VERSION 5.8 ;
BUSBITCHARS "[]" ;
DIVIDERCHAR "/" ;
UNITS
    DATABASE MICRONS 1000 ;
END UNITS

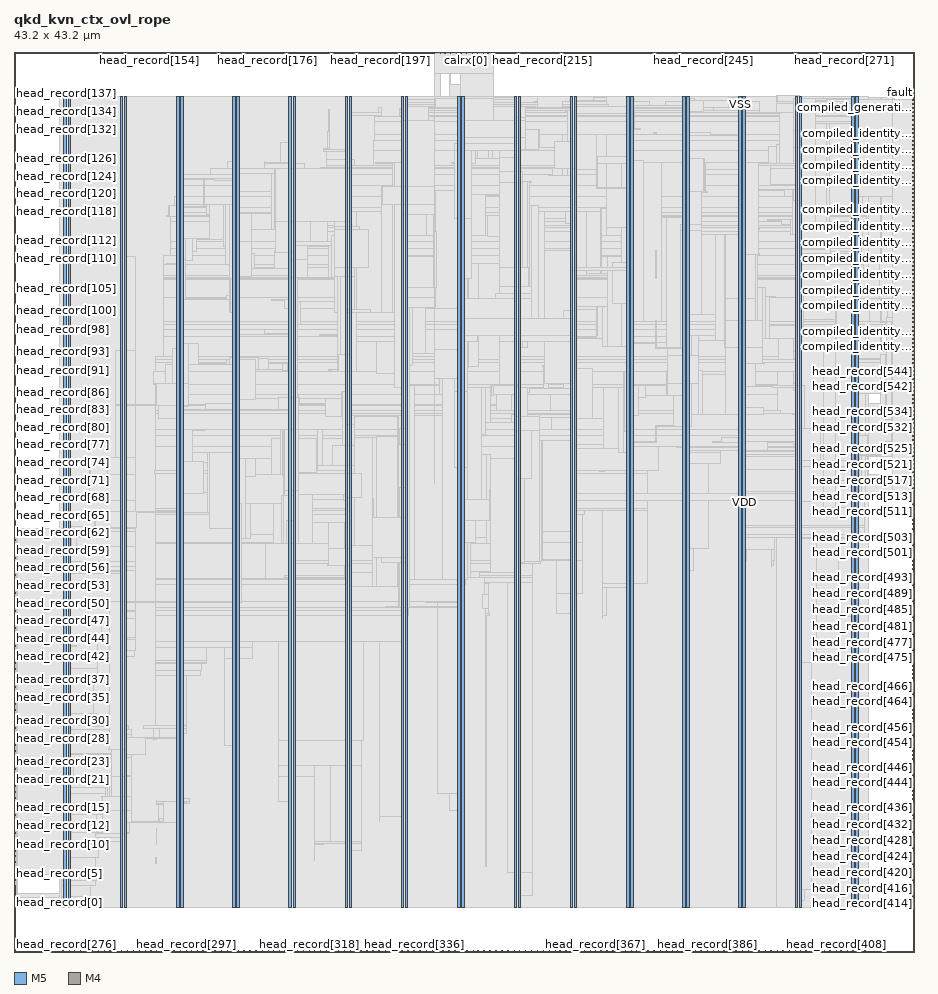
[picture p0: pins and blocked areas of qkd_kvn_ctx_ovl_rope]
MACRO qkd_kvn_ctx_ovl_rope
  FOREIGN qkd_kvn_ctx_ovl_rope 0 0 ;
  CLASS BLOCK ;
  SIZE 43.2 BY 43.2 ;
  PIN adm_done
    DIRECTION INPUT ;
    USE SIGNAL ;
    PORT
      LAYER M5 ;
        RECT  22.752 43.116 22.776 43.2 ;
    END
  END adm_done
  PIN calrx[0]
    DIRECTION INPUT ;
    USE SIGNAL ;
    PORT
      LAYER M5 ;
        RECT  21.696 43.116 21.72 43.2 ;
    END
  END calrx[0]
  PIN calrx[1]
    DIRECTION INPUT ;
    USE SIGNAL ;
    PORT
      LAYER M5 ;
        RECT  21.984 43.116 22.008 43.2 ;
    END
  END calrx[1]
  PIN calrx[2]
    DIRECTION INPUT ;
    USE SIGNAL ;
    PORT
      LAYER M5 ;
        RECT  22.224 43.116 22.248 43.2 ;
    END
  END calrx[2]
  PIN calrx[3]
    DIRECTION INPUT ;
    USE SIGNAL ;
    PORT
      LAYER M5 ;
        RECT  22.512 43.116 22.536 43.2 ;
    END
  END calrx[3]
  PIN ck
    DIRECTION INPUT ;
    USE SIGNAL ;
    PORT
      LAYER M5 ;
        RECT  20.16 43.116 20.184 43.2 ;
    END
  END ck
  PIN compiled_generation[0]
    DIRECTION OUTPUT ;
    USE SIGNAL ;
    PORT
      LAYER M4 ;
        RECT  43.116 40.512 43.2 40.536 ;
    END
  END compiled_generation[0]
  PIN compiled_generation[1]
    DIRECTION OUTPUT ;
    USE SIGNAL ;
    PORT
      LAYER M4 ;
        RECT  43.116 40.704 43.2 40.728 ;
    END
  END compiled_generation[1]
  PIN compiled_identity[0]
    DIRECTION OUTPUT ;
    USE SIGNAL ;
    PORT
      LAYER M4 ;
        RECT  43.116 29.04 43.2 29.064 ;
    END
  END compiled_identity[0]
  PIN compiled_identity[10]
    DIRECTION OUTPUT ;
    USE SIGNAL ;
    PORT
      LAYER M4 ;
        RECT  43.116 31.008 43.2 31.032 ;
    END
  END compiled_identity[10]
  PIN compiled_identity[11]
    DIRECTION OUTPUT ;
    USE SIGNAL ;
    PORT
      LAYER M4 ;
        RECT  43.116 31.2 43.2 31.224 ;
    END
  END compiled_identity[11]
  PIN compiled_identity[12]
    DIRECTION OUTPUT ;
    USE SIGNAL ;
    PORT
      LAYER M4 ;
        RECT  43.116 31.392 43.2 31.416 ;
    END
  END compiled_identity[12]
  PIN compiled_identity[13]
    DIRECTION OUTPUT ;
    USE SIGNAL ;
    PORT
      LAYER M4 ;
        RECT  43.116 31.584 43.2 31.608 ;
    END
  END compiled_identity[13]
  PIN compiled_identity[14]
    DIRECTION OUTPUT ;
    USE SIGNAL ;
    PORT
      LAYER M4 ;
        RECT  43.116 31.776 43.2 31.8 ;
    END
  END compiled_identity[14]
  PIN compiled_identity[15]
    DIRECTION OUTPUT ;
    USE SIGNAL ;
    PORT
      LAYER M4 ;
        RECT  43.116 31.968 43.2 31.992 ;
    END
  END compiled_identity[15]
  PIN compiled_identity[16]
    DIRECTION OUTPUT ;
    USE SIGNAL ;
    PORT
      LAYER M4 ;
        RECT  43.116 32.16 43.2 32.184 ;
    END
  END compiled_identity[16]
  PIN compiled_identity[17]
    DIRECTION OUTPUT ;
    USE SIGNAL ;
    PORT
      LAYER M4 ;
        RECT  43.116 32.352 43.2 32.376 ;
    END
  END compiled_identity[17]
  PIN compiled_identity[18]
    DIRECTION OUTPUT ;
    USE SIGNAL ;
    PORT
      LAYER M4 ;
        RECT  43.116 32.544 43.2 32.568 ;
    END
  END compiled_identity[18]
  PIN compiled_identity[19]
    DIRECTION OUTPUT ;
    USE SIGNAL ;
    PORT
      LAYER M4 ;
        RECT  43.116 32.736 43.2 32.76 ;
    END
  END compiled_identity[19]
  PIN compiled_identity[1]
    DIRECTION OUTPUT ;
    USE SIGNAL ;
    PORT
      LAYER M4 ;
        RECT  43.116 29.232 43.2 29.256 ;
    END
  END compiled_identity[1]
  PIN compiled_identity[20]
    DIRECTION OUTPUT ;
    USE SIGNAL ;
    PORT
      LAYER M4 ;
        RECT  43.116 32.928 43.2 32.952 ;
    END
  END compiled_identity[20]
  PIN compiled_identity[21]
    DIRECTION OUTPUT ;
    USE SIGNAL ;
    PORT
      LAYER M4 ;
        RECT  43.116 33.12 43.2 33.144 ;
    END
  END compiled_identity[21]
  PIN compiled_identity[22]
    DIRECTION OUTPUT ;
    USE SIGNAL ;
    PORT
      LAYER M4 ;
        RECT  43.116 33.312 43.2 33.336 ;
    END
  END compiled_identity[22]
  PIN compiled_identity[23]
    DIRECTION OUTPUT ;
    USE SIGNAL ;
    PORT
      LAYER M4 ;
        RECT  43.116 33.504 43.2 33.528 ;
    END
  END compiled_identity[23]
  PIN compiled_identity[24]
    DIRECTION OUTPUT ;
    USE SIGNAL ;
    PORT
      LAYER M4 ;
        RECT  43.116 33.696 43.2 33.72 ;
    END
  END compiled_identity[24]
  PIN compiled_identity[25]
    DIRECTION OUTPUT ;
    USE SIGNAL ;
    PORT
      LAYER M4 ;
        RECT  43.116 33.888 43.2 33.912 ;
    END
  END compiled_identity[25]
  PIN compiled_identity[26]
    DIRECTION OUTPUT ;
    USE SIGNAL ;
    PORT
      LAYER M4 ;
        RECT  43.116 34.08 43.2 34.104 ;
    END
  END compiled_identity[26]
  PIN compiled_identity[27]
    DIRECTION OUTPUT ;
    USE SIGNAL ;
    PORT
      LAYER M4 ;
        RECT  43.116 34.272 43.2 34.296 ;
    END
  END compiled_identity[27]
  PIN compiled_identity[28]
    DIRECTION OUTPUT ;
    USE SIGNAL ;
    PORT
      LAYER M4 ;
        RECT  43.116 34.464 43.2 34.488 ;
    END
  END compiled_identity[28]
  PIN compiled_identity[29]
    DIRECTION OUTPUT ;
    USE SIGNAL ;
    PORT
      LAYER M4 ;
        RECT  43.116 34.656 43.2 34.68 ;
    END
  END compiled_identity[29]
  PIN compiled_identity[2]
    DIRECTION OUTPUT ;
    USE SIGNAL ;
    PORT
      LAYER M4 ;
        RECT  43.116 29.424 43.2 29.448 ;
    END
  END compiled_identity[2]
  PIN compiled_identity[30]
    DIRECTION OUTPUT ;
    USE SIGNAL ;
    PORT
      LAYER M4 ;
        RECT  43.116 34.848 43.2 34.872 ;
    END
  END compiled_identity[30]
  PIN compiled_identity[31]
    DIRECTION OUTPUT ;
    USE SIGNAL ;
    PORT
      LAYER M4 ;
        RECT  43.116 35.088 43.2 35.112 ;
    END
  END compiled_identity[31]
  PIN compiled_identity[32]
    DIRECTION OUTPUT ;
    USE SIGNAL ;
    PORT
      LAYER M4 ;
        RECT  43.116 35.28 43.2 35.304 ;
    END
  END compiled_identity[32]
  PIN compiled_identity[33]
    DIRECTION OUTPUT ;
    USE SIGNAL ;
    PORT
      LAYER M4 ;
        RECT  43.116 35.472 43.2 35.496 ;
    END
  END compiled_identity[33]
  PIN compiled_identity[34]
    DIRECTION OUTPUT ;
    USE SIGNAL ;
    PORT
      LAYER M4 ;
        RECT  43.116 35.664 43.2 35.688 ;
    END
  END compiled_identity[34]
  PIN compiled_identity[35]
    DIRECTION OUTPUT ;
    USE SIGNAL ;
    PORT
      LAYER M4 ;
        RECT  43.116 35.856 43.2 35.88 ;
    END
  END compiled_identity[35]
  PIN compiled_identity[36]
    DIRECTION OUTPUT ;
    USE SIGNAL ;
    PORT
      LAYER M4 ;
        RECT  43.116 36.048 43.2 36.072 ;
    END
  END compiled_identity[36]
  PIN compiled_identity[37]
    DIRECTION OUTPUT ;
    USE SIGNAL ;
    PORT
      LAYER M4 ;
        RECT  43.116 36.24 43.2 36.264 ;
    END
  END compiled_identity[37]
  PIN compiled_identity[38]
    DIRECTION OUTPUT ;
    USE SIGNAL ;
    PORT
      LAYER M4 ;
        RECT  43.116 36.432 43.2 36.456 ;
    END
  END compiled_identity[38]
  PIN compiled_identity[39]
    DIRECTION OUTPUT ;
    USE SIGNAL ;
    PORT
      LAYER M4 ;
        RECT  43.116 36.624 43.2 36.648 ;
    END
  END compiled_identity[39]
  PIN compiled_identity[3]
    DIRECTION OUTPUT ;
    USE SIGNAL ;
    PORT
      LAYER M4 ;
        RECT  43.116 29.616 43.2 29.64 ;
    END
  END compiled_identity[3]
  PIN compiled_identity[40]
    DIRECTION OUTPUT ;
    USE SIGNAL ;
    PORT
      LAYER M4 ;
        RECT  43.116 36.816 43.2 36.84 ;
    END
  END compiled_identity[40]
  PIN compiled_identity[41]
    DIRECTION OUTPUT ;
    USE SIGNAL ;
    PORT
      LAYER M4 ;
        RECT  43.116 37.008 43.2 37.032 ;
    END
  END compiled_identity[41]
  PIN compiled_identity[42]
    DIRECTION OUTPUT ;
    USE SIGNAL ;
    PORT
      LAYER M4 ;
        RECT  43.116 37.2 43.2 37.224 ;
    END
  END compiled_identity[42]
  PIN compiled_identity[43]
    DIRECTION OUTPUT ;
    USE SIGNAL ;
    PORT
      LAYER M4 ;
        RECT  43.116 37.392 43.2 37.416 ;
    END
  END compiled_identity[43]
  PIN compiled_identity[44]
    DIRECTION OUTPUT ;
    USE SIGNAL ;
    PORT
      LAYER M4 ;
        RECT  43.116 37.584 43.2 37.608 ;
    END
  END compiled_identity[44]
  PIN compiled_identity[45]
    DIRECTION OUTPUT ;
    USE SIGNAL ;
    PORT
      LAYER M4 ;
        RECT  43.116 37.776 43.2 37.8 ;
    END
  END compiled_identity[45]
  PIN compiled_identity[46]
    DIRECTION OUTPUT ;
    USE SIGNAL ;
    PORT
      LAYER M4 ;
        RECT  43.116 37.968 43.2 37.992 ;
    END
  END compiled_identity[46]
  PIN compiled_identity[47]
    DIRECTION OUTPUT ;
    USE SIGNAL ;
    PORT
      LAYER M4 ;
        RECT  43.116 38.16 43.2 38.184 ;
    END
  END compiled_identity[47]
  PIN compiled_identity[48]
    DIRECTION OUTPUT ;
    USE SIGNAL ;
    PORT
      LAYER M4 ;
        RECT  43.116 38.352 43.2 38.376 ;
    END
  END compiled_identity[48]
  PIN compiled_identity[49]
    DIRECTION OUTPUT ;
    USE SIGNAL ;
    PORT
      LAYER M4 ;
        RECT  43.116 38.544 43.2 38.568 ;
    END
  END compiled_identity[49]
  PIN compiled_identity[4]
    DIRECTION OUTPUT ;
    USE SIGNAL ;
    PORT
      LAYER M4 ;
        RECT  43.116 29.808 43.2 29.832 ;
    END
  END compiled_identity[4]
  PIN compiled_identity[50]
    DIRECTION OUTPUT ;
    USE SIGNAL ;
    PORT
      LAYER M4 ;
        RECT  43.116 38.736 43.2 38.76 ;
    END
  END compiled_identity[50]
  PIN compiled_identity[51]
    DIRECTION OUTPUT ;
    USE SIGNAL ;
    PORT
      LAYER M4 ;
        RECT  43.116 38.928 43.2 38.952 ;
    END
  END compiled_identity[51]
  PIN compiled_identity[52]
    DIRECTION OUTPUT ;
    USE SIGNAL ;
    PORT
      LAYER M4 ;
        RECT  43.116 39.12 43.2 39.144 ;
    END
  END compiled_identity[52]
  PIN compiled_identity[53]
    DIRECTION OUTPUT ;
    USE SIGNAL ;
    PORT
      LAYER M4 ;
        RECT  43.116 39.312 43.2 39.336 ;
    END
  END compiled_identity[53]
  PIN compiled_identity[54]
    DIRECTION OUTPUT ;
    USE SIGNAL ;
    PORT
      LAYER M4 ;
        RECT  43.116 39.504 43.2 39.528 ;
    END
  END compiled_identity[54]
  PIN compiled_identity[55]
    DIRECTION OUTPUT ;
    USE SIGNAL ;
    PORT
      LAYER M4 ;
        RECT  43.116 39.696 43.2 39.72 ;
    END
  END compiled_identity[55]
  PIN compiled_identity[56]
    DIRECTION OUTPUT ;
    USE SIGNAL ;
    PORT
      LAYER M4 ;
        RECT  43.116 39.936 43.2 39.96 ;
    END
  END compiled_identity[56]
  PIN compiled_identity[57]
    DIRECTION OUTPUT ;
    USE SIGNAL ;
    PORT
      LAYER M4 ;
        RECT  43.116 40.128 43.2 40.152 ;
    END
  END compiled_identity[57]
  PIN compiled_identity[58]
    DIRECTION OUTPUT ;
    USE SIGNAL ;
    PORT
      LAYER M4 ;
        RECT  43.116 40.32 43.2 40.344 ;
    END
  END compiled_identity[58]
  PIN compiled_identity[5]
    DIRECTION OUTPUT ;
    USE SIGNAL ;
    PORT
      LAYER M4 ;
        RECT  43.116 30 43.2 30.024 ;
    END
  END compiled_identity[5]
  PIN compiled_identity[6]
    DIRECTION OUTPUT ;
    USE SIGNAL ;
    PORT
      LAYER M4 ;
        RECT  43.116 30.24 43.2 30.264 ;
    END
  END compiled_identity[6]
  PIN compiled_identity[7]
    DIRECTION OUTPUT ;
    USE SIGNAL ;
    PORT
      LAYER M4 ;
        RECT  43.116 30.432 43.2 30.456 ;
    END
  END compiled_identity[7]
  PIN compiled_identity[8]
    DIRECTION OUTPUT ;
    USE SIGNAL ;
    PORT
      LAYER M4 ;
        RECT  43.116 30.624 43.2 30.648 ;
    END
  END compiled_identity[8]
  PIN compiled_identity[9]
    DIRECTION OUTPUT ;
    USE SIGNAL ;
    PORT
      LAYER M4 ;
        RECT  43.116 30.816 43.2 30.84 ;
    END
  END compiled_identity[9]
  PIN fault
    DIRECTION OUTPUT ;
    USE SIGNAL ;
    PORT
      LAYER M4 ;
        RECT  43.116 40.896 43.2 40.92 ;
    END
  END fault
  PIN head_record[0]
    DIRECTION INPUT ;
    USE SIGNAL ;
    PORT
      LAYER M4 ;
        RECT  0 2.352 0.084 2.376 ;
    END
  END head_record[0]
  PIN head_record[100]
    DIRECTION INPUT ;
    USE SIGNAL ;
    PORT
      LAYER M4 ;
        RECT  0 30.432 0.084 30.456 ;
    END
  END head_record[100]
  PIN head_record[101]
    DIRECTION INPUT ;
    USE SIGNAL ;
    PORT
      LAYER M4 ;
        RECT  0 30.72 0.084 30.744 ;
    END
  END head_record[101]
  PIN head_record[102]
    DIRECTION INPUT ;
    USE SIGNAL ;
    PORT
      LAYER M4 ;
        RECT  0 31.008 0.084 31.032 ;
    END
  END head_record[102]
  PIN head_record[103]
    DIRECTION INPUT ;
    USE SIGNAL ;
    PORT
      LAYER M4 ;
        RECT  0 31.296 0.084 31.32 ;
    END
  END head_record[103]
  PIN head_record[104]
    DIRECTION INPUT ;
    USE SIGNAL ;
    PORT
      LAYER M4 ;
        RECT  0 31.584 0.084 31.608 ;
    END
  END head_record[104]
  PIN head_record[105]
    DIRECTION INPUT ;
    USE SIGNAL ;
    PORT
      LAYER M4 ;
        RECT  0 31.824 0.084 31.848 ;
    END
  END head_record[105]
  PIN head_record[106]
    DIRECTION INPUT ;
    USE SIGNAL ;
    PORT
      LAYER M4 ;
        RECT  0 32.112 0.084 32.136 ;
    END
  END head_record[106]
  PIN head_record[107]
    DIRECTION INPUT ;
    USE SIGNAL ;
    PORT
      LAYER M4 ;
        RECT  0 32.4 0.084 32.424 ;
    END
  END head_record[107]
  PIN head_record[108]
    DIRECTION INPUT ;
    USE SIGNAL ;
    PORT
      LAYER M4 ;
        RECT  0 32.688 0.084 32.712 ;
    END
  END head_record[108]
  PIN head_record[109]
    DIRECTION INPUT ;
    USE SIGNAL ;
    PORT
      LAYER M4 ;
        RECT  0 32.976 0.084 33 ;
    END
  END head_record[109]
  PIN head_record[10]
    DIRECTION INPUT ;
    USE SIGNAL ;
    PORT
      LAYER M4 ;
        RECT  0 5.136 0.084 5.16 ;
    END
  END head_record[10]
  PIN head_record[110]
    DIRECTION INPUT ;
    USE SIGNAL ;
    PORT
      LAYER M4 ;
        RECT  0 33.264 0.084 33.288 ;
    END
  END head_record[110]
  PIN head_record[111]
    DIRECTION INPUT ;
    USE SIGNAL ;
    PORT
      LAYER M4 ;
        RECT  0 33.552 0.084 33.576 ;
    END
  END head_record[111]
  PIN head_record[112]
    DIRECTION INPUT ;
    USE SIGNAL ;
    PORT
      LAYER M4 ;
        RECT  0 33.792 0.084 33.816 ;
    END
  END head_record[112]
  PIN head_record[113]
    DIRECTION INPUT ;
    USE SIGNAL ;
    PORT
      LAYER M4 ;
        RECT  0 34.08 0.084 34.104 ;
    END
  END head_record[113]
  PIN head_record[114]
    DIRECTION INPUT ;
    USE SIGNAL ;
    PORT
      LAYER M4 ;
        RECT  0 34.368 0.084 34.392 ;
    END
  END head_record[114]
  PIN head_record[115]
    DIRECTION INPUT ;
    USE SIGNAL ;
    PORT
      LAYER M4 ;
        RECT  0 34.656 0.084 34.68 ;
    END
  END head_record[115]
  PIN head_record[116]
    DIRECTION INPUT ;
    USE SIGNAL ;
    PORT
      LAYER M4 ;
        RECT  0 34.944 0.084 34.968 ;
    END
  END head_record[116]
  PIN head_record[117]
    DIRECTION INPUT ;
    USE SIGNAL ;
    PORT
      LAYER M4 ;
        RECT  0 35.232 0.084 35.256 ;
    END
  END head_record[117]
  PIN head_record[118]
    DIRECTION INPUT ;
    USE SIGNAL ;
    PORT
      LAYER M4 ;
        RECT  0 35.52 0.084 35.544 ;
    END
  END head_record[118]
  PIN head_record[119]
    DIRECTION INPUT ;
    USE SIGNAL ;
    PORT
      LAYER M4 ;
        RECT  0 35.76 0.084 35.784 ;
    END
  END head_record[119]
  PIN head_record[11]
    DIRECTION INPUT ;
    USE SIGNAL ;
    PORT
      LAYER M4 ;
        RECT  0 5.424 0.084 5.448 ;
    END
  END head_record[11]
  PIN head_record[120]
    DIRECTION INPUT ;
    USE SIGNAL ;
    PORT
      LAYER M4 ;
        RECT  0 36.048 0.084 36.072 ;
    END
  END head_record[120]
  PIN head_record[121]
    DIRECTION INPUT ;
    USE SIGNAL ;
    PORT
      LAYER M4 ;
        RECT  0 36.336 0.084 36.36 ;
    END
  END head_record[121]
  PIN head_record[122]
    DIRECTION INPUT ;
    USE SIGNAL ;
    PORT
      LAYER M4 ;
        RECT  0 36.624 0.084 36.648 ;
    END
  END head_record[122]
  PIN head_record[123]
    DIRECTION INPUT ;
    USE SIGNAL ;
    PORT
      LAYER M4 ;
        RECT  0 36.912 0.084 36.936 ;
    END
  END head_record[123]
  PIN head_record[124]
    DIRECTION INPUT ;
    USE SIGNAL ;
    PORT
      LAYER M4 ;
        RECT  0 37.2 0.084 37.224 ;
    END
  END head_record[124]
  PIN head_record[125]
    DIRECTION INPUT ;
    USE SIGNAL ;
    PORT
      LAYER M4 ;
        RECT  0 37.488 0.084 37.512 ;
    END
  END head_record[125]
  PIN head_record[126]
    DIRECTION INPUT ;
    USE SIGNAL ;
    PORT
      LAYER M4 ;
        RECT  0 37.728 0.084 37.752 ;
    END
  END head_record[126]
  PIN head_record[127]
    DIRECTION INPUT ;
    USE SIGNAL ;
    PORT
      LAYER M4 ;
        RECT  0 38.016 0.084 38.04 ;
    END
  END head_record[127]
  PIN head_record[128]
    DIRECTION INPUT ;
    USE SIGNAL ;
    PORT
      LAYER M4 ;
        RECT  0 38.304 0.084 38.328 ;
    END
  END head_record[128]
  PIN head_record[129]
    DIRECTION INPUT ;
    USE SIGNAL ;
    PORT
      LAYER M4 ;
        RECT  0 38.592 0.084 38.616 ;
    END
  END head_record[129]
  PIN head_record[12]
    DIRECTION INPUT ;
    USE SIGNAL ;
    PORT
      LAYER M4 ;
        RECT  0 5.712 0.084 5.736 ;
    END
  END head_record[12]
  PIN head_record[130]
    DIRECTION INPUT ;
    USE SIGNAL ;
    PORT
      LAYER M4 ;
        RECT  0 38.88 0.084 38.904 ;
    END
  END head_record[130]
  PIN head_record[131]
    DIRECTION INPUT ;
    USE SIGNAL ;
    PORT
      LAYER M4 ;
        RECT  0 39.168 0.084 39.192 ;
    END
  END head_record[131]
  PIN head_record[132]
    DIRECTION INPUT ;
    USE SIGNAL ;
    PORT
      LAYER M4 ;
        RECT  0 39.456 0.084 39.48 ;
    END
  END head_record[132]
  PIN head_record[133]
    DIRECTION INPUT ;
    USE SIGNAL ;
    PORT
      LAYER M4 ;
        RECT  0 39.696 0.084 39.72 ;
    END
  END head_record[133]
  PIN head_record[134]
    DIRECTION INPUT ;
    USE SIGNAL ;
    PORT
      LAYER M4 ;
        RECT  0 39.984 0.084 40.008 ;
    END
  END head_record[134]
  PIN head_record[135]
    DIRECTION INPUT ;
    USE SIGNAL ;
    PORT
      LAYER M4 ;
        RECT  0 40.272 0.084 40.296 ;
    END
  END head_record[135]
  PIN head_record[136]
    DIRECTION INPUT ;
    USE SIGNAL ;
    PORT
      LAYER M4 ;
        RECT  0 40.56 0.084 40.584 ;
    END
  END head_record[136]
  PIN head_record[137]
    DIRECTION INPUT ;
    USE SIGNAL ;
    PORT
      LAYER M4 ;
        RECT  0 40.848 0.084 40.872 ;
    END
  END head_record[137]
  PIN head_record[138]
    DIRECTION INPUT ;
    USE SIGNAL ;
    PORT
      LAYER M5 ;
        RECT  2.304 43.116 2.328 43.2 ;
    END
  END head_record[138]
  PIN head_record[139]
    DIRECTION INPUT ;
    USE SIGNAL ;
    PORT
      LAYER M5 ;
        RECT  2.592 43.116 2.616 43.2 ;
    END
  END head_record[139]
  PIN head_record[13]
    DIRECTION INPUT ;
    USE SIGNAL ;
    PORT
      LAYER M4 ;
        RECT  0 6 0.084 6.024 ;
    END
  END head_record[13]
  PIN head_record[140]
    DIRECTION INPUT ;
    USE SIGNAL ;
    PORT
      LAYER M5 ;
        RECT  2.832 43.116 2.856 43.2 ;
    END
  END head_record[140]
  PIN head_record[141]
    DIRECTION INPUT ;
    USE SIGNAL ;
    PORT
      LAYER M5 ;
        RECT  3.12 43.116 3.144 43.2 ;
    END
  END head_record[141]
  PIN head_record[142]
    DIRECTION INPUT ;
    USE SIGNAL ;
    PORT
      LAYER M5 ;
        RECT  3.36 43.116 3.384 43.2 ;
    END
  END head_record[142]
  PIN head_record[143]
    DIRECTION INPUT ;
    USE SIGNAL ;
    PORT
      LAYER M5 ;
        RECT  3.6 43.116 3.624 43.2 ;
    END
  END head_record[143]
  PIN head_record[144]
    DIRECTION INPUT ;
    USE SIGNAL ;
    PORT
      LAYER M5 ;
        RECT  3.888 43.116 3.912 43.2 ;
    END
  END head_record[144]
  PIN head_record[145]
    DIRECTION INPUT ;
    USE SIGNAL ;
    PORT
      LAYER M5 ;
        RECT  4.128 43.116 4.152 43.2 ;
    END
  END head_record[145]
  PIN head_record[146]
    DIRECTION INPUT ;
    USE SIGNAL ;
    PORT
      LAYER M5 ;
        RECT  4.416 43.116 4.44 43.2 ;
    END
  END head_record[146]
  PIN head_record[147]
    DIRECTION INPUT ;
    USE SIGNAL ;
    PORT
      LAYER M5 ;
        RECT  4.656 43.116 4.68 43.2 ;
    END
  END head_record[147]
  PIN head_record[148]
    DIRECTION INPUT ;
    USE SIGNAL ;
    PORT
      LAYER M5 ;
        RECT  4.896 43.116 4.92 43.2 ;
    END
  END head_record[148]
  PIN head_record[149]
    DIRECTION INPUT ;
    USE SIGNAL ;
    PORT
      LAYER M5 ;
        RECT  5.184 43.116 5.208 43.2 ;
    END
  END head_record[149]
  PIN head_record[14]
    DIRECTION INPUT ;
    USE SIGNAL ;
    PORT
      LAYER M4 ;
        RECT  0 6.288 0.084 6.312 ;
    END
  END head_record[14]
  PIN head_record[150]
    DIRECTION INPUT ;
    USE SIGNAL ;
    PORT
      LAYER M5 ;
        RECT  5.424 43.116 5.448 43.2 ;
    END
  END head_record[150]
  PIN head_record[151]
    DIRECTION INPUT ;
    USE SIGNAL ;
    PORT
      LAYER M5 ;
        RECT  5.664 43.116 5.688 43.2 ;
    END
  END head_record[151]
  PIN head_record[152]
    DIRECTION INPUT ;
    USE SIGNAL ;
    PORT
      LAYER M5 ;
        RECT  5.952 43.116 5.976 43.2 ;
    END
  END head_record[152]
  PIN head_record[153]
    DIRECTION INPUT ;
    USE SIGNAL ;
    PORT
      LAYER M5 ;
        RECT  6.192 43.116 6.216 43.2 ;
    END
  END head_record[153]
  PIN head_record[154]
    DIRECTION INPUT ;
    USE SIGNAL ;
    PORT
      LAYER M5 ;
        RECT  6.48 43.116 6.504 43.2 ;
    END
  END head_record[154]
  PIN head_record[155]
    DIRECTION INPUT ;
    USE SIGNAL ;
    PORT
      LAYER M5 ;
        RECT  6.72 43.116 6.744 43.2 ;
    END
  END head_record[155]
  PIN head_record[156]
    DIRECTION INPUT ;
    USE SIGNAL ;
    PORT
      LAYER M5 ;
        RECT  6.96 43.116 6.984 43.2 ;
    END
  END head_record[156]
  PIN head_record[157]
    DIRECTION INPUT ;
    USE SIGNAL ;
    PORT
      LAYER M5 ;
        RECT  7.248 43.116 7.272 43.2 ;
    END
  END head_record[157]
  PIN head_record[158]
    DIRECTION INPUT ;
    USE SIGNAL ;
    PORT
      LAYER M5 ;
        RECT  7.488 43.116 7.512 43.2 ;
    END
  END head_record[158]
  PIN head_record[159]
    DIRECTION INPUT ;
    USE SIGNAL ;
    PORT
      LAYER M5 ;
        RECT  7.776 43.116 7.8 43.2 ;
    END
  END head_record[159]
  PIN head_record[15]
    DIRECTION INPUT ;
    USE SIGNAL ;
    PORT
      LAYER M4 ;
        RECT  0 6.576 0.084 6.6 ;
    END
  END head_record[15]
  PIN head_record[160]
    DIRECTION INPUT ;
    USE SIGNAL ;
    PORT
      LAYER M5 ;
        RECT  8.016 43.116 8.04 43.2 ;
    END
  END head_record[160]
  PIN head_record[161]
    DIRECTION INPUT ;
    USE SIGNAL ;
    PORT
      LAYER M5 ;
        RECT  8.256 43.116 8.28 43.2 ;
    END
  END head_record[161]
  PIN head_record[162]
    DIRECTION INPUT ;
    USE SIGNAL ;
    PORT
      LAYER M5 ;
        RECT  8.544 43.116 8.568 43.2 ;
    END
  END head_record[162]
  PIN head_record[163]
    DIRECTION INPUT ;
    USE SIGNAL ;
    PORT
      LAYER M5 ;
        RECT  8.784 43.116 8.808 43.2 ;
    END
  END head_record[163]
  PIN head_record[164]
    DIRECTION INPUT ;
    USE SIGNAL ;
    PORT
      LAYER M5 ;
        RECT  9.024 43.116 9.048 43.2 ;
    END
  END head_record[164]
  PIN head_record[165]
    DIRECTION INPUT ;
    USE SIGNAL ;
    PORT
      LAYER M5 ;
        RECT  9.312 43.116 9.336 43.2 ;
    END
  END head_record[165]
  PIN head_record[166]
    DIRECTION INPUT ;
    USE SIGNAL ;
    PORT
      LAYER M5 ;
        RECT  9.552 43.116 9.576 43.2 ;
    END
  END head_record[166]
  PIN head_record[167]
    DIRECTION INPUT ;
    USE SIGNAL ;
    PORT
      LAYER M5 ;
        RECT  9.84 43.116 9.864 43.2 ;
    END
  END head_record[167]
  PIN head_record[168]
    DIRECTION INPUT ;
    USE SIGNAL ;
    PORT
      LAYER M5 ;
        RECT  10.08 43.116 10.104 43.2 ;
    END
  END head_record[168]
  PIN head_record[169]
    DIRECTION INPUT ;
    USE SIGNAL ;
    PORT
      LAYER M5 ;
        RECT  10.32 43.116 10.344 43.2 ;
    END
  END head_record[169]
  PIN head_record[16]
    DIRECTION INPUT ;
    USE SIGNAL ;
    PORT
      LAYER M4 ;
        RECT  0 6.816 0.084 6.84 ;
    END
  END head_record[16]
  PIN head_record[170]
    DIRECTION INPUT ;
    USE SIGNAL ;
    PORT
      LAYER M5 ;
        RECT  10.608 43.116 10.632 43.2 ;
    END
  END head_record[170]
  PIN head_record[171]
    DIRECTION INPUT ;
    USE SIGNAL ;
    PORT
      LAYER M5 ;
        RECT  10.848 43.116 10.872 43.2 ;
    END
  END head_record[171]
  PIN head_record[172]
    DIRECTION INPUT ;
    USE SIGNAL ;
    PORT
      LAYER M5 ;
        RECT  11.136 43.116 11.16 43.2 ;
    END
  END head_record[172]
  PIN head_record[173]
    DIRECTION INPUT ;
    USE SIGNAL ;
    PORT
      LAYER M5 ;
        RECT  11.376 43.116 11.4 43.2 ;
    END
  END head_record[173]
  PIN head_record[174]
    DIRECTION INPUT ;
    USE SIGNAL ;
    PORT
      LAYER M5 ;
        RECT  11.616 43.116 11.64 43.2 ;
    END
  END head_record[174]
  PIN head_record[175]
    DIRECTION INPUT ;
    USE SIGNAL ;
    PORT
      LAYER M5 ;
        RECT  11.904 43.116 11.928 43.2 ;
    END
  END head_record[175]
  PIN head_record[176]
    DIRECTION INPUT ;
    USE SIGNAL ;
    PORT
      LAYER M5 ;
        RECT  12.144 43.116 12.168 43.2 ;
    END
  END head_record[176]
  PIN head_record[177]
    DIRECTION INPUT ;
    USE SIGNAL ;
    PORT
      LAYER M5 ;
        RECT  12.432 43.116 12.456 43.2 ;
    END
  END head_record[177]
  PIN head_record[178]
    DIRECTION INPUT ;
    USE SIGNAL ;
    PORT
      LAYER M5 ;
        RECT  12.672 43.116 12.696 43.2 ;
    END
  END head_record[178]
  PIN head_record[179]
    DIRECTION INPUT ;
    USE SIGNAL ;
    PORT
      LAYER M5 ;
        RECT  12.912 43.116 12.936 43.2 ;
    END
  END head_record[179]
  PIN head_record[17]
    DIRECTION INPUT ;
    USE SIGNAL ;
    PORT
      LAYER M4 ;
        RECT  0 7.104 0.084 7.128 ;
    END
  END head_record[17]
  PIN head_record[180]
    DIRECTION INPUT ;
    USE SIGNAL ;
    PORT
      LAYER M5 ;
        RECT  13.2 43.116 13.224 43.2 ;
    END
  END head_record[180]
  PIN head_record[181]
    DIRECTION INPUT ;
    USE SIGNAL ;
    PORT
      LAYER M5 ;
        RECT  13.44 43.116 13.464 43.2 ;
    END
  END head_record[181]
  PIN head_record[182]
    DIRECTION INPUT ;
    USE SIGNAL ;
    PORT
      LAYER M5 ;
        RECT  13.68 43.116 13.704 43.2 ;
    END
  END head_record[182]
  PIN head_record[183]
    DIRECTION INPUT ;
    USE SIGNAL ;
    PORT
      LAYER M5 ;
        RECT  13.968 43.116 13.992 43.2 ;
    END
  END head_record[183]
  PIN head_record[184]
    DIRECTION INPUT ;
    USE SIGNAL ;
    PORT
      LAYER M5 ;
        RECT  14.208 43.116 14.232 43.2 ;
    END
  END head_record[184]
  PIN head_record[185]
    DIRECTION INPUT ;
    USE SIGNAL ;
    PORT
      LAYER M5 ;
        RECT  14.496 43.116 14.52 43.2 ;
    END
  END head_record[185]
  PIN head_record[186]
    DIRECTION INPUT ;
    USE SIGNAL ;
    PORT
      LAYER M5 ;
        RECT  14.736 43.116 14.76 43.2 ;
    END
  END head_record[186]
  PIN head_record[187]
    DIRECTION INPUT ;
    USE SIGNAL ;
    PORT
      LAYER M5 ;
        RECT  14.976 43.116 15 43.2 ;
    END
  END head_record[187]
  PIN head_record[188]
    DIRECTION INPUT ;
    USE SIGNAL ;
    PORT
      LAYER M5 ;
        RECT  15.264 43.116 15.288 43.2 ;
    END
  END head_record[188]
  PIN head_record[189]
    DIRECTION INPUT ;
    USE SIGNAL ;
    PORT
      LAYER M5 ;
        RECT  15.504 43.116 15.528 43.2 ;
    END
  END head_record[189]
  PIN head_record[18]
    DIRECTION INPUT ;
    USE SIGNAL ;
    PORT
      LAYER M4 ;
        RECT  0 7.392 0.084 7.416 ;
    END
  END head_record[18]
  PIN head_record[190]
    DIRECTION INPUT ;
    USE SIGNAL ;
    PORT
      LAYER M5 ;
        RECT  15.792 43.116 15.816 43.2 ;
    END
  END head_record[190]
  PIN head_record[191]
    DIRECTION INPUT ;
    USE SIGNAL ;
    PORT
      LAYER M5 ;
        RECT  16.032 43.116 16.056 43.2 ;
    END
  END head_record[191]
  PIN head_record[192]
    DIRECTION INPUT ;
    USE SIGNAL ;
    PORT
      LAYER M5 ;
        RECT  16.272 43.116 16.296 43.2 ;
    END
  END head_record[192]
  PIN head_record[193]
    DIRECTION INPUT ;
    USE SIGNAL ;
    PORT
      LAYER M5 ;
        RECT  16.56 43.116 16.584 43.2 ;
    END
  END head_record[193]
  PIN head_record[194]
    DIRECTION INPUT ;
    USE SIGNAL ;
    PORT
      LAYER M5 ;
        RECT  16.8 43.116 16.824 43.2 ;
    END
  END head_record[194]
  PIN head_record[195]
    DIRECTION INPUT ;
    USE SIGNAL ;
    PORT
      LAYER M5 ;
        RECT  17.04 43.116 17.064 43.2 ;
    END
  END head_record[195]
  PIN head_record[196]
    DIRECTION INPUT ;
    USE SIGNAL ;
    PORT
      LAYER M5 ;
        RECT  17.328 43.116 17.352 43.2 ;
    END
  END head_record[196]
  PIN head_record[197]
    DIRECTION INPUT ;
    USE SIGNAL ;
    PORT
      LAYER M5 ;
        RECT  17.568 43.116 17.592 43.2 ;
    END
  END head_record[197]
  PIN head_record[198]
    DIRECTION INPUT ;
    USE SIGNAL ;
    PORT
      LAYER M5 ;
        RECT  17.856 43.116 17.88 43.2 ;
    END
  END head_record[198]
  PIN head_record[199]
    DIRECTION INPUT ;
    USE SIGNAL ;
    PORT
      LAYER M5 ;
        RECT  18.096 43.116 18.12 43.2 ;
    END
  END head_record[199]
  PIN head_record[19]
    DIRECTION INPUT ;
    USE SIGNAL ;
    PORT
      LAYER M4 ;
        RECT  0 7.68 0.084 7.704 ;
    END
  END head_record[19]
  PIN head_record[1]
    DIRECTION INPUT ;
    USE SIGNAL ;
    PORT
      LAYER M4 ;
        RECT  0 2.64 0.084 2.664 ;
    END
  END head_record[1]
  PIN head_record[200]
    DIRECTION INPUT ;
    USE SIGNAL ;
    PORT
      LAYER M5 ;
        RECT  18.336 43.116 18.36 43.2 ;
    END
  END head_record[200]
  PIN head_record[201]
    DIRECTION INPUT ;
    USE SIGNAL ;
    PORT
      LAYER M5 ;
        RECT  18.624 43.116 18.648 43.2 ;
    END
  END head_record[201]
  PIN head_record[202]
    DIRECTION INPUT ;
    USE SIGNAL ;
    PORT
      LAYER M5 ;
        RECT  18.864 43.116 18.888 43.2 ;
    END
  END head_record[202]
  PIN head_record[203]
    DIRECTION INPUT ;
    USE SIGNAL ;
    PORT
      LAYER M5 ;
        RECT  19.152 43.116 19.176 43.2 ;
    END
  END head_record[203]
  PIN head_record[204]
    DIRECTION INPUT ;
    USE SIGNAL ;
    PORT
      LAYER M5 ;
        RECT  19.392 43.116 19.416 43.2 ;
    END
  END head_record[204]
  PIN head_record[205]
    DIRECTION INPUT ;
    USE SIGNAL ;
    PORT
      LAYER M5 ;
        RECT  19.632 43.116 19.656 43.2 ;
    END
  END head_record[205]
  PIN head_record[206]
    DIRECTION INPUT ;
    USE SIGNAL ;
    PORT
      LAYER M5 ;
        RECT  19.92 43.116 19.944 43.2 ;
    END
  END head_record[206]
  PIN head_record[207]
    DIRECTION INPUT ;
    USE SIGNAL ;
    PORT
      LAYER M5 ;
        RECT  23.28 43.116 23.304 43.2 ;
    END
  END head_record[207]
  PIN head_record[208]
    DIRECTION INPUT ;
    USE SIGNAL ;
    PORT
      LAYER M5 ;
        RECT  23.52 43.116 23.544 43.2 ;
    END
  END head_record[208]
  PIN head_record[209]
    DIRECTION INPUT ;
    USE SIGNAL ;
    PORT
      LAYER M5 ;
        RECT  23.808 43.116 23.832 43.2 ;
    END
  END head_record[209]
  PIN head_record[20]
    DIRECTION INPUT ;
    USE SIGNAL ;
    PORT
      LAYER M4 ;
        RECT  0 7.968 0.084 7.992 ;
    END
  END head_record[20]
  PIN head_record[210]
    DIRECTION INPUT ;
    USE SIGNAL ;
    PORT
      LAYER M5 ;
        RECT  24.048 43.116 24.072 43.2 ;
    END
  END head_record[210]
  PIN head_record[211]
    DIRECTION INPUT ;
    USE SIGNAL ;
    PORT
      LAYER M5 ;
        RECT  24.288 43.116 24.312 43.2 ;
    END
  END head_record[211]
  PIN head_record[212]
    DIRECTION INPUT ;
    USE SIGNAL ;
    PORT
      LAYER M5 ;
        RECT  24.576 43.116 24.6 43.2 ;
    END
  END head_record[212]
  PIN head_record[213]
    DIRECTION INPUT ;
    USE SIGNAL ;
    PORT
      LAYER M5 ;
        RECT  24.816 43.116 24.84 43.2 ;
    END
  END head_record[213]
  PIN head_record[214]
    DIRECTION INPUT ;
    USE SIGNAL ;
    PORT
      LAYER M5 ;
        RECT  25.056 43.116 25.08 43.2 ;
    END
  END head_record[214]
  PIN head_record[215]
    DIRECTION INPUT ;
    USE SIGNAL ;
    PORT
      LAYER M5 ;
        RECT  25.344 43.116 25.368 43.2 ;
    END
  END head_record[215]
  PIN head_record[216]
    DIRECTION INPUT ;
    USE SIGNAL ;
    PORT
      LAYER M5 ;
        RECT  25.584 43.116 25.608 43.2 ;
    END
  END head_record[216]
  PIN head_record[217]
    DIRECTION INPUT ;
    USE SIGNAL ;
    PORT
      LAYER M5 ;
        RECT  25.872 43.116 25.896 43.2 ;
    END
  END head_record[217]
  PIN head_record[218]
    DIRECTION INPUT ;
    USE SIGNAL ;
    PORT
      LAYER M5 ;
        RECT  26.112 43.116 26.136 43.2 ;
    END
  END head_record[218]
  PIN head_record[219]
    DIRECTION INPUT ;
    USE SIGNAL ;
    PORT
      LAYER M5 ;
        RECT  26.352 43.116 26.376 43.2 ;
    END
  END head_record[219]
  PIN head_record[21]
    DIRECTION INPUT ;
    USE SIGNAL ;
    PORT
      LAYER M4 ;
        RECT  0 8.256 0.084 8.28 ;
    END
  END head_record[21]
  PIN head_record[220]
    DIRECTION INPUT ;
    USE SIGNAL ;
    PORT
      LAYER M5 ;
        RECT  26.64 43.116 26.664 43.2 ;
    END
  END head_record[220]
  PIN head_record[221]
    DIRECTION INPUT ;
    USE SIGNAL ;
    PORT
      LAYER M5 ;
        RECT  26.88 43.116 26.904 43.2 ;
    END
  END head_record[221]
  PIN head_record[222]
    DIRECTION INPUT ;
    USE SIGNAL ;
    PORT
      LAYER M5 ;
        RECT  27.168 43.116 27.192 43.2 ;
    END
  END head_record[222]
  PIN head_record[223]
    DIRECTION INPUT ;
    USE SIGNAL ;
    PORT
      LAYER M5 ;
        RECT  27.408 43.116 27.432 43.2 ;
    END
  END head_record[223]
  PIN head_record[224]
    DIRECTION INPUT ;
    USE SIGNAL ;
    PORT
      LAYER M5 ;
        RECT  27.648 43.116 27.672 43.2 ;
    END
  END head_record[224]
  PIN head_record[225]
    DIRECTION INPUT ;
    USE SIGNAL ;
    PORT
      LAYER M5 ;
        RECT  27.936 43.116 27.96 43.2 ;
    END
  END head_record[225]
  PIN head_record[226]
    DIRECTION INPUT ;
    USE SIGNAL ;
    PORT
      LAYER M5 ;
        RECT  28.176 43.116 28.2 43.2 ;
    END
  END head_record[226]
  PIN head_record[227]
    DIRECTION INPUT ;
    USE SIGNAL ;
    PORT
      LAYER M5 ;
        RECT  28.416 43.116 28.44 43.2 ;
    END
  END head_record[227]
  PIN head_record[228]
    DIRECTION INPUT ;
    USE SIGNAL ;
    PORT
      LAYER M5 ;
        RECT  28.704 43.116 28.728 43.2 ;
    END
  END head_record[228]
  PIN head_record[229]
    DIRECTION INPUT ;
    USE SIGNAL ;
    PORT
      LAYER M5 ;
        RECT  28.944 43.116 28.968 43.2 ;
    END
  END head_record[229]
  PIN head_record[22]
    DIRECTION INPUT ;
    USE SIGNAL ;
    PORT
      LAYER M4 ;
        RECT  0 8.496 0.084 8.52 ;
    END
  END head_record[22]
  PIN head_record[230]
    DIRECTION INPUT ;
    USE SIGNAL ;
    PORT
      LAYER M5 ;
        RECT  29.232 43.116 29.256 43.2 ;
    END
  END head_record[230]
  PIN head_record[231]
    DIRECTION INPUT ;
    USE SIGNAL ;
    PORT
      LAYER M5 ;
        RECT  29.472 43.116 29.496 43.2 ;
    END
  END head_record[231]
  PIN head_record[232]
    DIRECTION INPUT ;
    USE SIGNAL ;
    PORT
      LAYER M5 ;
        RECT  29.712 43.116 29.736 43.2 ;
    END
  END head_record[232]
  PIN head_record[233]
    DIRECTION INPUT ;
    USE SIGNAL ;
    PORT
      LAYER M5 ;
        RECT  30 43.116 30.024 43.2 ;
    END
  END head_record[233]
  PIN head_record[234]
    DIRECTION INPUT ;
    USE SIGNAL ;
    PORT
      LAYER M5 ;
        RECT  30.24 43.116 30.264 43.2 ;
    END
  END head_record[234]
  PIN head_record[235]
    DIRECTION INPUT ;
    USE SIGNAL ;
    PORT
      LAYER M5 ;
        RECT  30.528 43.116 30.552 43.2 ;
    END
  END head_record[235]
  PIN head_record[236]
    DIRECTION INPUT ;
    USE SIGNAL ;
    PORT
      LAYER M5 ;
        RECT  30.768 43.116 30.792 43.2 ;
    END
  END head_record[236]
  PIN head_record[237]
    DIRECTION INPUT ;
    USE SIGNAL ;
    PORT
      LAYER M5 ;
        RECT  31.008 43.116 31.032 43.2 ;
    END
  END head_record[237]
  PIN head_record[238]
    DIRECTION INPUT ;
    USE SIGNAL ;
    PORT
      LAYER M5 ;
        RECT  31.296 43.116 31.32 43.2 ;
    END
  END head_record[238]
  PIN head_record[239]
    DIRECTION INPUT ;
    USE SIGNAL ;
    PORT
      LAYER M5 ;
        RECT  31.536 43.116 31.56 43.2 ;
    END
  END head_record[239]
  PIN head_record[23]
    DIRECTION INPUT ;
    USE SIGNAL ;
    PORT
      LAYER M4 ;
        RECT  0 8.784 0.084 8.808 ;
    END
  END head_record[23]
  PIN head_record[240]
    DIRECTION INPUT ;
    USE SIGNAL ;
    PORT
      LAYER M5 ;
        RECT  31.824 43.116 31.848 43.2 ;
    END
  END head_record[240]
  PIN head_record[241]
    DIRECTION INPUT ;
    USE SIGNAL ;
    PORT
      LAYER M5 ;
        RECT  32.064 43.116 32.088 43.2 ;
    END
  END head_record[241]
  PIN head_record[242]
    DIRECTION INPUT ;
    USE SIGNAL ;
    PORT
      LAYER M5 ;
        RECT  32.304 43.116 32.328 43.2 ;
    END
  END head_record[242]
  PIN head_record[243]
    DIRECTION INPUT ;
    USE SIGNAL ;
    PORT
      LAYER M5 ;
        RECT  32.592 43.116 32.616 43.2 ;
    END
  END head_record[243]
  PIN head_record[244]
    DIRECTION INPUT ;
    USE SIGNAL ;
    PORT
      LAYER M5 ;
        RECT  32.832 43.116 32.856 43.2 ;
    END
  END head_record[244]
  PIN head_record[245]
    DIRECTION INPUT ;
    USE SIGNAL ;
    PORT
      LAYER M5 ;
        RECT  33.072 43.116 33.096 43.2 ;
    END
  END head_record[245]
  PIN head_record[246]
    DIRECTION INPUT ;
    USE SIGNAL ;
    PORT
      LAYER M5 ;
        RECT  33.36 43.116 33.384 43.2 ;
    END
  END head_record[246]
  PIN head_record[247]
    DIRECTION INPUT ;
    USE SIGNAL ;
    PORT
      LAYER M5 ;
        RECT  33.6 43.116 33.624 43.2 ;
    END
  END head_record[247]
  PIN head_record[248]
    DIRECTION INPUT ;
    USE SIGNAL ;
    PORT
      LAYER M5 ;
        RECT  33.888 43.116 33.912 43.2 ;
    END
  END head_record[248]
  PIN head_record[249]
    DIRECTION INPUT ;
    USE SIGNAL ;
    PORT
      LAYER M5 ;
        RECT  34.128 43.116 34.152 43.2 ;
    END
  END head_record[249]
  PIN head_record[24]
    DIRECTION INPUT ;
    USE SIGNAL ;
    PORT
      LAYER M4 ;
        RECT  0 9.072 0.084 9.096 ;
    END
  END head_record[24]
  PIN head_record[250]
    DIRECTION INPUT ;
    USE SIGNAL ;
    PORT
      LAYER M5 ;
        RECT  34.368 43.116 34.392 43.2 ;
    END
  END head_record[250]
  PIN head_record[251]
    DIRECTION INPUT ;
    USE SIGNAL ;
    PORT
      LAYER M5 ;
        RECT  34.656 43.116 34.68 43.2 ;
    END
  END head_record[251]
  PIN head_record[252]
    DIRECTION INPUT ;
    USE SIGNAL ;
    PORT
      LAYER M5 ;
        RECT  34.896 43.116 34.92 43.2 ;
    END
  END head_record[252]
  PIN head_record[253]
    DIRECTION INPUT ;
    USE SIGNAL ;
    PORT
      LAYER M5 ;
        RECT  35.184 43.116 35.208 43.2 ;
    END
  END head_record[253]
  PIN head_record[254]
    DIRECTION INPUT ;
    USE SIGNAL ;
    PORT
      LAYER M5 ;
        RECT  35.424 43.116 35.448 43.2 ;
    END
  END head_record[254]
  PIN head_record[255]
    DIRECTION INPUT ;
    USE SIGNAL ;
    PORT
      LAYER M5 ;
        RECT  35.664 43.116 35.688 43.2 ;
    END
  END head_record[255]
  PIN head_record[256]
    DIRECTION INPUT ;
    USE SIGNAL ;
    PORT
      LAYER M5 ;
        RECT  35.952 43.116 35.976 43.2 ;
    END
  END head_record[256]
  PIN head_record[257]
    DIRECTION INPUT ;
    USE SIGNAL ;
    PORT
      LAYER M5 ;
        RECT  36.192 43.116 36.216 43.2 ;
    END
  END head_record[257]
  PIN head_record[258]
    DIRECTION INPUT ;
    USE SIGNAL ;
    PORT
      LAYER M5 ;
        RECT  36.432 43.116 36.456 43.2 ;
    END
  END head_record[258]
  PIN head_record[259]
    DIRECTION INPUT ;
    USE SIGNAL ;
    PORT
      LAYER M5 ;
        RECT  36.72 43.116 36.744 43.2 ;
    END
  END head_record[259]
  PIN head_record[25]
    DIRECTION INPUT ;
    USE SIGNAL ;
    PORT
      LAYER M4 ;
        RECT  0 9.36 0.084 9.384 ;
    END
  END head_record[25]
  PIN head_record[260]
    DIRECTION INPUT ;
    USE SIGNAL ;
    PORT
      LAYER M5 ;
        RECT  36.96 43.116 36.984 43.2 ;
    END
  END head_record[260]
  PIN head_record[261]
    DIRECTION INPUT ;
    USE SIGNAL ;
    PORT
      LAYER M5 ;
        RECT  37.248 43.116 37.272 43.2 ;
    END
  END head_record[261]
  PIN head_record[262]
    DIRECTION INPUT ;
    USE SIGNAL ;
    PORT
      LAYER M5 ;
        RECT  37.488 43.116 37.512 43.2 ;
    END
  END head_record[262]
  PIN head_record[263]
    DIRECTION INPUT ;
    USE SIGNAL ;
    PORT
      LAYER M5 ;
        RECT  37.728 43.116 37.752 43.2 ;
    END
  END head_record[263]
  PIN head_record[264]
    DIRECTION INPUT ;
    USE SIGNAL ;
    PORT
      LAYER M5 ;
        RECT  38.016 43.116 38.04 43.2 ;
    END
  END head_record[264]
  PIN head_record[265]
    DIRECTION INPUT ;
    USE SIGNAL ;
    PORT
      LAYER M5 ;
        RECT  38.256 43.116 38.28 43.2 ;
    END
  END head_record[265]
  PIN head_record[266]
    DIRECTION INPUT ;
    USE SIGNAL ;
    PORT
      LAYER M5 ;
        RECT  38.544 43.116 38.568 43.2 ;
    END
  END head_record[266]
  PIN head_record[267]
    DIRECTION INPUT ;
    USE SIGNAL ;
    PORT
      LAYER M5 ;
        RECT  38.784 43.116 38.808 43.2 ;
    END
  END head_record[267]
  PIN head_record[268]
    DIRECTION INPUT ;
    USE SIGNAL ;
    PORT
      LAYER M5 ;
        RECT  39.024 43.116 39.048 43.2 ;
    END
  END head_record[268]
  PIN head_record[269]
    DIRECTION INPUT ;
    USE SIGNAL ;
    PORT
      LAYER M5 ;
        RECT  39.312 43.116 39.336 43.2 ;
    END
  END head_record[269]
  PIN head_record[26]
    DIRECTION INPUT ;
    USE SIGNAL ;
    PORT
      LAYER M4 ;
        RECT  0 9.648 0.084 9.672 ;
    END
  END head_record[26]
  PIN head_record[270]
    DIRECTION INPUT ;
    USE SIGNAL ;
    PORT
      LAYER M5 ;
        RECT  39.552 43.116 39.576 43.2 ;
    END
  END head_record[270]
  PIN head_record[271]
    DIRECTION INPUT ;
    USE SIGNAL ;
    PORT
      LAYER M5 ;
        RECT  39.84 43.116 39.864 43.2 ;
    END
  END head_record[271]
  PIN head_record[272]
    DIRECTION INPUT ;
    USE SIGNAL ;
    PORT
      LAYER M5 ;
        RECT  40.08 43.116 40.104 43.2 ;
    END
  END head_record[272]
  PIN head_record[273]
    DIRECTION INPUT ;
    USE SIGNAL ;
    PORT
      LAYER M5 ;
        RECT  40.32 43.116 40.344 43.2 ;
    END
  END head_record[273]
  PIN head_record[274]
    DIRECTION INPUT ;
    USE SIGNAL ;
    PORT
      LAYER M5 ;
        RECT  40.608 43.116 40.632 43.2 ;
    END
  END head_record[274]
  PIN head_record[275]
    DIRECTION INPUT ;
    USE SIGNAL ;
    PORT
      LAYER M5 ;
        RECT  40.848 43.116 40.872 43.2 ;
    END
  END head_record[275]
  PIN head_record[276]
    DIRECTION INPUT ;
    USE SIGNAL ;
    PORT
      LAYER M5 ;
        RECT  2.352 0 2.376 0.084 ;
    END
  END head_record[276]
  PIN head_record[277]
    DIRECTION INPUT ;
    USE SIGNAL ;
    PORT
      LAYER M5 ;
        RECT  2.64 0 2.664 0.084 ;
    END
  END head_record[277]
  PIN head_record[278]
    DIRECTION INPUT ;
    USE SIGNAL ;
    PORT
      LAYER M5 ;
        RECT  2.88 0 2.904 0.084 ;
    END
  END head_record[278]
  PIN head_record[279]
    DIRECTION INPUT ;
    USE SIGNAL ;
    PORT
      LAYER M5 ;
        RECT  3.168 0 3.192 0.084 ;
    END
  END head_record[279]
  PIN head_record[27]
    DIRECTION INPUT ;
    USE SIGNAL ;
    PORT
      LAYER M4 ;
        RECT  0 9.936 0.084 9.96 ;
    END
  END head_record[27]
  PIN head_record[280]
    DIRECTION INPUT ;
    USE SIGNAL ;
    PORT
      LAYER M5 ;
        RECT  3.456 0 3.48 0.084 ;
    END
  END head_record[280]
  PIN head_record[281]
    DIRECTION INPUT ;
    USE SIGNAL ;
    PORT
      LAYER M5 ;
        RECT  3.744 0 3.768 0.084 ;
    END
  END head_record[281]
  PIN head_record[282]
    DIRECTION INPUT ;
    USE SIGNAL ;
    PORT
      LAYER M5 ;
        RECT  4.032 0 4.056 0.084 ;
    END
  END head_record[282]
  PIN head_record[283]
    DIRECTION INPUT ;
    USE SIGNAL ;
    PORT
      LAYER M5 ;
        RECT  4.32 0 4.344 0.084 ;
    END
  END head_record[283]
  PIN head_record[284]
    DIRECTION INPUT ;
    USE SIGNAL ;
    PORT
      LAYER M5 ;
        RECT  4.608 0 4.632 0.084 ;
    END
  END head_record[284]
  PIN head_record[285]
    DIRECTION INPUT ;
    USE SIGNAL ;
    PORT
      LAYER M5 ;
        RECT  4.848 0 4.872 0.084 ;
    END
  END head_record[285]
  PIN head_record[286]
    DIRECTION INPUT ;
    USE SIGNAL ;
    PORT
      LAYER M5 ;
        RECT  5.136 0 5.16 0.084 ;
    END
  END head_record[286]
  PIN head_record[287]
    DIRECTION INPUT ;
    USE SIGNAL ;
    PORT
      LAYER M5 ;
        RECT  5.424 0 5.448 0.084 ;
    END
  END head_record[287]
  PIN head_record[288]
    DIRECTION INPUT ;
    USE SIGNAL ;
    PORT
      LAYER M5 ;
        RECT  5.712 0 5.736 0.084 ;
    END
  END head_record[288]
  PIN head_record[289]
    DIRECTION INPUT ;
    USE SIGNAL ;
    PORT
      LAYER M5 ;
        RECT  6 0 6.024 0.084 ;
    END
  END head_record[289]
  PIN head_record[28]
    DIRECTION INPUT ;
    USE SIGNAL ;
    PORT
      LAYER M4 ;
        RECT  0 10.224 0.084 10.248 ;
    END
  END head_record[28]
  PIN head_record[290]
    DIRECTION INPUT ;
    USE SIGNAL ;
    PORT
      LAYER M5 ;
        RECT  6.288 0 6.312 0.084 ;
    END
  END head_record[290]
  PIN head_record[291]
    DIRECTION INPUT ;
    USE SIGNAL ;
    PORT
      LAYER M5 ;
        RECT  6.576 0 6.6 0.084 ;
    END
  END head_record[291]
  PIN head_record[292]
    DIRECTION INPUT ;
    USE SIGNAL ;
    PORT
      LAYER M5 ;
        RECT  6.816 0 6.84 0.084 ;
    END
  END head_record[292]
  PIN head_record[293]
    DIRECTION INPUT ;
    USE SIGNAL ;
    PORT
      LAYER M5 ;
        RECT  7.104 0 7.128 0.084 ;
    END
  END head_record[293]
  PIN head_record[294]
    DIRECTION INPUT ;
    USE SIGNAL ;
    PORT
      LAYER M5 ;
        RECT  7.392 0 7.416 0.084 ;
    END
  END head_record[294]
  PIN head_record[295]
    DIRECTION INPUT ;
    USE SIGNAL ;
    PORT
      LAYER M5 ;
        RECT  7.68 0 7.704 0.084 ;
    END
  END head_record[295]
  PIN head_record[296]
    DIRECTION INPUT ;
    USE SIGNAL ;
    PORT
      LAYER M5 ;
        RECT  7.968 0 7.992 0.084 ;
    END
  END head_record[296]
  PIN head_record[297]
    DIRECTION INPUT ;
    USE SIGNAL ;
    PORT
      LAYER M5 ;
        RECT  8.256 0 8.28 0.084 ;
    END
  END head_record[297]
  PIN head_record[298]
    DIRECTION INPUT ;
    USE SIGNAL ;
    PORT
      LAYER M5 ;
        RECT  8.496 0 8.52 0.084 ;
    END
  END head_record[298]
  PIN head_record[299]
    DIRECTION INPUT ;
    USE SIGNAL ;
    PORT
      LAYER M5 ;
        RECT  8.784 0 8.808 0.084 ;
    END
  END head_record[299]
  PIN head_record[29]
    DIRECTION INPUT ;
    USE SIGNAL ;
    PORT
      LAYER M4 ;
        RECT  0 10.464 0.084 10.488 ;
    END
  END head_record[29]
  PIN head_record[2]
    DIRECTION INPUT ;
    USE SIGNAL ;
    PORT
      LAYER M4 ;
        RECT  0 2.88 0.084 2.904 ;
    END
  END head_record[2]
  PIN head_record[300]
    DIRECTION INPUT ;
    USE SIGNAL ;
    PORT
      LAYER M5 ;
        RECT  9.072 0 9.096 0.084 ;
    END
  END head_record[300]
  PIN head_record[301]
    DIRECTION INPUT ;
    USE SIGNAL ;
    PORT
      LAYER M5 ;
        RECT  9.36 0 9.384 0.084 ;
    END
  END head_record[301]
  PIN head_record[302]
    DIRECTION INPUT ;
    USE SIGNAL ;
    PORT
      LAYER M5 ;
        RECT  9.648 0 9.672 0.084 ;
    END
  END head_record[302]
  PIN head_record[303]
    DIRECTION INPUT ;
    USE SIGNAL ;
    PORT
      LAYER M5 ;
        RECT  9.936 0 9.96 0.084 ;
    END
  END head_record[303]
  PIN head_record[304]
    DIRECTION INPUT ;
    USE SIGNAL ;
    PORT
      LAYER M5 ;
        RECT  10.224 0 10.248 0.084 ;
    END
  END head_record[304]
  PIN head_record[305]
    DIRECTION INPUT ;
    USE SIGNAL ;
    PORT
      LAYER M5 ;
        RECT  10.464 0 10.488 0.084 ;
    END
  END head_record[305]
  PIN head_record[306]
    DIRECTION INPUT ;
    USE SIGNAL ;
    PORT
      LAYER M5 ;
        RECT  10.752 0 10.776 0.084 ;
    END
  END head_record[306]
  PIN head_record[307]
    DIRECTION INPUT ;
    USE SIGNAL ;
    PORT
      LAYER M5 ;
        RECT  11.04 0 11.064 0.084 ;
    END
  END head_record[307]
  PIN head_record[308]
    DIRECTION INPUT ;
    USE SIGNAL ;
    PORT
      LAYER M5 ;
        RECT  11.328 0 11.352 0.084 ;
    END
  END head_record[308]
  PIN head_record[309]
    DIRECTION INPUT ;
    USE SIGNAL ;
    PORT
      LAYER M5 ;
        RECT  11.616 0 11.64 0.084 ;
    END
  END head_record[309]
  PIN head_record[30]
    DIRECTION INPUT ;
    USE SIGNAL ;
    PORT
      LAYER M4 ;
        RECT  0 10.752 0.084 10.776 ;
    END
  END head_record[30]
  PIN head_record[310]
    DIRECTION INPUT ;
    USE SIGNAL ;
    PORT
      LAYER M5 ;
        RECT  11.904 0 11.928 0.084 ;
    END
  END head_record[310]
  PIN head_record[311]
    DIRECTION INPUT ;
    USE SIGNAL ;
    PORT
      LAYER M5 ;
        RECT  12.192 0 12.216 0.084 ;
    END
  END head_record[311]
  PIN head_record[312]
    DIRECTION INPUT ;
    USE SIGNAL ;
    PORT
      LAYER M5 ;
        RECT  12.432 0 12.456 0.084 ;
    END
  END head_record[312]
  PIN head_record[313]
    DIRECTION INPUT ;
    USE SIGNAL ;
    PORT
      LAYER M5 ;
        RECT  12.72 0 12.744 0.084 ;
    END
  END head_record[313]
  PIN head_record[314]
    DIRECTION INPUT ;
    USE SIGNAL ;
    PORT
      LAYER M5 ;
        RECT  13.008 0 13.032 0.084 ;
    END
  END head_record[314]
  PIN head_record[315]
    DIRECTION INPUT ;
    USE SIGNAL ;
    PORT
      LAYER M5 ;
        RECT  13.296 0 13.32 0.084 ;
    END
  END head_record[315]
  PIN head_record[316]
    DIRECTION INPUT ;
    USE SIGNAL ;
    PORT
      LAYER M5 ;
        RECT  13.584 0 13.608 0.084 ;
    END
  END head_record[316]
  PIN head_record[317]
    DIRECTION INPUT ;
    USE SIGNAL ;
    PORT
      LAYER M5 ;
        RECT  13.872 0 13.896 0.084 ;
    END
  END head_record[317]
  PIN head_record[318]
    DIRECTION INPUT ;
    USE SIGNAL ;
    PORT
      LAYER M5 ;
        RECT  14.16 0 14.184 0.084 ;
    END
  END head_record[318]
  PIN head_record[319]
    DIRECTION INPUT ;
    USE SIGNAL ;
    PORT
      LAYER M5 ;
        RECT  14.4 0 14.424 0.084 ;
    END
  END head_record[319]
  PIN head_record[31]
    DIRECTION INPUT ;
    USE SIGNAL ;
    PORT
      LAYER M4 ;
        RECT  0 11.04 0.084 11.064 ;
    END
  END head_record[31]
  PIN head_record[320]
    DIRECTION INPUT ;
    USE SIGNAL ;
    PORT
      LAYER M5 ;
        RECT  14.688 0 14.712 0.084 ;
    END
  END head_record[320]
  PIN head_record[321]
    DIRECTION INPUT ;
    USE SIGNAL ;
    PORT
      LAYER M5 ;
        RECT  14.976 0 15 0.084 ;
    END
  END head_record[321]
  PIN head_record[322]
    DIRECTION INPUT ;
    USE SIGNAL ;
    PORT
      LAYER M5 ;
        RECT  15.264 0 15.288 0.084 ;
    END
  END head_record[322]
  PIN head_record[323]
    DIRECTION INPUT ;
    USE SIGNAL ;
    PORT
      LAYER M5 ;
        RECT  15.552 0 15.576 0.084 ;
    END
  END head_record[323]
  PIN head_record[324]
    DIRECTION INPUT ;
    USE SIGNAL ;
    PORT
      LAYER M5 ;
        RECT  15.84 0 15.864 0.084 ;
    END
  END head_record[324]
  PIN head_record[325]
    DIRECTION INPUT ;
    USE SIGNAL ;
    PORT
      LAYER M5 ;
        RECT  16.128 0 16.152 0.084 ;
    END
  END head_record[325]
  PIN head_record[326]
    DIRECTION INPUT ;
    USE SIGNAL ;
    PORT
      LAYER M5 ;
        RECT  16.368 0 16.392 0.084 ;
    END
  END head_record[326]
  PIN head_record[327]
    DIRECTION INPUT ;
    USE SIGNAL ;
    PORT
      LAYER M5 ;
        RECT  16.656 0 16.68 0.084 ;
    END
  END head_record[327]
  PIN head_record[328]
    DIRECTION INPUT ;
    USE SIGNAL ;
    PORT
      LAYER M5 ;
        RECT  16.944 0 16.968 0.084 ;
    END
  END head_record[328]
  PIN head_record[329]
    DIRECTION INPUT ;
    USE SIGNAL ;
    PORT
      LAYER M5 ;
        RECT  17.232 0 17.256 0.084 ;
    END
  END head_record[329]
  PIN head_record[32]
    DIRECTION INPUT ;
    USE SIGNAL ;
    PORT
      LAYER M4 ;
        RECT  0 11.328 0.084 11.352 ;
    END
  END head_record[32]
  PIN head_record[330]
    DIRECTION INPUT ;
    USE SIGNAL ;
    PORT
      LAYER M5 ;
        RECT  17.52 0 17.544 0.084 ;
    END
  END head_record[330]
  PIN head_record[331]
    DIRECTION INPUT ;
    USE SIGNAL ;
    PORT
      LAYER M5 ;
        RECT  17.808 0 17.832 0.084 ;
    END
  END head_record[331]
  PIN head_record[332]
    DIRECTION INPUT ;
    USE SIGNAL ;
    PORT
      LAYER M5 ;
        RECT  18.096 0 18.12 0.084 ;
    END
  END head_record[332]
  PIN head_record[333]
    DIRECTION INPUT ;
    USE SIGNAL ;
    PORT
      LAYER M5 ;
        RECT  18.336 0 18.36 0.084 ;
    END
  END head_record[333]
  PIN head_record[334]
    DIRECTION INPUT ;
    USE SIGNAL ;
    PORT
      LAYER M5 ;
        RECT  18.624 0 18.648 0.084 ;
    END
  END head_record[334]
  PIN head_record[335]
    DIRECTION INPUT ;
    USE SIGNAL ;
    PORT
      LAYER M5 ;
        RECT  18.912 0 18.936 0.084 ;
    END
  END head_record[335]
  PIN head_record[336]
    DIRECTION INPUT ;
    USE SIGNAL ;
    PORT
      LAYER M5 ;
        RECT  19.2 0 19.224 0.084 ;
    END
  END head_record[336]
  PIN head_record[337]
    DIRECTION INPUT ;
    USE SIGNAL ;
    PORT
      LAYER M5 ;
        RECT  19.488 0 19.512 0.084 ;
    END
  END head_record[337]
  PIN head_record[338]
    DIRECTION INPUT ;
    USE SIGNAL ;
    PORT
      LAYER M5 ;
        RECT  19.776 0 19.8 0.084 ;
    END
  END head_record[338]
  PIN head_record[339]
    DIRECTION INPUT ;
    USE SIGNAL ;
    PORT
      LAYER M5 ;
        RECT  20.064 0 20.088 0.084 ;
    END
  END head_record[339]
  PIN head_record[33]
    DIRECTION INPUT ;
    USE SIGNAL ;
    PORT
      LAYER M4 ;
        RECT  0 11.616 0.084 11.64 ;
    END
  END head_record[33]
  PIN head_record[340]
    DIRECTION INPUT ;
    USE SIGNAL ;
    PORT
      LAYER M5 ;
        RECT  20.304 0 20.328 0.084 ;
    END
  END head_record[340]
  PIN head_record[341]
    DIRECTION INPUT ;
    USE SIGNAL ;
    PORT
      LAYER M5 ;
        RECT  20.592 0 20.616 0.084 ;
    END
  END head_record[341]
  PIN head_record[342]
    DIRECTION INPUT ;
    USE SIGNAL ;
    PORT
      LAYER M5 ;
        RECT  20.88 0 20.904 0.084 ;
    END
  END head_record[342]
  PIN head_record[343]
    DIRECTION INPUT ;
    USE SIGNAL ;
    PORT
      LAYER M5 ;
        RECT  21.168 0 21.192 0.084 ;
    END
  END head_record[343]
  PIN head_record[344]
    DIRECTION INPUT ;
    USE SIGNAL ;
    PORT
      LAYER M5 ;
        RECT  21.456 0 21.48 0.084 ;
    END
  END head_record[344]
  PIN head_record[345]
    DIRECTION INPUT ;
    USE SIGNAL ;
    PORT
      LAYER M5 ;
        RECT  21.744 0 21.768 0.084 ;
    END
  END head_record[345]
  PIN head_record[346]
    DIRECTION INPUT ;
    USE SIGNAL ;
    PORT
      LAYER M5 ;
        RECT  22.032 0 22.056 0.084 ;
    END
  END head_record[346]
  PIN head_record[347]
    DIRECTION INPUT ;
    USE SIGNAL ;
    PORT
      LAYER M5 ;
        RECT  22.272 0 22.296 0.084 ;
    END
  END head_record[347]
  PIN head_record[348]
    DIRECTION INPUT ;
    USE SIGNAL ;
    PORT
      LAYER M5 ;
        RECT  22.56 0 22.584 0.084 ;
    END
  END head_record[348]
  PIN head_record[349]
    DIRECTION INPUT ;
    USE SIGNAL ;
    PORT
      LAYER M5 ;
        RECT  22.848 0 22.872 0.084 ;
    END
  END head_record[349]
  PIN head_record[34]
    DIRECTION INPUT ;
    USE SIGNAL ;
    PORT
      LAYER M4 ;
        RECT  0 11.904 0.084 11.928 ;
    END
  END head_record[34]
  PIN head_record[350]
    DIRECTION INPUT ;
    USE SIGNAL ;
    PORT
      LAYER M5 ;
        RECT  23.136 0 23.16 0.084 ;
    END
  END head_record[350]
  PIN head_record[351]
    DIRECTION INPUT ;
    USE SIGNAL ;
    PORT
      LAYER M5 ;
        RECT  23.424 0 23.448 0.084 ;
    END
  END head_record[351]
  PIN head_record[352]
    DIRECTION INPUT ;
    USE SIGNAL ;
    PORT
      LAYER M5 ;
        RECT  23.712 0 23.736 0.084 ;
    END
  END head_record[352]
  PIN head_record[353]
    DIRECTION INPUT ;
    USE SIGNAL ;
    PORT
      LAYER M5 ;
        RECT  24 0 24.024 0.084 ;
    END
  END head_record[353]
  PIN head_record[354]
    DIRECTION INPUT ;
    USE SIGNAL ;
    PORT
      LAYER M5 ;
        RECT  24.24 0 24.264 0.084 ;
    END
  END head_record[354]
  PIN head_record[355]
    DIRECTION INPUT ;
    USE SIGNAL ;
    PORT
      LAYER M5 ;
        RECT  24.528 0 24.552 0.084 ;
    END
  END head_record[355]
  PIN head_record[356]
    DIRECTION INPUT ;
    USE SIGNAL ;
    PORT
      LAYER M5 ;
        RECT  24.816 0 24.84 0.084 ;
    END
  END head_record[356]
  PIN head_record[357]
    DIRECTION INPUT ;
    USE SIGNAL ;
    PORT
      LAYER M5 ;
        RECT  25.104 0 25.128 0.084 ;
    END
  END head_record[357]
  PIN head_record[358]
    DIRECTION INPUT ;
    USE SIGNAL ;
    PORT
      LAYER M5 ;
        RECT  25.392 0 25.416 0.084 ;
    END
  END head_record[358]
  PIN head_record[359]
    DIRECTION INPUT ;
    USE SIGNAL ;
    PORT
      LAYER M5 ;
        RECT  25.68 0 25.704 0.084 ;
    END
  END head_record[359]
  PIN head_record[35]
    DIRECTION INPUT ;
    USE SIGNAL ;
    PORT
      LAYER M4 ;
        RECT  0 12.192 0.084 12.216 ;
    END
  END head_record[35]
  PIN head_record[360]
    DIRECTION INPUT ;
    USE SIGNAL ;
    PORT
      LAYER M5 ;
        RECT  25.968 0 25.992 0.084 ;
    END
  END head_record[360]
  PIN head_record[361]
    DIRECTION INPUT ;
    USE SIGNAL ;
    PORT
      LAYER M5 ;
        RECT  26.208 0 26.232 0.084 ;
    END
  END head_record[361]
  PIN head_record[362]
    DIRECTION INPUT ;
    USE SIGNAL ;
    PORT
      LAYER M5 ;
        RECT  26.496 0 26.52 0.084 ;
    END
  END head_record[362]
  PIN head_record[363]
    DIRECTION INPUT ;
    USE SIGNAL ;
    PORT
      LAYER M5 ;
        RECT  26.784 0 26.808 0.084 ;
    END
  END head_record[363]
  PIN head_record[364]
    DIRECTION INPUT ;
    USE SIGNAL ;
    PORT
      LAYER M5 ;
        RECT  27.072 0 27.096 0.084 ;
    END
  END head_record[364]
  PIN head_record[365]
    DIRECTION INPUT ;
    USE SIGNAL ;
    PORT
      LAYER M5 ;
        RECT  27.36 0 27.384 0.084 ;
    END
  END head_record[365]
  PIN head_record[366]
    DIRECTION INPUT ;
    USE SIGNAL ;
    PORT
      LAYER M5 ;
        RECT  27.648 0 27.672 0.084 ;
    END
  END head_record[366]
  PIN head_record[367]
    DIRECTION INPUT ;
    USE SIGNAL ;
    PORT
      LAYER M5 ;
        RECT  27.888 0 27.912 0.084 ;
    END
  END head_record[367]
  PIN head_record[368]
    DIRECTION INPUT ;
    USE SIGNAL ;
    PORT
      LAYER M5 ;
        RECT  28.176 0 28.2 0.084 ;
    END
  END head_record[368]
  PIN head_record[369]
    DIRECTION INPUT ;
    USE SIGNAL ;
    PORT
      LAYER M5 ;
        RECT  28.464 0 28.488 0.084 ;
    END
  END head_record[369]
  PIN head_record[36]
    DIRECTION INPUT ;
    USE SIGNAL ;
    PORT
      LAYER M4 ;
        RECT  0 12.432 0.084 12.456 ;
    END
  END head_record[36]
  PIN head_record[370]
    DIRECTION INPUT ;
    USE SIGNAL ;
    PORT
      LAYER M5 ;
        RECT  28.752 0 28.776 0.084 ;
    END
  END head_record[370]
  PIN head_record[371]
    DIRECTION INPUT ;
    USE SIGNAL ;
    PORT
      LAYER M5 ;
        RECT  29.04 0 29.064 0.084 ;
    END
  END head_record[371]
  PIN head_record[372]
    DIRECTION INPUT ;
    USE SIGNAL ;
    PORT
      LAYER M5 ;
        RECT  29.328 0 29.352 0.084 ;
    END
  END head_record[372]
  PIN head_record[373]
    DIRECTION INPUT ;
    USE SIGNAL ;
    PORT
      LAYER M5 ;
        RECT  29.616 0 29.64 0.084 ;
    END
  END head_record[373]
  PIN head_record[374]
    DIRECTION INPUT ;
    USE SIGNAL ;
    PORT
      LAYER M5 ;
        RECT  29.856 0 29.88 0.084 ;
    END
  END head_record[374]
  PIN head_record[375]
    DIRECTION INPUT ;
    USE SIGNAL ;
    PORT
      LAYER M5 ;
        RECT  30.144 0 30.168 0.084 ;
    END
  END head_record[375]
  PIN head_record[376]
    DIRECTION INPUT ;
    USE SIGNAL ;
    PORT
      LAYER M5 ;
        RECT  30.432 0 30.456 0.084 ;
    END
  END head_record[376]
  PIN head_record[377]
    DIRECTION INPUT ;
    USE SIGNAL ;
    PORT
      LAYER M5 ;
        RECT  30.72 0 30.744 0.084 ;
    END
  END head_record[377]
  PIN head_record[378]
    DIRECTION INPUT ;
    USE SIGNAL ;
    PORT
      LAYER M5 ;
        RECT  31.008 0 31.032 0.084 ;
    END
  END head_record[378]
  PIN head_record[379]
    DIRECTION INPUT ;
    USE SIGNAL ;
    PORT
      LAYER M5 ;
        RECT  31.296 0 31.32 0.084 ;
    END
  END head_record[379]
  PIN head_record[37]
    DIRECTION INPUT ;
    USE SIGNAL ;
    PORT
      LAYER M4 ;
        RECT  0 12.72 0.084 12.744 ;
    END
  END head_record[37]
  PIN head_record[380]
    DIRECTION INPUT ;
    USE SIGNAL ;
    PORT
      LAYER M5 ;
        RECT  31.584 0 31.608 0.084 ;
    END
  END head_record[380]
  PIN head_record[381]
    DIRECTION INPUT ;
    USE SIGNAL ;
    PORT
      LAYER M5 ;
        RECT  31.824 0 31.848 0.084 ;
    END
  END head_record[381]
  PIN head_record[382]
    DIRECTION INPUT ;
    USE SIGNAL ;
    PORT
      LAYER M5 ;
        RECT  32.112 0 32.136 0.084 ;
    END
  END head_record[382]
  PIN head_record[383]
    DIRECTION INPUT ;
    USE SIGNAL ;
    PORT
      LAYER M5 ;
        RECT  32.4 0 32.424 0.084 ;
    END
  END head_record[383]
  PIN head_record[384]
    DIRECTION INPUT ;
    USE SIGNAL ;
    PORT
      LAYER M5 ;
        RECT  32.688 0 32.712 0.084 ;
    END
  END head_record[384]
  PIN head_record[385]
    DIRECTION INPUT ;
    USE SIGNAL ;
    PORT
      LAYER M5 ;
        RECT  32.976 0 33 0.084 ;
    END
  END head_record[385]
  PIN head_record[386]
    DIRECTION INPUT ;
    USE SIGNAL ;
    PORT
      LAYER M5 ;
        RECT  33.264 0 33.288 0.084 ;
    END
  END head_record[386]
  PIN head_record[387]
    DIRECTION INPUT ;
    USE SIGNAL ;
    PORT
      LAYER M5 ;
        RECT  33.552 0 33.576 0.084 ;
    END
  END head_record[387]
  PIN head_record[388]
    DIRECTION INPUT ;
    USE SIGNAL ;
    PORT
      LAYER M5 ;
        RECT  33.792 0 33.816 0.084 ;
    END
  END head_record[388]
  PIN head_record[389]
    DIRECTION INPUT ;
    USE SIGNAL ;
    PORT
      LAYER M5 ;
        RECT  34.08 0 34.104 0.084 ;
    END
  END head_record[389]
  PIN head_record[38]
    DIRECTION INPUT ;
    USE SIGNAL ;
    PORT
      LAYER M4 ;
        RECT  0 13.008 0.084 13.032 ;
    END
  END head_record[38]
  PIN head_record[390]
    DIRECTION INPUT ;
    USE SIGNAL ;
    PORT
      LAYER M5 ;
        RECT  34.368 0 34.392 0.084 ;
    END
  END head_record[390]
  PIN head_record[391]
    DIRECTION INPUT ;
    USE SIGNAL ;
    PORT
      LAYER M5 ;
        RECT  34.656 0 34.68 0.084 ;
    END
  END head_record[391]
  PIN head_record[392]
    DIRECTION INPUT ;
    USE SIGNAL ;
    PORT
      LAYER M5 ;
        RECT  34.944 0 34.968 0.084 ;
    END
  END head_record[392]
  PIN head_record[393]
    DIRECTION INPUT ;
    USE SIGNAL ;
    PORT
      LAYER M5 ;
        RECT  35.232 0 35.256 0.084 ;
    END
  END head_record[393]
  PIN head_record[394]
    DIRECTION INPUT ;
    USE SIGNAL ;
    PORT
      LAYER M5 ;
        RECT  35.52 0 35.544 0.084 ;
    END
  END head_record[394]
  PIN head_record[395]
    DIRECTION INPUT ;
    USE SIGNAL ;
    PORT
      LAYER M5 ;
        RECT  35.76 0 35.784 0.084 ;
    END
  END head_record[395]
  PIN head_record[396]
    DIRECTION INPUT ;
    USE SIGNAL ;
    PORT
      LAYER M5 ;
        RECT  36.048 0 36.072 0.084 ;
    END
  END head_record[396]
  PIN head_record[397]
    DIRECTION INPUT ;
    USE SIGNAL ;
    PORT
      LAYER M5 ;
        RECT  36.336 0 36.36 0.084 ;
    END
  END head_record[397]
  PIN head_record[398]
    DIRECTION INPUT ;
    USE SIGNAL ;
    PORT
      LAYER M5 ;
        RECT  36.624 0 36.648 0.084 ;
    END
  END head_record[398]
  PIN head_record[399]
    DIRECTION INPUT ;
    USE SIGNAL ;
    PORT
      LAYER M5 ;
        RECT  36.912 0 36.936 0.084 ;
    END
  END head_record[399]
  PIN head_record[39]
    DIRECTION INPUT ;
    USE SIGNAL ;
    PORT
      LAYER M4 ;
        RECT  0 13.296 0.084 13.32 ;
    END
  END head_record[39]
  PIN head_record[3]
    DIRECTION INPUT ;
    USE SIGNAL ;
    PORT
      LAYER M4 ;
        RECT  0 3.168 0.084 3.192 ;
    END
  END head_record[3]
  PIN head_record[400]
    DIRECTION INPUT ;
    USE SIGNAL ;
    PORT
      LAYER M5 ;
        RECT  37.2 0 37.224 0.084 ;
    END
  END head_record[400]
  PIN head_record[401]
    DIRECTION INPUT ;
    USE SIGNAL ;
    PORT
      LAYER M5 ;
        RECT  37.488 0 37.512 0.084 ;
    END
  END head_record[401]
  PIN head_record[402]
    DIRECTION INPUT ;
    USE SIGNAL ;
    PORT
      LAYER M5 ;
        RECT  37.728 0 37.752 0.084 ;
    END
  END head_record[402]
  PIN head_record[403]
    DIRECTION INPUT ;
    USE SIGNAL ;
    PORT
      LAYER M5 ;
        RECT  38.016 0 38.04 0.084 ;
    END
  END head_record[403]
  PIN head_record[404]
    DIRECTION INPUT ;
    USE SIGNAL ;
    PORT
      LAYER M5 ;
        RECT  38.304 0 38.328 0.084 ;
    END
  END head_record[404]
  PIN head_record[405]
    DIRECTION INPUT ;
    USE SIGNAL ;
    PORT
      LAYER M5 ;
        RECT  38.592 0 38.616 0.084 ;
    END
  END head_record[405]
  PIN head_record[406]
    DIRECTION INPUT ;
    USE SIGNAL ;
    PORT
      LAYER M5 ;
        RECT  38.88 0 38.904 0.084 ;
    END
  END head_record[406]
  PIN head_record[407]
    DIRECTION INPUT ;
    USE SIGNAL ;
    PORT
      LAYER M5 ;
        RECT  39.168 0 39.192 0.084 ;
    END
  END head_record[407]
  PIN head_record[408]
    DIRECTION INPUT ;
    USE SIGNAL ;
    PORT
      LAYER M5 ;
        RECT  39.456 0 39.48 0.084 ;
    END
  END head_record[408]
  PIN head_record[409]
    DIRECTION INPUT ;
    USE SIGNAL ;
    PORT
      LAYER M5 ;
        RECT  39.696 0 39.72 0.084 ;
    END
  END head_record[409]
  PIN head_record[40]
    DIRECTION INPUT ;
    USE SIGNAL ;
    PORT
      LAYER M4 ;
        RECT  0 13.584 0.084 13.608 ;
    END
  END head_record[40]
  PIN head_record[410]
    DIRECTION INPUT ;
    USE SIGNAL ;
    PORT
      LAYER M5 ;
        RECT  39.984 0 40.008 0.084 ;
    END
  END head_record[410]
  PIN head_record[411]
    DIRECTION INPUT ;
    USE SIGNAL ;
    PORT
      LAYER M5 ;
        RECT  40.272 0 40.296 0.084 ;
    END
  END head_record[411]
  PIN head_record[412]
    DIRECTION INPUT ;
    USE SIGNAL ;
    PORT
      LAYER M5 ;
        RECT  40.56 0 40.584 0.084 ;
    END
  END head_record[412]
  PIN head_record[413]
    DIRECTION INPUT ;
    USE SIGNAL ;
    PORT
      LAYER M5 ;
        RECT  40.848 0 40.872 0.084 ;
    END
  END head_record[413]
  PIN head_record[414]
    DIRECTION INPUT ;
    USE SIGNAL ;
    PORT
      LAYER M4 ;
        RECT  43.116 2.304 43.2 2.328 ;
    END
  END head_record[414]
  PIN head_record[415]
    DIRECTION INPUT ;
    USE SIGNAL ;
    PORT
      LAYER M4 ;
        RECT  43.116 2.496 43.2 2.52 ;
    END
  END head_record[415]
  PIN head_record[416]
    DIRECTION INPUT ;
    USE SIGNAL ;
    PORT
      LAYER M4 ;
        RECT  43.116 2.688 43.2 2.712 ;
    END
  END head_record[416]
  PIN head_record[417]
    DIRECTION INPUT ;
    USE SIGNAL ;
    PORT
      LAYER M4 ;
        RECT  43.116 2.88 43.2 2.904 ;
    END
  END head_record[417]
  PIN head_record[418]
    DIRECTION INPUT ;
    USE SIGNAL ;
    PORT
      LAYER M4 ;
        RECT  43.116 3.072 43.2 3.096 ;
    END
  END head_record[418]
  PIN head_record[419]
    DIRECTION INPUT ;
    USE SIGNAL ;
    PORT
      LAYER M4 ;
        RECT  43.116 3.264 43.2 3.288 ;
    END
  END head_record[419]
  PIN head_record[41]
    DIRECTION INPUT ;
    USE SIGNAL ;
    PORT
      LAYER M4 ;
        RECT  0 13.872 0.084 13.896 ;
    END
  END head_record[41]
  PIN head_record[420]
    DIRECTION INPUT ;
    USE SIGNAL ;
    PORT
      LAYER M4 ;
        RECT  43.116 3.456 43.2 3.48 ;
    END
  END head_record[420]
  PIN head_record[421]
    DIRECTION INPUT ;
    USE SIGNAL ;
    PORT
      LAYER M4 ;
        RECT  43.116 3.648 43.2 3.672 ;
    END
  END head_record[421]
  PIN head_record[422]
    DIRECTION INPUT ;
    USE SIGNAL ;
    PORT
      LAYER M4 ;
        RECT  43.116 3.84 43.2 3.864 ;
    END
  END head_record[422]
  PIN head_record[423]
    DIRECTION INPUT ;
    USE SIGNAL ;
    PORT
      LAYER M4 ;
        RECT  43.116 4.032 43.2 4.056 ;
    END
  END head_record[423]
  PIN head_record[424]
    DIRECTION INPUT ;
    USE SIGNAL ;
    PORT
      LAYER M4 ;
        RECT  43.116 4.224 43.2 4.248 ;
    END
  END head_record[424]
  PIN head_record[425]
    DIRECTION INPUT ;
    USE SIGNAL ;
    PORT
      LAYER M4 ;
        RECT  43.116 4.416 43.2 4.44 ;
    END
  END head_record[425]
  PIN head_record[426]
    DIRECTION INPUT ;
    USE SIGNAL ;
    PORT
      LAYER M4 ;
        RECT  43.116 4.608 43.2 4.632 ;
    END
  END head_record[426]
  PIN head_record[427]
    DIRECTION INPUT ;
    USE SIGNAL ;
    PORT
      LAYER M4 ;
        RECT  43.116 4.8 43.2 4.824 ;
    END
  END head_record[427]
  PIN head_record[428]
    DIRECTION INPUT ;
    USE SIGNAL ;
    PORT
      LAYER M4 ;
        RECT  43.116 4.992 43.2 5.016 ;
    END
  END head_record[428]
  PIN head_record[429]
    DIRECTION INPUT ;
    USE SIGNAL ;
    PORT
      LAYER M4 ;
        RECT  43.116 5.184 43.2 5.208 ;
    END
  END head_record[429]
  PIN head_record[42]
    DIRECTION INPUT ;
    USE SIGNAL ;
    PORT
      LAYER M4 ;
        RECT  0 14.16 0.084 14.184 ;
    END
  END head_record[42]
  PIN head_record[430]
    DIRECTION INPUT ;
    USE SIGNAL ;
    PORT
      LAYER M4 ;
        RECT  43.116 5.376 43.2 5.4 ;
    END
  END head_record[430]
  PIN head_record[431]
    DIRECTION INPUT ;
    USE SIGNAL ;
    PORT
      LAYER M4 ;
        RECT  43.116 5.568 43.2 5.592 ;
    END
  END head_record[431]
  PIN head_record[432]
    DIRECTION INPUT ;
    USE SIGNAL ;
    PORT
      LAYER M4 ;
        RECT  43.116 5.76 43.2 5.784 ;
    END
  END head_record[432]
  PIN head_record[433]
    DIRECTION INPUT ;
    USE SIGNAL ;
    PORT
      LAYER M4 ;
        RECT  43.116 6 43.2 6.024 ;
    END
  END head_record[433]
  PIN head_record[434]
    DIRECTION INPUT ;
    USE SIGNAL ;
    PORT
      LAYER M4 ;
        RECT  43.116 6.192 43.2 6.216 ;
    END
  END head_record[434]
  PIN head_record[435]
    DIRECTION INPUT ;
    USE SIGNAL ;
    PORT
      LAYER M4 ;
        RECT  43.116 6.384 43.2 6.408 ;
    END
  END head_record[435]
  PIN head_record[436]
    DIRECTION INPUT ;
    USE SIGNAL ;
    PORT
      LAYER M4 ;
        RECT  43.116 6.576 43.2 6.6 ;
    END
  END head_record[436]
  PIN head_record[437]
    DIRECTION INPUT ;
    USE SIGNAL ;
    PORT
      LAYER M4 ;
        RECT  43.116 6.768 43.2 6.792 ;
    END
  END head_record[437]
  PIN head_record[438]
    DIRECTION INPUT ;
    USE SIGNAL ;
    PORT
      LAYER M4 ;
        RECT  43.116 6.96 43.2 6.984 ;
    END
  END head_record[438]
  PIN head_record[439]
    DIRECTION INPUT ;
    USE SIGNAL ;
    PORT
      LAYER M4 ;
        RECT  43.116 7.152 43.2 7.176 ;
    END
  END head_record[439]
  PIN head_record[43]
    DIRECTION INPUT ;
    USE SIGNAL ;
    PORT
      LAYER M4 ;
        RECT  0 14.4 0.084 14.424 ;
    END
  END head_record[43]
  PIN head_record[440]
    DIRECTION INPUT ;
    USE SIGNAL ;
    PORT
      LAYER M4 ;
        RECT  43.116 7.344 43.2 7.368 ;
    END
  END head_record[440]
  PIN head_record[441]
    DIRECTION INPUT ;
    USE SIGNAL ;
    PORT
      LAYER M4 ;
        RECT  43.116 7.536 43.2 7.56 ;
    END
  END head_record[441]
  PIN head_record[442]
    DIRECTION INPUT ;
    USE SIGNAL ;
    PORT
      LAYER M4 ;
        RECT  43.116 7.728 43.2 7.752 ;
    END
  END head_record[442]
  PIN head_record[443]
    DIRECTION INPUT ;
    USE SIGNAL ;
    PORT
      LAYER M4 ;
        RECT  43.116 7.92 43.2 7.944 ;
    END
  END head_record[443]
  PIN head_record[444]
    DIRECTION INPUT ;
    USE SIGNAL ;
    PORT
      LAYER M4 ;
        RECT  43.116 8.112 43.2 8.136 ;
    END
  END head_record[444]
  PIN head_record[445]
    DIRECTION INPUT ;
    USE SIGNAL ;
    PORT
      LAYER M4 ;
        RECT  43.116 8.304 43.2 8.328 ;
    END
  END head_record[445]
  PIN head_record[446]
    DIRECTION INPUT ;
    USE SIGNAL ;
    PORT
      LAYER M4 ;
        RECT  43.116 8.496 43.2 8.52 ;
    END
  END head_record[446]
  PIN head_record[447]
    DIRECTION INPUT ;
    USE SIGNAL ;
    PORT
      LAYER M4 ;
        RECT  43.116 8.688 43.2 8.712 ;
    END
  END head_record[447]
  PIN head_record[448]
    DIRECTION INPUT ;
    USE SIGNAL ;
    PORT
      LAYER M4 ;
        RECT  43.116 8.88 43.2 8.904 ;
    END
  END head_record[448]
  PIN head_record[449]
    DIRECTION INPUT ;
    USE SIGNAL ;
    PORT
      LAYER M4 ;
        RECT  43.116 9.072 43.2 9.096 ;
    END
  END head_record[449]
  PIN head_record[44]
    DIRECTION INPUT ;
    USE SIGNAL ;
    PORT
      LAYER M4 ;
        RECT  0 14.688 0.084 14.712 ;
    END
  END head_record[44]
  PIN head_record[450]
    DIRECTION INPUT ;
    USE SIGNAL ;
    PORT
      LAYER M4 ;
        RECT  43.116 9.264 43.2 9.288 ;
    END
  END head_record[450]
  PIN head_record[451]
    DIRECTION INPUT ;
    USE SIGNAL ;
    PORT
      LAYER M4 ;
        RECT  43.116 9.456 43.2 9.48 ;
    END
  END head_record[451]
  PIN head_record[452]
    DIRECTION INPUT ;
    USE SIGNAL ;
    PORT
      LAYER M4 ;
        RECT  43.116 9.648 43.2 9.672 ;
    END
  END head_record[452]
  PIN head_record[453]
    DIRECTION INPUT ;
    USE SIGNAL ;
    PORT
      LAYER M4 ;
        RECT  43.116 9.84 43.2 9.864 ;
    END
  END head_record[453]
  PIN head_record[454]
    DIRECTION INPUT ;
    USE SIGNAL ;
    PORT
      LAYER M4 ;
        RECT  43.116 10.032 43.2 10.056 ;
    END
  END head_record[454]
  PIN head_record[455]
    DIRECTION INPUT ;
    USE SIGNAL ;
    PORT
      LAYER M4 ;
        RECT  43.116 10.224 43.2 10.248 ;
    END
  END head_record[455]
  PIN head_record[456]
    DIRECTION INPUT ;
    USE SIGNAL ;
    PORT
      LAYER M4 ;
        RECT  43.116 10.416 43.2 10.44 ;
    END
  END head_record[456]
  PIN head_record[457]
    DIRECTION INPUT ;
    USE SIGNAL ;
    PORT
      LAYER M4 ;
        RECT  43.116 10.608 43.2 10.632 ;
    END
  END head_record[457]
  PIN head_record[458]
    DIRECTION INPUT ;
    USE SIGNAL ;
    PORT
      LAYER M4 ;
        RECT  43.116 10.848 43.2 10.872 ;
    END
  END head_record[458]
  PIN head_record[459]
    DIRECTION INPUT ;
    USE SIGNAL ;
    PORT
      LAYER M4 ;
        RECT  43.116 11.04 43.2 11.064 ;
    END
  END head_record[459]
  PIN head_record[45]
    DIRECTION INPUT ;
    USE SIGNAL ;
    PORT
      LAYER M4 ;
        RECT  0 14.976 0.084 15 ;
    END
  END head_record[45]
  PIN head_record[460]
    DIRECTION INPUT ;
    USE SIGNAL ;
    PORT
      LAYER M4 ;
        RECT  43.116 11.232 43.2 11.256 ;
    END
  END head_record[460]
  PIN head_record[461]
    DIRECTION INPUT ;
    USE SIGNAL ;
    PORT
      LAYER M4 ;
        RECT  43.116 11.424 43.2 11.448 ;
    END
  END head_record[461]
  PIN head_record[462]
    DIRECTION INPUT ;
    USE SIGNAL ;
    PORT
      LAYER M4 ;
        RECT  43.116 11.616 43.2 11.64 ;
    END
  END head_record[462]
  PIN head_record[463]
    DIRECTION INPUT ;
    USE SIGNAL ;
    PORT
      LAYER M4 ;
        RECT  43.116 11.808 43.2 11.832 ;
    END
  END head_record[463]
  PIN head_record[464]
    DIRECTION INPUT ;
    USE SIGNAL ;
    PORT
      LAYER M4 ;
        RECT  43.116 12 43.2 12.024 ;
    END
  END head_record[464]
  PIN head_record[465]
    DIRECTION INPUT ;
    USE SIGNAL ;
    PORT
      LAYER M4 ;
        RECT  43.116 12.192 43.2 12.216 ;
    END
  END head_record[465]
  PIN head_record[466]
    DIRECTION INPUT ;
    USE SIGNAL ;
    PORT
      LAYER M4 ;
        RECT  43.116 12.384 43.2 12.408 ;
    END
  END head_record[466]
  PIN head_record[467]
    DIRECTION INPUT ;
    USE SIGNAL ;
    PORT
      LAYER M4 ;
        RECT  43.116 12.576 43.2 12.6 ;
    END
  END head_record[467]
  PIN head_record[468]
    DIRECTION INPUT ;
    USE SIGNAL ;
    PORT
      LAYER M4 ;
        RECT  43.116 12.768 43.2 12.792 ;
    END
  END head_record[468]
  PIN head_record[469]
    DIRECTION INPUT ;
    USE SIGNAL ;
    PORT
      LAYER M4 ;
        RECT  43.116 12.96 43.2 12.984 ;
    END
  END head_record[469]
  PIN head_record[46]
    DIRECTION INPUT ;
    USE SIGNAL ;
    PORT
      LAYER M4 ;
        RECT  0 15.264 0.084 15.288 ;
    END
  END head_record[46]
  PIN head_record[470]
    DIRECTION INPUT ;
    USE SIGNAL ;
    PORT
      LAYER M4 ;
        RECT  43.116 13.152 43.2 13.176 ;
    END
  END head_record[470]
  PIN head_record[471]
    DIRECTION INPUT ;
    USE SIGNAL ;
    PORT
      LAYER M4 ;
        RECT  43.116 13.344 43.2 13.368 ;
    END
  END head_record[471]
  PIN head_record[472]
    DIRECTION INPUT ;
    USE SIGNAL ;
    PORT
      LAYER M4 ;
        RECT  43.116 13.536 43.2 13.56 ;
    END
  END head_record[472]
  PIN head_record[473]
    DIRECTION INPUT ;
    USE SIGNAL ;
    PORT
      LAYER M4 ;
        RECT  43.116 13.728 43.2 13.752 ;
    END
  END head_record[473]
  PIN head_record[474]
    DIRECTION INPUT ;
    USE SIGNAL ;
    PORT
      LAYER M4 ;
        RECT  43.116 13.92 43.2 13.944 ;
    END
  END head_record[474]
  PIN head_record[475]
    DIRECTION INPUT ;
    USE SIGNAL ;
    PORT
      LAYER M4 ;
        RECT  43.116 14.112 43.2 14.136 ;
    END
  END head_record[475]
  PIN head_record[476]
    DIRECTION INPUT ;
    USE SIGNAL ;
    PORT
      LAYER M4 ;
        RECT  43.116 14.304 43.2 14.328 ;
    END
  END head_record[476]
  PIN head_record[477]
    DIRECTION INPUT ;
    USE SIGNAL ;
    PORT
      LAYER M4 ;
        RECT  43.116 14.496 43.2 14.52 ;
    END
  END head_record[477]
  PIN head_record[478]
    DIRECTION INPUT ;
    USE SIGNAL ;
    PORT
      LAYER M4 ;
        RECT  43.116 14.688 43.2 14.712 ;
    END
  END head_record[478]
  PIN head_record[479]
    DIRECTION INPUT ;
    USE SIGNAL ;
    PORT
      LAYER M4 ;
        RECT  43.116 14.88 43.2 14.904 ;
    END
  END head_record[479]
  PIN head_record[47]
    DIRECTION INPUT ;
    USE SIGNAL ;
    PORT
      LAYER M4 ;
        RECT  0 15.552 0.084 15.576 ;
    END
  END head_record[47]
  PIN head_record[480]
    DIRECTION INPUT ;
    USE SIGNAL ;
    PORT
      LAYER M4 ;
        RECT  43.116 15.072 43.2 15.096 ;
    END
  END head_record[480]
  PIN head_record[481]
    DIRECTION INPUT ;
    USE SIGNAL ;
    PORT
      LAYER M4 ;
        RECT  43.116 15.264 43.2 15.288 ;
    END
  END head_record[481]
  PIN head_record[482]
    DIRECTION INPUT ;
    USE SIGNAL ;
    PORT
      LAYER M4 ;
        RECT  43.116 15.456 43.2 15.48 ;
    END
  END head_record[482]
  PIN head_record[483]
    DIRECTION INPUT ;
    USE SIGNAL ;
    PORT
      LAYER M4 ;
        RECT  43.116 15.696 43.2 15.72 ;
    END
  END head_record[483]
  PIN head_record[484]
    DIRECTION INPUT ;
    USE SIGNAL ;
    PORT
      LAYER M4 ;
        RECT  43.116 15.888 43.2 15.912 ;
    END
  END head_record[484]
  PIN head_record[485]
    DIRECTION INPUT ;
    USE SIGNAL ;
    PORT
      LAYER M4 ;
        RECT  43.116 16.08 43.2 16.104 ;
    END
  END head_record[485]
  PIN head_record[486]
    DIRECTION INPUT ;
    USE SIGNAL ;
    PORT
      LAYER M4 ;
        RECT  43.116 16.272 43.2 16.296 ;
    END
  END head_record[486]
  PIN head_record[487]
    DIRECTION INPUT ;
    USE SIGNAL ;
    PORT
      LAYER M4 ;
        RECT  43.116 16.464 43.2 16.488 ;
    END
  END head_record[487]
  PIN head_record[488]
    DIRECTION INPUT ;
    USE SIGNAL ;
    PORT
      LAYER M4 ;
        RECT  43.116 16.656 43.2 16.68 ;
    END
  END head_record[488]
  PIN head_record[489]
    DIRECTION INPUT ;
    USE SIGNAL ;
    PORT
      LAYER M4 ;
        RECT  43.116 16.848 43.2 16.872 ;
    END
  END head_record[489]
  PIN head_record[48]
    DIRECTION INPUT ;
    USE SIGNAL ;
    PORT
      LAYER M4 ;
        RECT  0 15.84 0.084 15.864 ;
    END
  END head_record[48]
  PIN head_record[490]
    DIRECTION INPUT ;
    USE SIGNAL ;
    PORT
      LAYER M4 ;
        RECT  43.116 17.04 43.2 17.064 ;
    END
  END head_record[490]
  PIN head_record[491]
    DIRECTION INPUT ;
    USE SIGNAL ;
    PORT
      LAYER M4 ;
        RECT  43.116 17.232 43.2 17.256 ;
    END
  END head_record[491]
  PIN head_record[492]
    DIRECTION INPUT ;
    USE SIGNAL ;
    PORT
      LAYER M4 ;
        RECT  43.116 17.424 43.2 17.448 ;
    END
  END head_record[492]
  PIN head_record[493]
    DIRECTION INPUT ;
    USE SIGNAL ;
    PORT
      LAYER M4 ;
        RECT  43.116 17.616 43.2 17.64 ;
    END
  END head_record[493]
  PIN head_record[494]
    DIRECTION INPUT ;
    USE SIGNAL ;
    PORT
      LAYER M4 ;
        RECT  43.116 17.808 43.2 17.832 ;
    END
  END head_record[494]
  PIN head_record[495]
    DIRECTION INPUT ;
    USE SIGNAL ;
    PORT
      LAYER M4 ;
        RECT  43.116 18 43.2 18.024 ;
    END
  END head_record[495]
  PIN head_record[496]
    DIRECTION INPUT ;
    USE SIGNAL ;
    PORT
      LAYER M4 ;
        RECT  43.116 18.192 43.2 18.216 ;
    END
  END head_record[496]
  PIN head_record[497]
    DIRECTION INPUT ;
    USE SIGNAL ;
    PORT
      LAYER M4 ;
        RECT  43.116 18.384 43.2 18.408 ;
    END
  END head_record[497]
  PIN head_record[498]
    DIRECTION INPUT ;
    USE SIGNAL ;
    PORT
      LAYER M4 ;
        RECT  43.116 18.576 43.2 18.6 ;
    END
  END head_record[498]
  PIN head_record[499]
    DIRECTION INPUT ;
    USE SIGNAL ;
    PORT
      LAYER M4 ;
        RECT  43.116 18.768 43.2 18.792 ;
    END
  END head_record[499]
  PIN head_record[49]
    DIRECTION INPUT ;
    USE SIGNAL ;
    PORT
      LAYER M4 ;
        RECT  0 16.128 0.084 16.152 ;
    END
  END head_record[49]
  PIN head_record[4]
    DIRECTION INPUT ;
    USE SIGNAL ;
    PORT
      LAYER M4 ;
        RECT  0 3.456 0.084 3.48 ;
    END
  END head_record[4]
  PIN head_record[500]
    DIRECTION INPUT ;
    USE SIGNAL ;
    PORT
      LAYER M4 ;
        RECT  43.116 18.96 43.2 18.984 ;
    END
  END head_record[500]
  PIN head_record[501]
    DIRECTION INPUT ;
    USE SIGNAL ;
    PORT
      LAYER M4 ;
        RECT  43.116 19.152 43.2 19.176 ;
    END
  END head_record[501]
  PIN head_record[502]
    DIRECTION INPUT ;
    USE SIGNAL ;
    PORT
      LAYER M4 ;
        RECT  43.116 19.344 43.2 19.368 ;
    END
  END head_record[502]
  PIN head_record[503]
    DIRECTION INPUT ;
    USE SIGNAL ;
    PORT
      LAYER M4 ;
        RECT  43.116 19.536 43.2 19.56 ;
    END
  END head_record[503]
  PIN head_record[504]
    DIRECTION INPUT ;
    USE SIGNAL ;
    PORT
      LAYER M4 ;
        RECT  43.116 19.728 43.2 19.752 ;
    END
  END head_record[504]
  PIN head_record[505]
    DIRECTION INPUT ;
    USE SIGNAL ;
    PORT
      LAYER M4 ;
        RECT  43.116 19.92 43.2 19.944 ;
    END
  END head_record[505]
  PIN head_record[506]
    DIRECTION INPUT ;
    USE SIGNAL ;
    PORT
      LAYER M4 ;
        RECT  43.116 20.112 43.2 20.136 ;
    END
  END head_record[506]
  PIN head_record[507]
    DIRECTION INPUT ;
    USE SIGNAL ;
    PORT
      LAYER M4 ;
        RECT  43.116 20.304 43.2 20.328 ;
    END
  END head_record[507]
  PIN head_record[508]
    DIRECTION INPUT ;
    USE SIGNAL ;
    PORT
      LAYER M4 ;
        RECT  43.116 20.544 43.2 20.568 ;
    END
  END head_record[508]
  PIN head_record[509]
    DIRECTION INPUT ;
    USE SIGNAL ;
    PORT
      LAYER M4 ;
        RECT  43.116 20.736 43.2 20.76 ;
    END
  END head_record[509]
  PIN head_record[50]
    DIRECTION INPUT ;
    USE SIGNAL ;
    PORT
      LAYER M4 ;
        RECT  0 16.368 0.084 16.392 ;
    END
  END head_record[50]
  PIN head_record[510]
    DIRECTION INPUT ;
    USE SIGNAL ;
    PORT
      LAYER M4 ;
        RECT  43.116 20.928 43.2 20.952 ;
    END
  END head_record[510]
  PIN head_record[511]
    DIRECTION INPUT ;
    USE SIGNAL ;
    PORT
      LAYER M4 ;
        RECT  43.116 21.12 43.2 21.144 ;
    END
  END head_record[511]
  PIN head_record[512]
    DIRECTION INPUT ;
    USE SIGNAL ;
    PORT
      LAYER M4 ;
        RECT  43.116 21.312 43.2 21.336 ;
    END
  END head_record[512]
  PIN head_record[513]
    DIRECTION INPUT ;
    USE SIGNAL ;
    PORT
      LAYER M4 ;
        RECT  43.116 21.504 43.2 21.528 ;
    END
  END head_record[513]
  PIN head_record[514]
    DIRECTION INPUT ;
    USE SIGNAL ;
    PORT
      LAYER M4 ;
        RECT  43.116 21.696 43.2 21.72 ;
    END
  END head_record[514]
  PIN head_record[515]
    DIRECTION INPUT ;
    USE SIGNAL ;
    PORT
      LAYER M4 ;
        RECT  43.116 21.888 43.2 21.912 ;
    END
  END head_record[515]
  PIN head_record[516]
    DIRECTION INPUT ;
    USE SIGNAL ;
    PORT
      LAYER M4 ;
        RECT  43.116 22.08 43.2 22.104 ;
    END
  END head_record[516]
  PIN head_record[517]
    DIRECTION INPUT ;
    USE SIGNAL ;
    PORT
      LAYER M4 ;
        RECT  43.116 22.272 43.2 22.296 ;
    END
  END head_record[517]
  PIN head_record[518]
    DIRECTION INPUT ;
    USE SIGNAL ;
    PORT
      LAYER M4 ;
        RECT  43.116 22.464 43.2 22.488 ;
    END
  END head_record[518]
  PIN head_record[519]
    DIRECTION INPUT ;
    USE SIGNAL ;
    PORT
      LAYER M4 ;
        RECT  43.116 22.656 43.2 22.68 ;
    END
  END head_record[519]
  PIN head_record[51]
    DIRECTION INPUT ;
    USE SIGNAL ;
    PORT
      LAYER M4 ;
        RECT  0 16.656 0.084 16.68 ;
    END
  END head_record[51]
  PIN head_record[520]
    DIRECTION INPUT ;
    USE SIGNAL ;
    PORT
      LAYER M4 ;
        RECT  43.116 22.848 43.2 22.872 ;
    END
  END head_record[520]
  PIN head_record[521]
    DIRECTION INPUT ;
    USE SIGNAL ;
    PORT
      LAYER M4 ;
        RECT  43.116 23.04 43.2 23.064 ;
    END
  END head_record[521]
  PIN head_record[522]
    DIRECTION INPUT ;
    USE SIGNAL ;
    PORT
      LAYER M4 ;
        RECT  43.116 23.232 43.2 23.256 ;
    END
  END head_record[522]
  PIN head_record[523]
    DIRECTION INPUT ;
    USE SIGNAL ;
    PORT
      LAYER M4 ;
        RECT  43.116 23.424 43.2 23.448 ;
    END
  END head_record[523]
  PIN head_record[524]
    DIRECTION INPUT ;
    USE SIGNAL ;
    PORT
      LAYER M4 ;
        RECT  43.116 23.616 43.2 23.64 ;
    END
  END head_record[524]
  PIN head_record[525]
    DIRECTION INPUT ;
    USE SIGNAL ;
    PORT
      LAYER M4 ;
        RECT  43.116 23.808 43.2 23.832 ;
    END
  END head_record[525]
  PIN head_record[526]
    DIRECTION INPUT ;
    USE SIGNAL ;
    PORT
      LAYER M4 ;
        RECT  43.116 24 43.2 24.024 ;
    END
  END head_record[526]
  PIN head_record[527]
    DIRECTION INPUT ;
    USE SIGNAL ;
    PORT
      LAYER M4 ;
        RECT  43.116 24.192 43.2 24.216 ;
    END
  END head_record[527]
  PIN head_record[528]
    DIRECTION INPUT ;
    USE SIGNAL ;
    PORT
      LAYER M4 ;
        RECT  43.116 24.384 43.2 24.408 ;
    END
  END head_record[528]
  PIN head_record[529]
    DIRECTION INPUT ;
    USE SIGNAL ;
    PORT
      LAYER M4 ;
        RECT  43.116 24.576 43.2 24.6 ;
    END
  END head_record[529]
  PIN head_record[52]
    DIRECTION INPUT ;
    USE SIGNAL ;
    PORT
      LAYER M4 ;
        RECT  0 16.944 0.084 16.968 ;
    END
  END head_record[52]
  PIN head_record[530]
    DIRECTION INPUT ;
    USE SIGNAL ;
    PORT
      LAYER M4 ;
        RECT  43.116 24.768 43.2 24.792 ;
    END
  END head_record[530]
  PIN head_record[531]
    DIRECTION INPUT ;
    USE SIGNAL ;
    PORT
      LAYER M4 ;
        RECT  43.116 24.96 43.2 24.984 ;
    END
  END head_record[531]
  PIN head_record[532]
    DIRECTION INPUT ;
    USE SIGNAL ;
    PORT
      LAYER M4 ;
        RECT  43.116 25.152 43.2 25.176 ;
    END
  END head_record[532]
  PIN head_record[533]
    DIRECTION INPUT ;
    USE SIGNAL ;
    PORT
      LAYER M4 ;
        RECT  43.116 25.392 43.2 25.416 ;
    END
  END head_record[533]
  PIN head_record[534]
    DIRECTION INPUT ;
    USE SIGNAL ;
    PORT
      LAYER M4 ;
        RECT  43.116 25.584 43.2 25.608 ;
    END
  END head_record[534]
  PIN head_record[535]
    DIRECTION INPUT ;
    USE SIGNAL ;
    PORT
      LAYER M4 ;
        RECT  43.116 25.776 43.2 25.8 ;
    END
  END head_record[535]
  PIN head_record[536]
    DIRECTION INPUT ;
    USE SIGNAL ;
    PORT
      LAYER M4 ;
        RECT  43.116 25.968 43.2 25.992 ;
    END
  END head_record[536]
  PIN head_record[537]
    DIRECTION INPUT ;
    USE SIGNAL ;
    PORT
      LAYER M4 ;
        RECT  43.116 26.16 43.2 26.184 ;
    END
  END head_record[537]
  PIN head_record[538]
    DIRECTION INPUT ;
    USE SIGNAL ;
    PORT
      LAYER M4 ;
        RECT  43.116 26.352 43.2 26.376 ;
    END
  END head_record[538]
  PIN head_record[539]
    DIRECTION INPUT ;
    USE SIGNAL ;
    PORT
      LAYER M4 ;
        RECT  43.116 26.544 43.2 26.568 ;
    END
  END head_record[539]
  PIN head_record[53]
    DIRECTION INPUT ;
    USE SIGNAL ;
    PORT
      LAYER M4 ;
        RECT  0 17.232 0.084 17.256 ;
    END
  END head_record[53]
  PIN head_record[540]
    DIRECTION INPUT ;
    USE SIGNAL ;
    PORT
      LAYER M4 ;
        RECT  43.116 26.736 43.2 26.76 ;
    END
  END head_record[540]
  PIN head_record[541]
    DIRECTION INPUT ;
    USE SIGNAL ;
    PORT
      LAYER M4 ;
        RECT  43.116 26.928 43.2 26.952 ;
    END
  END head_record[541]
  PIN head_record[542]
    DIRECTION INPUT ;
    USE SIGNAL ;
    PORT
      LAYER M4 ;
        RECT  43.116 27.12 43.2 27.144 ;
    END
  END head_record[542]
  PIN head_record[543]
    DIRECTION INPUT ;
    USE SIGNAL ;
    PORT
      LAYER M4 ;
        RECT  43.116 27.312 43.2 27.336 ;
    END
  END head_record[543]
  PIN head_record[544]
    DIRECTION INPUT ;
    USE SIGNAL ;
    PORT
      LAYER M4 ;
        RECT  43.116 27.504 43.2 27.528 ;
    END
  END head_record[544]
  PIN head_record[545]
    DIRECTION INPUT ;
    USE SIGNAL ;
    PORT
      LAYER M4 ;
        RECT  43.116 27.696 43.2 27.72 ;
    END
  END head_record[545]
  PIN head_record[546]
    DIRECTION INPUT ;
    USE SIGNAL ;
    PORT
      LAYER M4 ;
        RECT  43.116 27.888 43.2 27.912 ;
    END
  END head_record[546]
  PIN head_record[547]
    DIRECTION INPUT ;
    USE SIGNAL ;
    PORT
      LAYER M4 ;
        RECT  43.116 28.08 43.2 28.104 ;
    END
  END head_record[547]
  PIN head_record[548]
    DIRECTION INPUT ;
    USE SIGNAL ;
    PORT
      LAYER M4 ;
        RECT  43.116 28.272 43.2 28.296 ;
    END
  END head_record[548]
  PIN head_record[549]
    DIRECTION INPUT ;
    USE SIGNAL ;
    PORT
      LAYER M4 ;
        RECT  43.116 28.464 43.2 28.488 ;
    END
  END head_record[549]
  PIN head_record[54]
    DIRECTION INPUT ;
    USE SIGNAL ;
    PORT
      LAYER M4 ;
        RECT  0 17.52 0.084 17.544 ;
    END
  END head_record[54]
  PIN head_record[550]
    DIRECTION INPUT ;
    USE SIGNAL ;
    PORT
      LAYER M4 ;
        RECT  43.116 28.656 43.2 28.68 ;
    END
  END head_record[550]
  PIN head_record[551]
    DIRECTION INPUT ;
    USE SIGNAL ;
    PORT
      LAYER M4 ;
        RECT  43.116 28.848 43.2 28.872 ;
    END
  END head_record[551]
  PIN head_record[55]
    DIRECTION INPUT ;
    USE SIGNAL ;
    PORT
      LAYER M4 ;
        RECT  0 17.808 0.084 17.832 ;
    END
  END head_record[55]
  PIN head_record[56]
    DIRECTION INPUT ;
    USE SIGNAL ;
    PORT
      LAYER M4 ;
        RECT  0 18.096 0.084 18.12 ;
    END
  END head_record[56]
  PIN head_record[57]
    DIRECTION INPUT ;
    USE SIGNAL ;
    PORT
      LAYER M4 ;
        RECT  0 18.336 0.084 18.36 ;
    END
  END head_record[57]
  PIN head_record[58]
    DIRECTION INPUT ;
    USE SIGNAL ;
    PORT
      LAYER M4 ;
        RECT  0 18.624 0.084 18.648 ;
    END
  END head_record[58]
  PIN head_record[59]
    DIRECTION INPUT ;
    USE SIGNAL ;
    PORT
      LAYER M4 ;
        RECT  0 18.912 0.084 18.936 ;
    END
  END head_record[59]
  PIN head_record[5]
    DIRECTION INPUT ;
    USE SIGNAL ;
    PORT
      LAYER M4 ;
        RECT  0 3.744 0.084 3.768 ;
    END
  END head_record[5]
  PIN head_record[60]
    DIRECTION INPUT ;
    USE SIGNAL ;
    PORT
      LAYER M4 ;
        RECT  0 19.2 0.084 19.224 ;
    END
  END head_record[60]
  PIN head_record[61]
    DIRECTION INPUT ;
    USE SIGNAL ;
    PORT
      LAYER M4 ;
        RECT  0 19.488 0.084 19.512 ;
    END
  END head_record[61]
  PIN head_record[62]
    DIRECTION INPUT ;
    USE SIGNAL ;
    PORT
      LAYER M4 ;
        RECT  0 19.776 0.084 19.8 ;
    END
  END head_record[62]
  PIN head_record[63]
    DIRECTION INPUT ;
    USE SIGNAL ;
    PORT
      LAYER M4 ;
        RECT  0 20.064 0.084 20.088 ;
    END
  END head_record[63]
  PIN head_record[64]
    DIRECTION INPUT ;
    USE SIGNAL ;
    PORT
      LAYER M4 ;
        RECT  0 20.304 0.084 20.328 ;
    END
  END head_record[64]
  PIN head_record[65]
    DIRECTION INPUT ;
    USE SIGNAL ;
    PORT
      LAYER M4 ;
        RECT  0 20.592 0.084 20.616 ;
    END
  END head_record[65]
  PIN head_record[66]
    DIRECTION INPUT ;
    USE SIGNAL ;
    PORT
      LAYER M4 ;
        RECT  0 20.88 0.084 20.904 ;
    END
  END head_record[66]
  PIN head_record[67]
    DIRECTION INPUT ;
    USE SIGNAL ;
    PORT
      LAYER M4 ;
        RECT  0 21.168 0.084 21.192 ;
    END
  END head_record[67]
  PIN head_record[68]
    DIRECTION INPUT ;
    USE SIGNAL ;
    PORT
      LAYER M4 ;
        RECT  0 21.456 0.084 21.48 ;
    END
  END head_record[68]
  PIN head_record[69]
    DIRECTION INPUT ;
    USE SIGNAL ;
    PORT
      LAYER M4 ;
        RECT  0 21.744 0.084 21.768 ;
    END
  END head_record[69]
  PIN head_record[6]
    DIRECTION INPUT ;
    USE SIGNAL ;
    PORT
      LAYER M4 ;
        RECT  0 4.032 0.084 4.056 ;
    END
  END head_record[6]
  PIN head_record[70]
    DIRECTION INPUT ;
    USE SIGNAL ;
    PORT
      LAYER M4 ;
        RECT  0 22.032 0.084 22.056 ;
    END
  END head_record[70]
  PIN head_record[71]
    DIRECTION INPUT ;
    USE SIGNAL ;
    PORT
      LAYER M4 ;
        RECT  0 22.272 0.084 22.296 ;
    END
  END head_record[71]
  PIN head_record[72]
    DIRECTION INPUT ;
    USE SIGNAL ;
    PORT
      LAYER M4 ;
        RECT  0 22.56 0.084 22.584 ;
    END
  END head_record[72]
  PIN head_record[73]
    DIRECTION INPUT ;
    USE SIGNAL ;
    PORT
      LAYER M4 ;
        RECT  0 22.848 0.084 22.872 ;
    END
  END head_record[73]
  PIN head_record[74]
    DIRECTION INPUT ;
    USE SIGNAL ;
    PORT
      LAYER M4 ;
        RECT  0 23.136 0.084 23.16 ;
    END
  END head_record[74]
  PIN head_record[75]
    DIRECTION INPUT ;
    USE SIGNAL ;
    PORT
      LAYER M4 ;
        RECT  0 23.424 0.084 23.448 ;
    END
  END head_record[75]
  PIN head_record[76]
    DIRECTION INPUT ;
    USE SIGNAL ;
    PORT
      LAYER M4 ;
        RECT  0 23.712 0.084 23.736 ;
    END
  END head_record[76]
  PIN head_record[77]
    DIRECTION INPUT ;
    USE SIGNAL ;
    PORT
      LAYER M4 ;
        RECT  0 24 0.084 24.024 ;
    END
  END head_record[77]
  PIN head_record[78]
    DIRECTION INPUT ;
    USE SIGNAL ;
    PORT
      LAYER M4 ;
        RECT  0 24.24 0.084 24.264 ;
    END
  END head_record[78]
  PIN head_record[79]
    DIRECTION INPUT ;
    USE SIGNAL ;
    PORT
      LAYER M4 ;
        RECT  0 24.528 0.084 24.552 ;
    END
  END head_record[79]
  PIN head_record[7]
    DIRECTION INPUT ;
    USE SIGNAL ;
    PORT
      LAYER M4 ;
        RECT  0 4.32 0.084 4.344 ;
    END
  END head_record[7]
  PIN head_record[80]
    DIRECTION INPUT ;
    USE SIGNAL ;
    PORT
      LAYER M4 ;
        RECT  0 24.816 0.084 24.84 ;
    END
  END head_record[80]
  PIN head_record[81]
    DIRECTION INPUT ;
    USE SIGNAL ;
    PORT
      LAYER M4 ;
        RECT  0 25.104 0.084 25.128 ;
    END
  END head_record[81]
  PIN head_record[82]
    DIRECTION INPUT ;
    USE SIGNAL ;
    PORT
      LAYER M4 ;
        RECT  0 25.392 0.084 25.416 ;
    END
  END head_record[82]
  PIN head_record[83]
    DIRECTION INPUT ;
    USE SIGNAL ;
    PORT
      LAYER M4 ;
        RECT  0 25.68 0.084 25.704 ;
    END
  END head_record[83]
  PIN head_record[84]
    DIRECTION INPUT ;
    USE SIGNAL ;
    PORT
      LAYER M4 ;
        RECT  0 25.968 0.084 25.992 ;
    END
  END head_record[84]
  PIN head_record[85]
    DIRECTION INPUT ;
    USE SIGNAL ;
    PORT
      LAYER M4 ;
        RECT  0 26.208 0.084 26.232 ;
    END
  END head_record[85]
  PIN head_record[86]
    DIRECTION INPUT ;
    USE SIGNAL ;
    PORT
      LAYER M4 ;
        RECT  0 26.496 0.084 26.52 ;
    END
  END head_record[86]
  PIN head_record[87]
    DIRECTION INPUT ;
    USE SIGNAL ;
    PORT
      LAYER M4 ;
        RECT  0 26.784 0.084 26.808 ;
    END
  END head_record[87]
  PIN head_record[88]
    DIRECTION INPUT ;
    USE SIGNAL ;
    PORT
      LAYER M4 ;
        RECT  0 27.072 0.084 27.096 ;
    END
  END head_record[88]
  PIN head_record[89]
    DIRECTION INPUT ;
    USE SIGNAL ;
    PORT
      LAYER M4 ;
        RECT  0 27.36 0.084 27.384 ;
    END
  END head_record[89]
  PIN head_record[8]
    DIRECTION INPUT ;
    USE SIGNAL ;
    PORT
      LAYER M4 ;
        RECT  0 4.608 0.084 4.632 ;
    END
  END head_record[8]
  PIN head_record[90]
    DIRECTION INPUT ;
    USE SIGNAL ;
    PORT
      LAYER M4 ;
        RECT  0 27.648 0.084 27.672 ;
    END
  END head_record[90]
  PIN head_record[91]
    DIRECTION INPUT ;
    USE SIGNAL ;
    PORT
      LAYER M4 ;
        RECT  0 27.888 0.084 27.912 ;
    END
  END head_record[91]
  PIN head_record[92]
    DIRECTION INPUT ;
    USE SIGNAL ;
    PORT
      LAYER M4 ;
        RECT  0 28.176 0.084 28.2 ;
    END
  END head_record[92]
  PIN head_record[93]
    DIRECTION INPUT ;
    USE SIGNAL ;
    PORT
      LAYER M4 ;
        RECT  0 28.464 0.084 28.488 ;
    END
  END head_record[93]
  PIN head_record[94]
    DIRECTION INPUT ;
    USE SIGNAL ;
    PORT
      LAYER M4 ;
        RECT  0 28.752 0.084 28.776 ;
    END
  END head_record[94]
  PIN head_record[95]
    DIRECTION INPUT ;
    USE SIGNAL ;
    PORT
      LAYER M4 ;
        RECT  0 29.04 0.084 29.064 ;
    END
  END head_record[95]
  PIN head_record[96]
    DIRECTION INPUT ;
    USE SIGNAL ;
    PORT
      LAYER M4 ;
        RECT  0 29.328 0.084 29.352 ;
    END
  END head_record[96]
  PIN head_record[97]
    DIRECTION INPUT ;
    USE SIGNAL ;
    PORT
      LAYER M4 ;
        RECT  0 29.616 0.084 29.64 ;
    END
  END head_record[97]
  PIN head_record[98]
    DIRECTION INPUT ;
    USE SIGNAL ;
    PORT
      LAYER M4 ;
        RECT  0 29.856 0.084 29.88 ;
    END
  END head_record[98]
  PIN head_record[99]
    DIRECTION INPUT ;
    USE SIGNAL ;
    PORT
      LAYER M4 ;
        RECT  0 30.144 0.084 30.168 ;
    END
  END head_record[99]
  PIN head_record[9]
    DIRECTION INPUT ;
    USE SIGNAL ;
    PORT
      LAYER M4 ;
        RECT  0 4.848 0.084 4.872 ;
    END
  END head_record[9]
  PIN ovl_users[0]
    DIRECTION INPUT ;
    USE SIGNAL ;
    PORT
      LAYER M5 ;
        RECT  20.688 43.116 20.712 43.2 ;
    END
  END ovl_users[0]
  PIN ovl_users[1]
    DIRECTION INPUT ;
    USE SIGNAL ;
    PORT
      LAYER M5 ;
        RECT  20.928 43.116 20.952 43.2 ;
    END
  END ovl_users[1]
  PIN ovl_users[2]
    DIRECTION INPUT ;
    USE SIGNAL ;
    PORT
      LAYER M5 ;
        RECT  21.216 43.116 21.24 43.2 ;
    END
  END ovl_users[2]
  PIN ovl_users[3]
    DIRECTION INPUT ;
    USE SIGNAL ;
    PORT
      LAYER M5 ;
        RECT  21.456 43.116 21.48 43.2 ;
    END
  END ovl_users[3]
  PIN reseed
    DIRECTION INPUT ;
    USE SIGNAL ;
    PORT
      LAYER M5 ;
        RECT  22.992 43.116 23.016 43.2 ;
    END
  END reseed
  PIN rst_n
    DIRECTION INPUT ;
    USE SIGNAL ;
    PORT
      LAYER M5 ;
        RECT  20.448 43.116 20.472 43.2 ;
    END
  END rst_n
  PIN VDD
    DIRECTION INOUT ;
    USE POWER ;
    PORT
      LAYER M5 ;
        RECT  40.392 2.151 40.512 41.049 ;
        RECT  37.692 2.151 37.812 41.049 ;
        RECT  34.992 2.151 35.112 41.049 ;
        RECT  32.292 2.151 32.412 41.049 ;
        RECT  29.592 2.151 29.712 41.049 ;
        RECT  26.892 2.151 27.012 41.049 ;
        RECT  24.192 2.151 24.312 41.049 ;
        RECT  21.492 2.151 21.612 41.049 ;
        RECT  18.792 2.151 18.912 41.049 ;
        RECT  16.092 2.151 16.212 41.049 ;
        RECT  13.392 2.151 13.512 41.049 ;
        RECT  10.692 2.151 10.812 41.049 ;
        RECT  7.992 2.151 8.112 41.049 ;
        RECT  5.292 2.151 5.412 41.049 ;
        RECT  2.592 2.151 2.712 41.049 ;
    END
  END VDD
  PIN VSS
    DIRECTION INOUT ;
    USE GROUND ;
    PORT
      LAYER M5 ;
        RECT  40.2 2.137 40.32 41.063 ;
        RECT  37.5 2.137 37.62 41.063 ;
        RECT  34.8 2.137 34.92 41.063 ;
        RECT  32.1 2.137 32.22 41.063 ;
        RECT  29.4 2.137 29.52 41.063 ;
        RECT  26.7 2.137 26.82 41.063 ;
        RECT  24 2.137 24.12 41.063 ;
        RECT  21.3 2.137 21.42 41.063 ;
        RECT  18.6 2.137 18.72 41.063 ;
        RECT  15.9 2.137 16.02 41.063 ;
        RECT  13.2 2.137 13.32 41.063 ;
        RECT  10.5 2.137 10.62 41.063 ;
        RECT  7.8 2.137 7.92 41.063 ;
        RECT  5.1 2.137 5.22 41.063 ;
        RECT  2.4 2.137 2.52 41.063 ;
    END
  END VSS
  OBS
    LAYER RVTN ;
     RECT  2.16 2.16 41.04 2.295 ;
     RECT  2.16 2.565 41.04 2.835 ;
     RECT  2.16 3.105 41.04 3.375 ;
     RECT  2.16 3.645 41.04 3.915 ;
     RECT  2.16 4.185 41.04 4.455 ;
     RECT  2.16 4.725 41.04 4.995 ;
     RECT  2.16 5.265 41.04 5.535 ;
     RECT  2.16 5.805 41.04 6.075 ;
     RECT  2.16 6.345 41.04 6.615 ;
     RECT  2.16 6.885 41.04 7.155 ;
     RECT  2.16 7.425 41.04 7.695 ;
     RECT  2.16 7.965 41.04 8.235 ;
     RECT  2.16 8.505 41.04 8.775 ;
     RECT  2.16 9.045 41.04 9.315 ;
     RECT  2.16 9.585 41.04 9.855 ;
     RECT  2.16 10.125 41.04 10.395 ;
     RECT  2.16 10.665 41.04 10.935 ;
     RECT  2.16 11.205 41.04 11.475 ;
     RECT  2.16 11.745 41.04 12.015 ;
     RECT  2.16 12.285 41.04 12.555 ;
     RECT  2.16 12.825 41.04 13.095 ;
     RECT  2.16 13.365 41.04 13.635 ;
     RECT  2.16 13.905 41.04 14.175 ;
     RECT  2.16 14.445 41.04 14.715 ;
     RECT  2.16 14.985 41.04 15.255 ;
     RECT  2.16 15.525 41.04 15.795 ;
     RECT  2.16 16.065 41.04 16.335 ;
     RECT  2.16 16.605 41.04 16.875 ;
     RECT  2.16 17.145 41.04 17.415 ;
     RECT  2.16 17.685 41.04 17.955 ;
     RECT  2.16 18.225 41.04 18.495 ;
     RECT  2.16 18.765 41.04 19.035 ;
     RECT  2.16 19.305 41.04 19.575 ;
     RECT  2.16 19.845 41.04 20.115 ;
     RECT  2.16 20.385 41.04 20.655 ;
     RECT  2.16 20.925 41.04 21.195 ;
     RECT  2.16 21.465 41.04 21.735 ;
     RECT  2.16 22.005 41.04 22.275 ;
     RECT  2.16 22.545 41.04 22.815 ;
     RECT  2.16 23.085 41.04 23.355 ;
     RECT  2.16 23.625 41.04 23.895 ;
     RECT  2.16 24.165 41.04 24.435 ;
     RECT  2.16 24.705 41.04 24.975 ;
     RECT  2.16 25.245 41.04 25.515 ;
     RECT  2.16 25.785 41.04 26.055 ;
     RECT  2.16 26.325 41.04 26.595 ;
     RECT  2.16 26.865 41.04 27.135 ;
     RECT  2.16 27.405 41.04 27.675 ;
     RECT  2.16 27.945 41.04 28.215 ;
     RECT  2.16 28.485 41.04 28.755 ;
     RECT  2.16 29.025 41.04 29.295 ;
     RECT  2.16 29.565 41.04 29.835 ;
     RECT  2.16 30.105 41.04 30.375 ;
     RECT  2.16 30.645 41.04 30.915 ;
     RECT  2.16 31.185 41.04 31.455 ;
     RECT  2.16 31.725 41.04 31.995 ;
     RECT  2.16 32.265 41.04 32.535 ;
     RECT  2.16 32.805 41.04 33.075 ;
     RECT  2.16 33.345 41.04 33.615 ;
     RECT  2.16 33.885 41.04 34.155 ;
     RECT  2.16 34.425 41.04 34.695 ;
     RECT  2.16 34.965 41.04 35.235 ;
     RECT  2.16 35.505 41.04 35.775 ;
     RECT  2.16 36.045 41.04 36.315 ;
     RECT  2.16 36.585 41.04 36.855 ;
     RECT  2.16 37.125 41.04 37.395 ;
     RECT  2.16 37.665 41.04 37.935 ;
     RECT  2.16 38.205 41.04 38.475 ;
     RECT  2.16 38.745 41.04 39.015 ;
     RECT  2.16 39.285 41.04 39.555 ;
     RECT  2.16 39.825 41.04 40.095 ;
     RECT  2.16 40.365 41.04 40.635 ;
     RECT  2.16 40.905 41.04 41.04 ;
    LAYER RVTP ;
     RECT  2.16 2.295 41.04 2.565 ;
     RECT  2.16 2.835 41.04 3.105 ;
     RECT  2.16 3.375 41.04 3.645 ;
     RECT  2.16 3.915 41.04 4.185 ;
     RECT  2.16 4.455 41.04 4.725 ;
     RECT  2.16 4.995 41.04 5.265 ;
     RECT  2.16 5.535 41.04 5.805 ;
     RECT  2.16 6.075 41.04 6.345 ;
     RECT  2.16 6.615 41.04 6.885 ;
     RECT  2.16 7.155 41.04 7.425 ;
     RECT  2.16 7.695 41.04 7.965 ;
     RECT  2.16 8.235 41.04 8.505 ;
     RECT  2.16 8.775 41.04 9.045 ;
     RECT  2.16 9.315 41.04 9.585 ;
     RECT  2.16 9.855 41.04 10.125 ;
     RECT  2.16 10.395 41.04 10.665 ;
     RECT  2.16 10.935 41.04 11.205 ;
     RECT  2.16 11.475 41.04 11.745 ;
     RECT  2.16 12.015 41.04 12.285 ;
     RECT  2.16 12.555 41.04 12.825 ;
     RECT  2.16 13.095 41.04 13.365 ;
     RECT  2.16 13.635 41.04 13.905 ;
     RECT  2.16 14.175 41.04 14.445 ;
     RECT  2.16 14.715 41.04 14.985 ;
     RECT  2.16 15.255 41.04 15.525 ;
     RECT  2.16 15.795 41.04 16.065 ;
     RECT  2.16 16.335 41.04 16.605 ;
     RECT  2.16 16.875 41.04 17.145 ;
     RECT  2.16 17.415 41.04 17.685 ;
     RECT  2.16 17.955 41.04 18.225 ;
     RECT  2.16 18.495 41.04 18.765 ;
     RECT  2.16 19.035 41.04 19.305 ;
     RECT  2.16 19.575 41.04 19.845 ;
     RECT  2.16 20.115 41.04 20.385 ;
     RECT  2.16 20.655 41.04 20.925 ;
     RECT  2.16 21.195 41.04 21.465 ;
     RECT  2.16 21.735 41.04 22.005 ;
     RECT  2.16 22.275 41.04 22.545 ;
     RECT  2.16 22.815 41.04 23.085 ;
     RECT  2.16 23.355 41.04 23.625 ;
     RECT  2.16 23.895 41.04 24.165 ;
     RECT  2.16 24.435 41.04 24.705 ;
     RECT  2.16 24.975 41.04 25.245 ;
     RECT  2.16 25.515 41.04 25.785 ;
     RECT  2.16 26.055 41.04 26.325 ;
     RECT  2.16 26.595 41.04 26.865 ;
     RECT  2.16 27.135 41.04 27.405 ;
     RECT  2.16 27.675 41.04 27.945 ;
     RECT  2.16 28.215 41.04 28.485 ;
     RECT  2.16 28.755 41.04 29.025 ;
     RECT  2.16 29.295 41.04 29.565 ;
     RECT  2.16 29.835 41.04 30.105 ;
     RECT  2.16 30.375 41.04 30.645 ;
     RECT  2.16 30.915 41.04 31.185 ;
     RECT  2.16 31.455 41.04 31.725 ;
     RECT  2.16 31.995 41.04 32.265 ;
     RECT  2.16 32.535 41.04 32.805 ;
     RECT  2.16 33.075 41.04 33.345 ;
     RECT  2.16 33.615 41.04 33.885 ;
     RECT  2.16 34.155 41.04 34.425 ;
     RECT  2.16 34.695 41.04 34.965 ;
     RECT  2.16 35.235 41.04 35.505 ;
     RECT  2.16 35.775 41.04 36.045 ;
     RECT  2.16 36.315 41.04 36.585 ;
     RECT  2.16 36.855 41.04 37.125 ;
     RECT  2.16 37.395 41.04 37.665 ;
     RECT  2.16 37.935 41.04 38.205 ;
     RECT  2.16 38.475 41.04 38.745 ;
     RECT  2.16 39.015 41.04 39.285 ;
     RECT  2.16 39.555 41.04 39.825 ;
     RECT  2.16 40.095 41.04 40.365 ;
     RECT  2.16 40.635 41.04 40.905 ;
    LAYER M1 ;
     RECT  2.16 2.151 41.04 41.049 ;
    LAYER M2 ;
     RECT  0.103 2.61 0.139 2.628 ;
     RECT  0.103 10.368 0.139 10.386 ;
     RECT  0.139 2.61 2.16 2.79 ;
     RECT  0.103 4.392 2.16 4.41 ;
     RECT  0.139 10.17 2.16 10.386 ;
     RECT  0.139 11.79 2.16 11.808 ;
     RECT  0.103 14.22 2.16 14.238 ;
     RECT  0.103 18.162 2.16 18.18 ;
     RECT  2.16 2.151 36.607 41.049 ;
     RECT  36.607 2.151 37.715 41.094 ;
     RECT  37.715 2.151 41.04 41.049 ;
     RECT  41.04 27.144 41.603 41.004 ;
     RECT  41.603 27.918 41.639 41.004 ;
     RECT  41.04 23.796 42.179 26.316 ;
     RECT  41.639 27.918 42.179 29.052 ;
     RECT  41.639 29.808 42.179 41.004 ;
     RECT  42.179 23.796 42.215 25.002 ;
     RECT  42.179 28.296 42.215 28.314 ;
     RECT  42.179 29.808 42.215 37.224 ;
     RECT  42.179 38.178 42.215 41.004 ;
     RECT  41.04 21.978 42.251 22.914 ;
     RECT  42.215 38.556 42.251 41.004 ;
     RECT  42.215 32.886 42.287 34.758 ;
     RECT  42.251 40.986 42.287 41.004 ;
     RECT  42.215 23.796 43.043 23.814 ;
     RECT  42.215 29.808 43.043 31.248 ;
     RECT  42.287 32.886 43.043 34.452 ;
     RECT  43.043 30.276 43.079 31.248 ;
     RECT  42.215 35.514 43.079 35.802 ;
     RECT  42.251 21.978 43.115 22.608 ;
     RECT  42.215 24.984 43.115 25.002 ;
     RECT  41.603 27.144 43.115 27.162 ;
     RECT  43.079 30.816 43.115 31.248 ;
     RECT  43.043 32.886 43.115 34.254 ;
     RECT  43.079 35.514 43.115 35.532 ;
     RECT  42.251 38.556 43.115 39.816 ;
    LAYER M3 ;
     RECT  2.415 2.143 2.505 2.263 ;
     RECT  2.304 2.263 2.505 2.413 ;
     RECT  5.115 2.143 5.205 2.413 ;
     RECT  7.815 2.143 7.905 2.413 ;
     RECT  10.515 2.143 10.605 2.413 ;
     RECT  13.215 2.143 13.305 2.413 ;
     RECT  15.915 2.143 16.005 2.413 ;
     RECT  18.615 2.143 18.705 2.413 ;
     RECT  21.315 2.143 21.405 2.413 ;
     RECT  24.015 2.143 24.105 2.413 ;
     RECT  26.715 2.143 26.805 2.413 ;
     RECT  29.415 2.143 29.505 2.413 ;
     RECT  32.115 2.143 32.205 2.413 ;
     RECT  34.815 2.143 34.905 2.413 ;
     RECT  37.515 2.143 37.605 2.413 ;
     RECT  40.215 2.143 40.305 2.413 ;
     RECT  3.456 2.371 3.474 2.461 ;
     RECT  37.515 2.413 37.797 2.461 ;
     RECT  3.456 2.461 3.69 2.605 ;
     RECT  2.304 2.413 2.697 2.641 ;
     RECT  3.42 2.605 3.69 2.641 ;
     RECT  24.015 2.413 24.297 2.731 ;
     RECT  0.108 2.605 0.126 2.767 ;
     RECT  37.515 2.461 37.926 3.001 ;
     RECT  2.304 2.641 3.69 3.181 ;
     RECT  0.108 2.767 0.162 3.197 ;
     RECT  2.304 3.181 3.906 3.415 ;
     RECT  0.144 3.197 0.162 3.485 ;
     RECT  2.304 3.415 3.942 3.569 ;
     RECT  24.015 2.731 24.894 3.811 ;
     RECT  2.304 3.569 3.906 4.531 ;
     RECT  6.804 4.261 6.822 4.559 ;
     RECT  0.108 4.387 0.126 4.637 ;
     RECT  15.915 2.413 16.197 4.891 ;
     RECT  2.304 4.531 4.05 5.161 ;
     RECT  14.4 4.387 14.418 5.161 ;
     RECT  14.4 5.161 14.85 5.197 ;
     RECT  15.915 4.891 16.686 5.197 ;
     RECT  14.4 5.197 16.686 5.297 ;
     RECT  2.304 5.161 4.374 5.305 ;
     RECT  5.115 2.413 5.397 5.305 ;
     RECT  2.304 5.305 5.397 5.495 ;
     RECT  2.415 5.495 5.397 5.701 ;
     RECT  2.415 5.701 5.562 5.741 ;
     RECT  6.84 5.161 6.858 5.909 ;
     RECT  4.68 5.741 5.562 6.269 ;
     RECT  2.415 5.741 3.942 6.277 ;
     RECT  4.68 6.269 5.49 6.305 ;
     RECT  6.948 6.235 6.966 6.385 ;
     RECT  7.815 2.413 8.097 6.385 ;
     RECT  17.532 6.241 17.55 6.511 ;
     RECT  18.615 2.413 18.897 6.511 ;
     RECT  2.34 6.277 3.942 6.583 ;
     RECT  4.68 6.305 5.397 6.583 ;
     RECT  21.315 2.413 21.597 6.781 ;
     RECT  2.34 6.583 5.397 6.808 ;
     RECT  2.304 6.808 5.397 6.845 ;
     RECT  6.948 6.385 8.097 7.087 ;
     RECT  2.415 6.845 5.397 7.115 ;
     RECT  6.84 7.087 8.097 7.123 ;
     RECT  6.84 7.123 8.406 7.229 ;
     RECT  13.215 2.413 13.497 7.231 ;
     RECT  6.84 7.229 6.858 7.259 ;
     RECT  7.815 7.229 8.406 7.349 ;
     RECT  20.916 6.781 21.597 7.591 ;
     RECT  2.415 7.115 4.374 7.627 ;
     RECT  2.304 7.627 4.374 7.897 ;
     RECT  5.115 7.115 5.397 7.897 ;
     RECT  2.304 7.897 5.397 8.395 ;
     RECT  12.708 7.231 13.497 8.401 ;
     RECT  14.4 5.297 14.418 8.401 ;
     RECT  2.304 8.395 5.634 8.465 ;
     RECT  12.708 8.401 14.418 8.941 ;
     RECT  15.192 5.297 16.686 8.941 ;
     RECT  2.34 8.465 5.634 9.355 ;
     RECT  2.304 9.355 5.634 9.499 ;
     RECT  2.304 9.499 6.318 9.545 ;
     RECT  10.515 2.413 10.797 9.931 ;
     RECT  12.708 8.941 16.686 10.129 ;
     RECT  0.108 10.123 0.126 10.165 ;
     RECT  6.696 10.129 6.714 10.201 ;
     RECT  6.696 10.201 6.822 10.267 ;
     RECT  2.304 9.545 5.634 10.435 ;
     RECT  7.815 7.349 8.097 10.471 ;
     RECT  2.268 10.435 5.634 10.697 ;
     RECT  6.696 10.267 7.002 10.741 ;
     RECT  7.815 10.471 8.298 10.741 ;
     RECT  6.228 10.741 8.298 10.859 ;
     RECT  2.268 10.697 5.49 10.877 ;
     RECT  5.115 10.877 5.49 10.895 ;
     RECT  2.268 10.877 3.978 11.435 ;
     RECT  0.108 10.165 0.162 11.645 ;
     RECT  0.144 11.645 0.162 12.427 ;
     RECT  0.108 12.427 0.162 12.557 ;
     RECT  0.144 12.557 0.162 12.749 ;
     RECT  2.304 11.435 3.834 12.991 ;
     RECT  2.304 12.991 4.014 13.003 ;
     RECT  6.804 10.859 8.298 13.261 ;
     RECT  6.804 13.261 8.946 13.531 ;
     RECT  2.268 13.003 4.014 13.595 ;
     RECT  6.804 13.531 9.018 13.837 ;
     RECT  6.804 13.837 9.234 13.909 ;
     RECT  37.515 3.001 38.286 13.909 ;
     RECT  6.768 13.909 9.234 14.009 ;
     RECT  10.08 9.931 10.797 14.071 ;
     RECT  5.115 10.895 5.397 14.179 ;
     RECT  0.108 14.215 0.126 14.429 ;
     RECT  5.115 14.179 5.778 14.485 ;
     RECT  6.804 14.009 9.234 14.611 ;
     RECT  10.08 14.071 11.43 14.611 ;
     RECT  6.804 14.611 11.43 14.881 ;
     RECT  12.708 10.129 16.794 14.881 ;
     RECT  17.532 6.511 18.897 14.881 ;
     RECT  2.304 13.595 4.014 14.989 ;
     RECT  5.115 14.485 5.814 14.989 ;
     RECT  2.304 14.989 5.814 15.089 ;
     RECT  2.304 15.089 4.194 15.997 ;
     RECT  5.115 15.089 5.814 15.997 ;
     RECT  40.215 2.413 40.497 16.105 ;
     RECT  6.804 14.881 18.897 16.141 ;
     RECT  22.644 4.081 22.662 16.141 ;
     RECT  28.224 15.997 28.242 16.141 ;
     RECT  22.644 16.141 22.806 16.259 ;
     RECT  26.715 2.413 26.997 16.267 ;
     RECT  2.304 15.997 5.814 16.363 ;
     RECT  2.268 16.363 5.814 16.403 ;
     RECT  6.804 16.141 18.918 16.411 ;
     RECT  22.644 16.259 22.77 16.501 ;
     RECT  6.804 16.411 18.954 16.555 ;
     RECT  20.34 7.591 21.597 16.771 ;
     RECT  6.804 16.555 18.99 16.807 ;
     RECT  19.764 16.771 21.597 16.807 ;
     RECT  22.5 16.501 22.77 17.141 ;
     RECT  26.028 16.267 26.997 17.221 ;
     RECT  28.224 16.141 28.458 17.491 ;
     RECT  29.415 2.413 29.697 17.491 ;
     RECT  6.804 16.807 21.597 17.653 ;
     RECT  22.572 17.141 22.77 17.689 ;
     RECT  28.224 17.491 29.697 17.689 ;
     RECT  22.572 17.689 22.842 17.725 ;
     RECT  23.688 3.811 24.894 17.725 ;
     RECT  6.804 17.653 21.69 17.887 ;
     RECT  6.804 17.887 21.762 17.915 ;
     RECT  12.96 17.915 21.762 17.995 ;
     RECT  22.572 17.725 24.894 17.995 ;
     RECT  12.96 17.995 24.894 18.059 ;
     RECT  32.115 2.413 32.397 18.301 ;
     RECT  2.304 16.403 5.814 18.331 ;
     RECT  2.268 18.331 5.814 18.527 ;
     RECT  36.36 18.499 36.378 18.571 ;
     RECT  13.215 18.059 24.894 18.661 ;
     RECT  2.304 18.527 5.814 18.725 ;
     RECT  13.215 18.661 25.254 18.805 ;
     RECT  26.028 17.221 27.27 18.805 ;
     RECT  34.815 2.413 35.097 18.805 ;
     RECT  36.36 18.571 36.45 18.805 ;
     RECT  34.815 18.805 35.154 19.309 ;
     RECT  36.36 18.805 36.486 19.309 ;
     RECT  0.108 18.157 0.126 19.325 ;
     RECT  32.115 18.301 32.598 19.345 ;
     RECT  2.415 18.725 5.814 19.483 ;
     RECT  6.804 17.915 12.078 19.615 ;
     RECT  6.804 19.615 12.474 19.651 ;
     RECT  13.215 18.805 27.27 19.651 ;
     RECT  37.515 13.909 38.502 19.849 ;
     RECT  39.564 16.105 40.497 19.849 ;
     RECT  34.815 19.309 36.486 19.885 ;
     RECT  37.515 19.849 40.497 19.885 ;
     RECT  34.815 19.885 40.497 20.047 ;
     RECT  2.304 19.483 5.814 20.191 ;
     RECT  2.304 20.191 5.85 20.345 ;
     RECT  34.815 20.047 40.806 20.389 ;
     RECT  2.415 20.345 5.85 20.429 ;
     RECT  34.776 20.389 40.806 20.489 ;
     RECT  6.804 19.651 27.27 21.001 ;
     RECT  6.804 21.001 27.378 21.199 ;
     RECT  28.224 17.689 30.402 21.199 ;
     RECT  6.804 21.199 30.402 21.271 ;
     RECT  2.415 20.429 5.814 21.695 ;
     RECT  34.815 20.489 40.806 22.081 ;
     RECT  42.192 22.351 42.21 22.876 ;
     RECT  3.636 21.695 5.814 22.919 ;
     RECT  6.768 21.271 30.402 22.981 ;
     RECT  42.192 22.876 42.246 23.069 ;
     RECT  6.732 22.981 30.402 23.117 ;
     RECT  6.768 23.117 30.402 23.125 ;
     RECT  3.636 22.919 3.654 23.153 ;
     RECT  34.815 22.081 40.95 23.161 ;
     RECT  42.192 23.069 42.21 23.227 ;
     RECT  32.115 19.345 33.318 23.431 ;
     RECT  43.092 21.973 43.11 23.453 ;
     RECT  4.5 22.919 5.814 23.729 ;
     RECT  34.776 23.161 40.95 23.803 ;
     RECT  34.776 23.803 41.022 23.863 ;
     RECT  42.156 23.227 42.21 23.863 ;
     RECT  32.115 23.431 33.894 23.971 ;
     RECT  34.776 23.863 42.21 24.029 ;
     RECT  32.115 23.971 33.93 24.061 ;
     RECT  34.776 24.029 40.95 24.061 ;
     RECT  32.115 24.061 40.95 24.205 ;
     RECT  43.02 23.791 43.038 24.221 ;
     RECT  6.768 23.125 30.942 24.241 ;
     RECT  31.788 24.205 40.95 24.241 ;
     RECT  41.832 24.029 42.21 24.467 ;
     RECT  41.832 24.467 42.174 24.503 ;
     RECT  6.768 24.241 40.95 24.809 ;
     RECT  43.092 24.955 43.11 25.007 ;
     RECT  6.768 24.809 40.878 25.085 ;
     RECT  42.12 24.503 42.174 25.579 ;
     RECT  41.832 25.579 42.174 25.789 ;
     RECT  25.776 25.085 40.878 25.853 ;
     RECT  6.768 25.085 24.93 25.861 ;
     RECT  25.776 25.853 36.774 25.861 ;
     RECT  6.768 25.861 36.774 25.979 ;
     RECT  4.86 23.729 5.814 26.221 ;
     RECT  6.768 25.979 23.166 26.221 ;
     RECT  4.86 26.221 23.166 26.285 ;
     RECT  41.616 25.789 42.174 26.321 ;
     RECT  41.616 26.321 42.138 26.573 ;
     RECT  23.904 25.979 24.642 26.761 ;
     RECT  25.74 25.979 36.666 26.761 ;
     RECT  6.768 26.285 23.166 26.779 ;
     RECT  23.904 26.761 36.666 26.779 ;
     RECT  37.515 25.853 40.878 26.797 ;
     RECT  37.515 26.797 41.598 26.941 ;
     RECT  43.092 26.731 43.11 27.167 ;
     RECT  6.768 26.779 36.666 27.259 ;
     RECT  37.44 26.941 41.598 27.307 ;
     RECT  6.696 27.259 36.666 27.841 ;
     RECT  37.44 27.307 42.174 27.841 ;
     RECT  6.696 27.841 42.174 27.869 ;
     RECT  6.768 27.869 42.174 28.291 ;
     RECT  6.768 28.291 42.21 28.445 ;
     RECT  37.44 28.445 42.21 28.493 ;
     RECT  6.768 28.445 36.702 28.589 ;
     RECT  37.44 28.493 42.174 28.823 ;
     RECT  43.02 28.075 43.038 28.843 ;
     RECT  4.86 26.285 5.814 28.859 ;
     RECT  42.948 28.843 43.038 29.419 ;
     RECT  7.164 28.589 36.702 29.533 ;
     RECT  37.44 28.823 40.878 29.533 ;
     RECT  41.868 28.823 42.174 29.731 ;
     RECT  7.164 29.533 40.878 29.875 ;
     RECT  41.616 29.731 42.174 29.875 ;
     RECT  7.164 29.875 42.174 30.109 ;
     RECT  42.948 29.419 43.11 30.109 ;
     RECT  7.164 30.109 43.11 30.269 ;
     RECT  41.868 30.269 43.11 30.443 ;
     RECT  41.904 30.443 43.11 30.794 ;
     RECT  41.904 30.794 42.246 30.845 ;
     RECT  43.02 30.794 43.11 30.911 ;
     RECT  41.904 30.845 42.21 30.983 ;
     RECT  7.164 30.269 41.058 31.421 ;
     RECT  43.092 30.911 43.11 31.613 ;
     RECT  42.192 30.983 42.21 31.729 ;
     RECT  42.156 31.729 42.21 32.155 ;
     RECT  7.164 31.421 40.698 32.269 ;
     RECT  7.164 32.269 40.806 32.305 ;
     RECT  41.58 32.155 42.21 32.305 ;
     RECT  7.164 32.305 42.21 32.369 ;
     RECT  7.164 32.369 41.058 32.381 ;
     RECT  7.164 32.381 40.806 32.459 ;
     RECT  43.092 32.539 43.11 32.908 ;
     RECT  7.164 32.459 40.77 32.999 ;
     RECT  43.056 32.908 43.11 33.071 ;
     RECT  42.192 32.369 42.21 33.115 ;
     RECT  41.58 33.115 42.21 33.307 ;
     RECT  5.115 28.859 5.814 33.377 ;
     RECT  41.544 33.307 42.21 33.377 ;
     RECT  7.164 32.999 40.698 33.449 ;
     RECT  41.58 33.377 42.21 33.449 ;
     RECT  7.524 33.449 40.698 33.781 ;
     RECT  42.156 33.449 42.21 33.989 ;
     RECT  7.524 33.781 40.734 34.115 ;
     RECT  43.092 33.071 43.11 34.301 ;
     RECT  43.02 34.429 43.038 34.493 ;
     RECT  15.048 34.115 40.734 34.591 ;
     RECT  42.192 33.989 42.21 34.735 ;
     RECT  15.048 34.591 40.986 34.771 ;
     RECT  42.192 34.735 42.282 34.771 ;
     RECT  15.048 34.771 42.282 34.877 ;
     RECT  7.524 34.115 14.238 35.041 ;
     RECT  15.048 34.877 40.914 35.041 ;
     RECT  43.092 35.083 43.11 35.275 ;
     RECT  7.524 35.041 40.914 35.311 ;
     RECT  7.344 35.311 40.914 35.357 ;
     RECT  7.56 35.357 40.914 35.501 ;
     RECT  43.056 35.275 43.11 35.537 ;
     RECT  42.192 34.877 42.282 35.693 ;
     RECT  7.56 35.501 40.734 35.735 ;
     RECT  43.056 35.537 43.074 35.743 ;
     RECT  43.02 35.743 43.074 35.807 ;
     RECT  42.192 35.693 42.21 36.043 ;
     RECT  42.156 36.043 42.21 36.239 ;
     RECT  43.02 35.807 43.038 36.269 ;
     RECT  7.704 35.735 40.734 36.275 ;
     RECT  7.815 36.275 40.734 36.283 ;
     RECT  42.948 36.283 42.966 36.461 ;
     RECT  7.815 36.283 41.022 36.779 ;
     RECT  36.324 36.779 41.022 36.845 ;
     RECT  42.192 36.239 42.21 37.195 ;
     RECT  7.815 36.779 35.586 37.319 ;
     RECT  42.156 37.195 42.21 37.421 ;
     RECT  9.432 37.319 35.586 37.589 ;
     RECT  36.324 36.845 40.698 37.589 ;
     RECT  9.432 37.589 11.178 37.625 ;
     RECT  12.024 37.589 35.586 37.625 ;
     RECT  14.724 37.625 35.586 37.661 ;
     RECT  15.012 37.661 35.586 37.733 ;
     RECT  17.244 37.733 35.586 37.741 ;
     RECT  36.324 37.589 40.626 37.741 ;
     RECT  12.024 37.625 13.95 37.859 ;
     RECT  12.024 37.859 13.497 37.895 ;
     RECT  10.26 37.625 10.797 37.967 ;
     RECT  12.024 37.895 12.042 37.967 ;
     RECT  42.156 37.421 42.174 37.967 ;
     RECT  15.012 37.733 16.326 38.039 ;
     RECT  15.012 38.039 16.197 38.443 ;
     RECT  17.244 37.741 40.626 38.479 ;
     RECT  14.832 38.443 16.197 38.507 ;
     RECT  14.832 38.507 15.138 38.579 ;
     RECT  43.092 38.539 43.11 38.749 ;
     RECT  43.02 38.749 43.11 38.813 ;
     RECT  12.78 37.895 13.497 38.849 ;
     RECT  42.192 38.173 42.21 38.923 ;
     RECT  17.244 38.479 40.734 38.975 ;
     RECT  17.28 38.975 40.734 39.253 ;
     RECT  15.048 38.579 15.138 39.389 ;
     RECT  43.092 38.813 43.11 39.739 ;
     RECT  43.02 39.739 43.11 39.821 ;
     RECT  17.28 39.253 40.806 39.865 ;
     RECT  43.02 39.821 43.038 39.965 ;
     RECT  17.28 39.865 41.022 40.091 ;
     RECT  18.504 40.091 41.022 40.123 ;
     RECT  42.192 38.923 42.246 40.123 ;
     RECT  18.504 40.123 42.246 40.163 ;
     RECT  15.915 38.507 16.197 40.171 ;
     RECT  17.28 40.091 17.658 40.171 ;
     RECT  15.915 40.171 17.658 40.289 ;
     RECT  18.504 40.163 41.022 40.289 ;
     RECT  42.192 40.163 42.246 40.315 ;
     RECT  18.504 40.289 35.766 40.403 ;
     RECT  15.12 39.389 15.138 40.433 ;
     RECT  18.504 40.403 32.85 40.469 ;
     RECT  42.192 40.315 42.282 40.541 ;
     RECT  17.496 40.289 17.658 40.559 ;
     RECT  18.576 40.469 32.85 40.559 ;
     RECT  26.316 40.559 28.638 40.595 ;
     RECT  29.415 40.559 32.85 40.631 ;
     RECT  26.316 40.595 28.53 40.667 ;
     RECT  18.576 40.559 25.146 40.703 ;
     RECT  36.612 40.289 41.022 40.733 ;
     RECT  2.415 21.695 2.697 40.787 ;
     RECT  5.115 33.377 5.397 40.787 ;
     RECT  7.815 37.319 8.097 40.787 ;
     RECT  10.515 37.967 10.797 40.787 ;
     RECT  13.215 38.849 13.497 40.787 ;
     RECT  15.915 40.289 16.197 40.787 ;
     RECT  18.612 40.703 25.146 40.787 ;
     RECT  24.912 40.787 25.146 40.829 ;
     RECT  26.316 40.667 28.422 40.829 ;
     RECT  29.415 40.631 30.51 40.829 ;
     RECT  31.284 40.631 32.85 40.829 ;
     RECT  33.588 40.403 35.766 40.829 ;
     RECT  36.612 40.733 40.59 40.829 ;
     RECT  26.676 40.829 28.422 40.865 ;
     RECT  33.732 40.829 35.046 40.877 ;
     RECT  26.676 40.865 26.805 40.901 ;
     RECT  38.808 40.829 40.59 40.901 ;
     RECT  38.844 40.901 40.59 40.925 ;
     RECT  18.612 40.787 24.105 40.937 ;
     RECT  29.415 40.829 29.79 40.937 ;
     RECT  37.44 40.829 37.998 40.937 ;
     RECT  25.128 40.829 25.146 40.973 ;
     RECT  32.115 40.829 32.67 40.973 ;
     RECT  37.44 40.937 37.71 40.973 ;
     RECT  38.844 40.925 40.305 40.973 ;
     RECT  18.615 40.937 18.774 41.009 ;
     RECT  20.232 40.937 24.105 41.009 ;
     RECT  27.828 40.865 28.422 41.009 ;
     RECT  34.308 40.877 35.046 41.009 ;
     RECT  38.844 40.973 38.862 41.009 ;
     RECT  42.264 40.541 42.282 41.009 ;
     RECT  20.232 41.009 22.77 41.021 ;
     RECT  34.308 41.009 34.905 41.021 ;
     RECT  2.415 40.787 2.505 41.057 ;
     RECT  5.115 40.787 5.205 41.057 ;
     RECT  7.815 40.787 7.905 41.057 ;
     RECT  10.515 40.787 10.605 41.057 ;
     RECT  13.215 40.787 13.305 41.057 ;
     RECT  15.915 40.787 16.005 41.057 ;
     RECT  18.615 41.009 18.705 41.057 ;
     RECT  24.015 41.009 24.105 41.057 ;
     RECT  26.715 40.901 26.805 41.057 ;
     RECT  29.415 40.937 29.505 41.057 ;
     RECT  32.115 40.973 32.205 41.057 ;
     RECT  34.815 41.021 34.905 41.057 ;
     RECT  37.515 40.973 37.71 41.057 ;
     RECT  40.215 40.973 40.305 41.057 ;
     RECT  36.612 40.829 36.63 41.099 ;
     RECT  37.692 41.057 37.71 41.099 ;
     RECT  20.916 41.021 22.122 41.645 ;
     RECT  20.916 41.645 20.934 42.221 ;
    LAYER M4 ;
     RECT  0.06 3.168 0.137 20.328 ;
     RECT  0.137 3.456 0.173 20.328 ;
     RECT  0.173 3.744 2.408 20.328 ;
     RECT  2.408 2.148 2.512 41.052 ;
     RECT  2.512 2.418 2.704 40.782 ;
     RECT  2.704 5.184 2.765 7.128 ;
     RECT  2.704 19.296 2.765 20.328 ;
     RECT  2.704 8.496 2.873 9.096 ;
     RECT  2.873 9.072 2.909 9.096 ;
     RECT  2.704 10.128 3.017 10.152 ;
     RECT  2.704 14.688 3.017 14.712 ;
     RECT  2.765 19.296 3.017 19.944 ;
     RECT  2.704 13.056 3.557 13.08 ;
     RECT  3.017 19.92 3.877 19.944 ;
     RECT  3.877 19.92 3.913 20.856 ;
     RECT  2.765 5.184 3.917 5.736 ;
     RECT  3.913 19.92 3.923 21.144 ;
     RECT  4.201 7.44 4.489 7.464 ;
     RECT  4.489 7.44 4.561 7.944 ;
     RECT  2.704 16.08 4.597 16.584 ;
     RECT  3.917 5.712 4.669 5.736 ;
     RECT  4.561 6.816 4.669 7.944 ;
     RECT  4.669 5.712 5.108 7.944 ;
     RECT  4.559 9.744 5.108 9.768 ;
     RECT  3.697 10.848 5.108 10.872 ;
     RECT  4.597 16.08 5.108 16.824 ;
     RECT  2.704 18.192 5.108 18.264 ;
     RECT  3.923 20.4 5.108 21.144 ;
     RECT  5.108 2.148 5.212 41.052 ;
     RECT  5.212 2.418 5.404 40.782 ;
     RECT  5.404 6.24 5.651 6.84 ;
     RECT  5.404 7.92 5.651 8.424 ;
     RECT  5.404 20.4 5.861 21.144 ;
     RECT  5.404 9.504 6.329 10.296 ;
     RECT  5.404 26.256 6.937 26.28 ;
     RECT  5.651 6.24 7.153 6.264 ;
     RECT  6.685 27.264 7.261 27.288 ;
     RECT  7.333 35.328 7.429 35.352 ;
     RECT  7.261 27.264 7.585 28.2 ;
     RECT  7.153 6.24 7.808 7.224 ;
     RECT  6.329 10.272 7.808 10.296 ;
     RECT  5.404 16.8 7.808 16.824 ;
     RECT  5.861 21.12 7.808 21.144 ;
     RECT  6.937 25.632 7.808 26.28 ;
     RECT  7.585 27.264 7.808 28.968 ;
     RECT  7.333 33.024 7.808 33.048 ;
     RECT  7.429 35.328 7.808 35.832 ;
     RECT  7.808 2.148 7.912 41.052 ;
     RECT  7.912 2.418 8.104 40.782 ;
     RECT  8.104 31.344 8.243 32.04 ;
     RECT  8.104 33.024 8.243 34.248 ;
     RECT  8.104 7.2 8.273 7.224 ;
     RECT  8.104 28.128 8.387 29.208 ;
     RECT  8.243 33.216 8.561 34.248 ;
     RECT  8.104 23.52 8.579 25.08 ;
     RECT  8.561 33.648 8.777 34.248 ;
     RECT  8.387 28.224 8.849 29.208 ;
     RECT  8.104 26.064 9.169 26.232 ;
     RECT  8.579 25.056 9.173 25.08 ;
     RECT  8.104 35.808 9.241 35.88 ;
     RECT  8.104 21.12 9.277 22.056 ;
     RECT  8.579 23.52 9.277 23.976 ;
     RECT  9.277 21.12 9.385 23.976 ;
     RECT  8.777 34.224 9.385 34.248 ;
     RECT  9.241 35.424 9.385 35.88 ;
     RECT  8.104 37.104 9.601 37.128 ;
     RECT  9.385 34.224 10.033 35.88 ;
     RECT  10.033 33.888 10.141 35.88 ;
     RECT  8.849 28.224 10.177 28.248 ;
     RECT  8.243 31.344 10.177 31.368 ;
     RECT  10.177 28.224 10.357 28.44 ;
     RECT  10.177 31.344 10.357 31.512 ;
     RECT  10.141 33.024 10.357 35.88 ;
     RECT  9.385 20.352 10.465 23.976 ;
     RECT  8.104 16.8 10.508 16.824 ;
     RECT  10.465 19.872 10.508 23.976 ;
     RECT  9.169 26.064 10.508 26.328 ;
     RECT  10.357 28.224 10.508 28.536 ;
     RECT  10.357 30.72 10.508 35.88 ;
     RECT  9.601 37.056 10.508 37.128 ;
     RECT  10.508 2.148 10.612 41.052 ;
     RECT  10.612 2.418 10.804 40.782 ;
     RECT  10.804 16.8 10.931 16.824 ;
     RECT  10.804 19.872 11.117 23.688 ;
     RECT  11.117 19.872 11.333 21.528 ;
     RECT  10.804 32.448 11.411 35.448 ;
     RECT  11.411 32.832 11.549 33.528 ;
     RECT  11.117 22.848 11.585 23.688 ;
     RECT  10.804 27.984 11.729 28.536 ;
     RECT  10.804 29.664 12.017 29.88 ;
     RECT  11.729 27.984 12.233 28.488 ;
     RECT  11.585 22.944 12.337 23.688 ;
     RECT  11.411 34.704 12.337 35.448 ;
     RECT  10.804 36.528 12.337 37.368 ;
     RECT  11.333 20.064 12.445 21.528 ;
     RECT  11.549 32.832 12.517 32.856 ;
     RECT  12.337 34.704 12.517 37.368 ;
     RECT  10.804 26.064 12.697 26.568 ;
     RECT  12.337 22.944 12.769 24.648 ;
     RECT  12.445 19.632 12.841 21.528 ;
     RECT  12.769 22.944 12.877 25.08 ;
     RECT  12.233 27.984 12.877 28.248 ;
     RECT  12.841 19.632 12.949 21.912 ;
     RECT  12.877 22.896 12.949 25.08 ;
     RECT  12.337 31.296 12.985 31.32 ;
     RECT  12.877 27.936 13.121 28.248 ;
     RECT  12.949 19.632 13.208 25.08 ;
     RECT  12.697 26.064 13.208 26.616 ;
     RECT  13.121 27.888 13.208 28.248 ;
     RECT  12.017 29.664 13.208 29.688 ;
     RECT  12.985 30.912 13.208 31.32 ;
     RECT  12.517 32.832 13.208 33.624 ;
     RECT  12.517 34.704 13.208 37.608 ;
     RECT  13.208 2.148 13.312 41.052 ;
     RECT  13.312 2.418 13.504 40.782 ;
     RECT  13.504 26.352 13.66 26.712 ;
     RECT  13.504 19.632 13.673 24.648 ;
     RECT  13.66 26.352 13.701 26.616 ;
     RECT  13.504 30.144 13.745 31.224 ;
     RECT  13.504 32.4 14.099 33.912 ;
     RECT  13.673 19.632 14.321 21.96 ;
     RECT  13.504 35.088 14.483 35.88 ;
     RECT  14.483 35.424 14.524 35.88 ;
     RECT  13.673 23.04 14.537 24.648 ;
     RECT  14.537 23.136 14.569 24.648 ;
     RECT  14.569 23.136 14.573 25.08 ;
     RECT  14.573 23.376 14.789 25.08 ;
     RECT  13.701 26.352 14.929 26.568 ;
     RECT  14.099 32.4 15.073 32.856 ;
     RECT  14.099 33.888 15.073 33.912 ;
     RECT  15.068 18.576 15.109 18.6 ;
     RECT  14.321 19.632 15.109 20.616 ;
     RECT  15.073 27.936 15.253 27.96 ;
     RECT  15.073 32.4 15.253 33.912 ;
     RECT  13.745 30.912 15.397 31.224 ;
     RECT  15.253 32.4 15.397 34.392 ;
     RECT  13.504 37.584 15.397 37.608 ;
     RECT  15.253 27.888 15.541 27.96 ;
     RECT  14.677 29.616 15.541 29.64 ;
     RECT  15.397 30.72 15.541 34.392 ;
     RECT  15.541 27.888 15.685 34.392 ;
     RECT  14.524 35.424 15.685 35.448 ;
     RECT  14.929 25.728 15.721 26.568 ;
     RECT  14.789 23.376 15.757 24.648 ;
     RECT  15.721 25.728 15.757 26.904 ;
     RECT  14.321 21.744 15.829 21.96 ;
     RECT  15.109 18.576 15.865 20.616 ;
     RECT  15.865 17.952 15.908 20.616 ;
     RECT  15.829 21.696 15.908 21.96 ;
     RECT  15.757 23.376 15.908 26.904 ;
     RECT  15.685 27.888 15.908 35.448 ;
     RECT  15.289 36.48 15.908 36.504 ;
     RECT  15.397 37.584 15.908 37.656 ;
     RECT  15.908 2.148 16.012 41.052 ;
     RECT  16.012 2.418 16.204 40.782 ;
     RECT  16.204 37.632 16.337 37.656 ;
     RECT  16.204 19.536 16.355 25.752 ;
     RECT  16.204 27.888 16.445 35.544 ;
     RECT  16.204 17.568 17.221 18.216 ;
     RECT  16.355 19.536 17.221 24.696 ;
     RECT  17.221 17.568 17.377 24.696 ;
     RECT  16.445 27.888 17.377 29.304 ;
     RECT  16.445 30.72 17.629 35.544 ;
     RECT  17.629 30.72 17.653 35.832 ;
     RECT  17.653 30.72 18.169 36.744 ;
     RECT  17.341 37.872 18.169 37.896 ;
     RECT  17.377 27.792 18.241 29.304 ;
     RECT  18.241 27.12 18.277 29.304 ;
     RECT  18.169 30.72 18.277 37.896 ;
     RECT  17.377 17.568 18.385 24.744 ;
     RECT  16.355 25.728 18.385 25.752 ;
     RECT  17.845 16.56 18.469 16.584 ;
     RECT  18.385 17.568 18.469 25.752 ;
     RECT  18.469 16.56 18.608 25.752 ;
     RECT  18.277 27.12 18.608 37.896 ;
     RECT  18.608 2.148 18.712 41.052 ;
     RECT  18.712 2.418 18.904 40.782 ;
     RECT  18.904 16.56 18.965 30.936 ;
     RECT  18.965 16.56 19.001 27.192 ;
     RECT  18.965 28.176 19.109 30.936 ;
     RECT  19.001 17.904 19.217 27.192 ;
     RECT  19.109 28.752 19.757 30.936 ;
     RECT  18.904 34.416 19.793 37.128 ;
     RECT  18.904 39.888 19.873 40.584 ;
     RECT  18.904 31.92 20.113 33.384 ;
     RECT  19.793 34.416 20.113 36.552 ;
     RECT  19.757 30.912 20.221 30.936 ;
     RECT  20.113 31.92 20.221 36.552 ;
     RECT  19.873 40.56 20.221 40.584 ;
     RECT  19.217 26.784 20.401 27.192 ;
     RECT  19.217 17.904 20.545 25.752 ;
     RECT  20.401 26.784 20.545 27.576 ;
     RECT  21.013 37.872 21.157 37.896 ;
     RECT  20.905 42.192 21.251 42.216 ;
     RECT  19.001 16.56 21.308 16.584 ;
     RECT  20.545 17.904 21.308 27.576 ;
     RECT  19.757 28.752 21.308 29.88 ;
     RECT  20.221 30.912 21.308 36.552 ;
     RECT  21.157 37.872 21.308 38.808 ;
     RECT  20.221 40.56 21.308 41.016 ;
     RECT  21.308 2.148 21.412 41.052 ;
     RECT  21.412 2.418 21.445 41.052 ;
     RECT  21.445 2.418 21.604 41.64 ;
     RECT  21.604 17.904 21.773 19.896 ;
     RECT  21.604 20.88 21.773 33.048 ;
     RECT  21.773 28.08 21.809 33.048 ;
     RECT  21.773 18 21.917 19.896 ;
     RECT  21.604 37.632 21.971 41.64 ;
     RECT  21.971 37.872 22.133 41.64 ;
     RECT  22.133 38.112 22.259 41.64 ;
     RECT  21.809 28.128 22.313 33.048 ;
     RECT  21.917 18 22.349 18.264 ;
     RECT  21.773 20.88 22.421 27.096 ;
     RECT  22.421 24.864 22.637 27.096 ;
     RECT  21.604 34.416 22.637 36.36 ;
     RECT  21.917 19.632 22.669 19.896 ;
     RECT  22.421 20.88 22.669 23.88 ;
     RECT  22.637 34.416 22.741 35.352 ;
     RECT  22.259 38.112 22.787 41.016 ;
     RECT  22.669 19.632 22.853 23.88 ;
     RECT  22.349 18.24 22.885 18.264 ;
     RECT  22.853 19.632 22.885 23.736 ;
     RECT  22.637 25.44 22.885 27.096 ;
     RECT  22.885 18.24 22.889 23.736 ;
     RECT  22.885 25.44 22.889 27.24 ;
     RECT  22.787 38.112 22.961 40.632 ;
     RECT  22.889 26.736 23.033 27.24 ;
     RECT  22.313 28.464 23.317 33.048 ;
     RECT  22.741 34.368 23.317 35.352 ;
     RECT  23.317 28.464 23.821 35.352 ;
     RECT  22.637 36.336 23.821 36.36 ;
     RECT  22.889 25.44 23.857 25.608 ;
     RECT  22.889 18.24 24.008 23.688 ;
     RECT  23.857 25.44 24.008 25.8 ;
     RECT  23.033 26.784 24.008 27.24 ;
     RECT  23.821 28.464 24.008 36.36 ;
     RECT  22.961 38.112 24.008 40.584 ;
     RECT  24.008 2.148 24.112 41.052 ;
     RECT  24.112 2.418 24.304 40.782 ;
     RECT  24.304 29.04 24.419 37.464 ;
     RECT  24.304 18.72 24.509 25.8 ;
     RECT  24.304 38.544 24.563 40.584 ;
     RECT  24.304 26.784 24.617 27.096 ;
     RECT  24.419 29.04 24.653 36.984 ;
     RECT  24.617 26.88 24.725 27.096 ;
     RECT  24.653 29.328 24.761 36.984 ;
     RECT  24.761 36.96 24.833 36.984 ;
     RECT  24.761 29.328 24.851 35.832 ;
     RECT  24.851 29.328 24.892 29.352 ;
     RECT  24.563 40.56 25.013 40.584 ;
     RECT  24.851 30.336 25.157 35.832 ;
     RECT  24.563 38.544 25.157 39.48 ;
     RECT  25.157 38.64 25.229 39.48 ;
     RECT  24.509 18.768 25.235 25.8 ;
     RECT  25.235 18.768 25.331 24.552 ;
     RECT  25.331 18.816 25.372 24.552 ;
     RECT  24.725 27.072 25.429 27.096 ;
     RECT  25.369 28.128 25.429 28.152 ;
     RECT  25.157 30.336 25.445 35.544 ;
     RECT  25.429 27.072 25.661 28.152 ;
     RECT  25.657 37.296 25.871 37.32 ;
     RECT  25.871 37.296 26.341 37.656 ;
     RECT  25.229 38.64 26.341 39.24 ;
     RECT  25.445 35.232 26.449 35.544 ;
     RECT  26.341 37.296 26.557 39.24 ;
     RECT  26.485 40.368 26.557 40.392 ;
     RECT  25.372 18.816 26.708 18.84 ;
     RECT  25.372 20.208 26.708 24.552 ;
     RECT  25.235 25.68 26.708 25.8 ;
     RECT  25.661 27.072 26.708 27.096 ;
     RECT  25.661 28.128 26.708 28.152 ;
     RECT  25.445 30.336 26.708 33.672 ;
     RECT  26.449 34.992 26.708 35.544 ;
     RECT  26.557 37.296 26.708 40.392 ;
     RECT  26.708 2.148 26.812 41.052 ;
     RECT  26.812 2.418 27.004 40.782 ;
     RECT  27.004 32.496 27.497 35.544 ;
     RECT  27.004 25.632 27.749 28.008 ;
     RECT  27.004 29.472 27.973 29.496 ;
     RECT  27.004 30.864 27.973 30.984 ;
     RECT  27.004 37.584 27.973 39.24 ;
     RECT  27.497 32.592 28.141 35.544 ;
     RECT  28.141 32.592 28.181 35.688 ;
     RECT  27.973 29.472 28.249 30.984 ;
     RECT  27.004 24.192 28.285 24.36 ;
     RECT  27.749 25.632 28.285 27.096 ;
     RECT  28.105 23.088 28.361 23.112 ;
     RECT  28.181 34.416 28.453 35.688 ;
     RECT  27.973 36.672 28.453 39.24 ;
     RECT  28.249 29.088 28.501 30.984 ;
     RECT  28.181 32.592 28.501 33.384 ;
     RECT  28.285 24.192 29.005 27.096 ;
     RECT  28.501 29.088 29.149 33.384 ;
     RECT  28.453 34.416 29.149 39.24 ;
     RECT  29.005 24 29.269 27.096 ;
     RECT  27.004 21.696 29.408 22.008 ;
     RECT  29.269 24 29.408 27.864 ;
     RECT  29.149 29.088 29.408 39.24 ;
     RECT  27.004 40.272 29.408 40.584 ;
     RECT  29.408 2.148 29.512 41.052 ;
     RECT  29.512 2.418 29.704 40.782 ;
     RECT  29.704 39.504 29.765 40.344 ;
     RECT  29.704 25.776 29.981 27.192 ;
     RECT  29.765 39.504 30.089 39.528 ;
     RECT  29.704 30.288 30.197 37.992 ;
     RECT  29.981 26.64 30.305 27.192 ;
     RECT  29.704 24.48 30.805 24.504 ;
     RECT  29.704 29.232 30.805 29.256 ;
     RECT  30.805 24.48 30.845 25.272 ;
     RECT  30.697 39.312 30.845 39.336 ;
     RECT  30.197 30.288 31.097 37.896 ;
     RECT  30.805 28.992 31.309 29.256 ;
     RECT  31.097 30.288 31.309 35.256 ;
     RECT  30.305 26.736 31.333 27.192 ;
     RECT  30.845 25.248 31.669 25.272 ;
     RECT  31.333 26.736 31.669 27.912 ;
     RECT  29.704 21.696 32.108 22.008 ;
     RECT  31.669 25.248 32.108 27.912 ;
     RECT  31.309 28.992 32.108 35.256 ;
     RECT  31.097 36.288 32.108 37.896 ;
     RECT  32.108 2.148 32.212 41.052 ;
     RECT  32.212 2.418 32.404 40.872 ;
     RECT  32.404 25.248 32.537 29.592 ;
     RECT  32.537 25.824 32.867 29.592 ;
     RECT  32.404 30.624 33.011 34.872 ;
     RECT  32.404 35.952 33.011 38.088 ;
     RECT  32.867 25.824 33.041 27.912 ;
     RECT  32.404 40.368 33.077 40.872 ;
     RECT  33.011 36.48 33.148 38.088 ;
     RECT  33.148 36.48 33.185 37.896 ;
     RECT  33.185 36.48 33.293 36.504 ;
     RECT  32.404 39.216 33.437 39.336 ;
     RECT  32.867 29.376 33.649 29.592 ;
     RECT  33.011 30.624 33.649 34.44 ;
     RECT  33.541 24.48 33.937 24.504 ;
     RECT  33.649 29.376 34.117 34.44 ;
     RECT  33.041 25.824 34.153 27.72 ;
     RECT  34.117 29.04 34.153 34.44 ;
     RECT  33.077 40.56 34.297 40.872 ;
     RECT  32.404 21.696 34.808 22.008 ;
     RECT  33.937 24.48 34.808 24.696 ;
     RECT  34.153 25.824 34.808 34.44 ;
     RECT  33.185 37.584 34.808 37.896 ;
     RECT  33.437 39.216 34.808 39.24 ;
     RECT  34.297 40.56 34.808 41.016 ;
     RECT  34.808 2.148 34.912 41.052 ;
     RECT  34.912 2.418 35.104 40.782 ;
     RECT  35.104 27.168 35.417 33.528 ;
     RECT  35.104 34.608 35.597 34.728 ;
     RECT  35.417 28.272 35.669 33.528 ;
     RECT  35.597 34.704 35.777 34.728 ;
     RECT  35.669 33.504 35.805 33.528 ;
     RECT  35.669 28.272 35.939 31.896 ;
     RECT  35.104 25.824 35.957 26.136 ;
     RECT  35.957 26.112 35.993 26.136 ;
     RECT  35.939 28.272 36.029 28.296 ;
     RECT  35.939 29.472 36.065 31.896 ;
     RECT  35.104 24.096 36.173 24.504 ;
     RECT  35.104 37.872 36.205 37.896 ;
     RECT  36.065 29.472 36.281 31.464 ;
     RECT  35.417 27.168 36.385 27.192 ;
     RECT  36.281 31.44 36.533 31.464 ;
     RECT  36.205 37.872 36.601 38.664 ;
     RECT  36.601 37.872 36.745 38.76 ;
     RECT  35.104 40.272 36.745 40.296 ;
     RECT  36.169 35.136 36.817 35.16 ;
     RECT  35.104 36.576 36.997 36.6 ;
     RECT  36.817 34.944 37.249 35.16 ;
     RECT  37.249 34.464 37.381 35.16 ;
     RECT  36.997 36.288 37.381 36.6 ;
     RECT  36.173 24.48 37.429 24.504 ;
     RECT  36.745 37.872 37.429 40.296 ;
     RECT  35.104 21.696 37.508 22.008 ;
     RECT  37.429 24.384 37.508 24.504 ;
     RECT  37.357 25.824 37.508 25.848 ;
     RECT  36.385 27.12 37.508 27.192 ;
     RECT  36.281 29.472 37.508 30.072 ;
     RECT  37.381 34.464 37.508 36.6 ;
     RECT  37.429 37.872 37.508 40.968 ;
     RECT  37.508 2.148 37.612 41.052 ;
     RECT  37.612 2.418 37.804 40.968 ;
     RECT  37.804 30.048 37.901 31.896 ;
     RECT  37.804 34.704 38.477 40.968 ;
     RECT  37.804 21.648 38.869 29.016 ;
     RECT  38.477 34.704 38.981 39.768 ;
     RECT  38.477 40.896 39.017 40.968 ;
     RECT  38.981 34.944 39.161 39.768 ;
     RECT  37.804 33.552 39.197 33.72 ;
     RECT  38.869 21.36 39.445 29.016 ;
     RECT  37.901 30.384 39.445 31.896 ;
     RECT  39.445 21.36 40.208 31.896 ;
     RECT  39.197 33.552 40.208 33.624 ;
     RECT  39.161 35.808 40.208 39.768 ;
     RECT  39.017 40.944 40.208 40.968 ;
     RECT  40.208 2.148 40.312 41.052 ;
     RECT  40.312 2.418 40.504 40.92 ;
     RECT  40.504 21.936 40.601 23.832 ;
     RECT  40.504 24.912 40.601 25.32 ;
     RECT  40.601 24.912 40.637 24.936 ;
     RECT  40.601 22.032 40.673 23.832 ;
     RECT  40.673 22.08 40.853 23.832 ;
     RECT  40.504 31.392 41.533 32.376 ;
     RECT  40.504 27.12 41.569 27.912 ;
     RECT  40.853 23.808 41.605 23.832 ;
     RECT  41.569 26.928 41.605 28.68 ;
     RECT  41.605 23.808 41.821 24.024 ;
     RECT  41.605 25.968 41.821 28.68 ;
     RECT  41.821 25.584 41.857 28.68 ;
     RECT  41.857 25.584 41.893 29.256 ;
     RECT  41.605 30.24 41.893 30.264 ;
     RECT  41.821 23.808 42.109 24.408 ;
     RECT  41.893 25.584 42.109 30.264 ;
     RECT  40.853 22.08 42.145 22.68 ;
     RECT  42.109 23.808 42.145 30.264 ;
     RECT  41.533 31.392 42.145 33.336 ;
     RECT  41.605 34.848 42.145 34.872 ;
     RECT  40.504 36.288 42.145 40.92 ;
     RECT  42.145 22.08 42.181 30.264 ;
     RECT  42.145 31.392 42.181 34.872 ;
     RECT  42.145 36.048 42.181 40.92 ;
     RECT  42.181 22.08 43.164 40.92 ;
    LAYER M5 ;
     RECT  2.4 2.137 2.52 2.151 ;
     RECT  5.1 2.137 5.22 2.151 ;
     RECT  7.8 2.137 7.92 2.151 ;
     RECT  10.5 2.137 10.62 2.151 ;
     RECT  13.2 2.137 13.32 2.151 ;
     RECT  15.9 2.137 16.02 2.151 ;
     RECT  18.6 2.137 18.72 2.151 ;
     RECT  21.3 2.137 21.42 2.151 ;
     RECT  24 2.137 24.12 2.151 ;
     RECT  26.7 2.137 26.82 2.151 ;
     RECT  29.4 2.137 29.52 2.151 ;
     RECT  32.1 2.137 32.22 2.151 ;
     RECT  34.8 2.137 34.92 2.151 ;
     RECT  37.5 2.137 37.62 2.151 ;
     RECT  40.2 2.137 40.32 2.151 ;
     RECT  5.1 2.151 5.412 5.701 ;
     RECT  4.224 5.701 5.412 6.805 ;
     RECT  4.224 6.805 5.64 7.475 ;
     RECT  4.704 7.475 5.64 8.435 ;
     RECT  4.704 8.435 5.412 9.733 ;
     RECT  18.6 2.151 18.912 16.549 ;
     RECT  10.5 2.151 10.812 16.789 ;
     RECT  4.608 9.733 5.412 16.835 ;
     RECT  15.9 2.151 16.212 18.565 ;
     RECT  18.48 16.549 18.912 18.709 ;
     RECT  17.616 18.709 18.912 18.949 ;
     RECT  15.12 18.565 16.212 19.379 ;
     RECT  13.2 2.151 13.512 19.621 ;
     RECT  21.3 2.151 21.612 19.669 ;
     RECT  13.104 19.621 13.512 20.723 ;
     RECT  21.3 19.669 22.152 20.725 ;
     RECT  3.888 19.909 3.912 20.867 ;
     RECT  17.232 18.949 18.912 20.867 ;
     RECT  10.5 16.789 10.92 21.539 ;
     RECT  21.3 20.725 22.824 21.731 ;
     RECT  17.232 20.867 17.256 21.779 ;
     RECT  15.9 19.379 16.212 21.829 ;
     RECT  13.2 20.723 13.512 21.925 ;
     RECT  7.8 2.151 8.112 22.021 ;
     RECT  12.96 21.925 13.512 22.165 ;
     RECT  22.8 21.731 22.824 22.211 ;
     RECT  18.48 20.867 18.912 22.307 ;
     RECT  40.2 2.151 40.512 22.645 ;
     RECT  25.296 18.757 25.32 22.739 ;
     RECT  24 2.151 24.312 22.741 ;
     RECT  15.9 21.829 16.68 22.979 ;
     RECT  21.3 21.731 21.768 23.269 ;
     RECT  37.5 2.151 37.812 23.317 ;
     RECT  39.648 22.645 40.512 23.317 ;
     RECT  15.9 22.979 16.344 23.365 ;
     RECT  7.8 22.021 9.096 23.555 ;
     RECT  37.5 23.317 40.512 23.603 ;
     RECT  15.312 23.365 16.344 24.323 ;
     RECT  18.6 22.307 18.912 24.373 ;
     RECT  29.4 2.151 29.712 24.997 ;
     RECT  24 22.741 24.84 25.045 ;
     RECT  7.8 23.555 8.568 25.091 ;
     RECT  12.96 22.165 13.656 25.091 ;
     RECT  18.48 24.373 18.912 25.139 ;
     RECT  37.5 23.603 38.712 25.139 ;
     RECT  15.9 24.323 16.344 25.331 ;
     RECT  24 25.045 25.224 25.715 ;
     RECT  7.8 25.091 8.112 26.197 ;
     RECT  7.8 26.197 8.376 26.245 ;
     RECT  10.5 21.539 10.812 26.533 ;
     RECT  13.2 25.091 13.656 26.627 ;
     RECT  32.1 2.151 32.412 26.725 ;
     RECT  21.168 23.269 21.768 26.915 ;
     RECT  26.7 2.151 27.012 27.061 ;
     RECT  24 25.715 24.648 27.107 ;
     RECT  34.8 2.151 35.112 27.157 ;
     RECT  37.5 25.139 37.944 27.203 ;
     RECT  22.896 26.725 22.92 27.205 ;
     RECT  24 27.107 24.312 27.205 ;
     RECT  22.896 27.205 24.312 27.251 ;
     RECT  6.816 26.245 8.376 27.299 ;
     RECT  26.352 27.061 27.012 27.301 ;
     RECT  31.344 26.725 32.412 27.301 ;
     RECT  20.16 22.501 20.184 27.541 ;
     RECT  21.168 26.915 21.612 27.541 ;
     RECT  29.28 24.997 29.712 27.875 ;
     RECT  15.9 25.331 16.212 27.877 ;
     RECT  34.8 27.157 35.592 28.261 ;
     RECT  10.5 26.533 11.592 28.451 ;
     RECT  31.344 27.301 32.856 28.643 ;
     RECT  15.552 27.877 16.212 28.691 ;
     RECT  20.16 27.541 21.612 28.931 ;
     RECT  31.344 28.643 32.412 28.981 ;
     RECT  40.2 23.603 40.512 28.981 ;
     RECT  30.816 28.981 32.412 29.027 ;
     RECT  34.8 28.261 35.928 29.029 ;
     RECT  7.8 27.299 8.376 29.219 ;
     RECT  21.3 28.931 21.612 29.317 ;
     RECT  23.328 27.251 24.312 29.317 ;
     RECT  25.44 27.301 27.012 29.317 ;
     RECT  21.3 29.317 22.248 29.605 ;
     RECT  23.328 29.317 27.012 29.605 ;
     RECT  30.816 29.027 30.84 30.323 ;
     RECT  34.128 29.029 35.928 30.323 ;
     RECT  21.3 29.605 27.012 30.419 ;
     RECT  10.5 28.451 10.812 30.709 ;
     RECT  15.9 28.691 16.212 30.709 ;
     RECT  26.352 30.419 27.012 30.803 ;
     RECT  15.9 30.709 17.112 30.851 ;
     RECT  39.456 28.981 40.512 30.851 ;
     RECT  27.984 29.605 28.008 30.995 ;
     RECT  29.4 27.875 29.712 31.141 ;
     RECT  7.8 29.219 8.112 31.333 ;
     RECT  21.3 30.419 24.84 31.379 ;
     RECT  34.128 30.323 35.592 31.379 ;
     RECT  23.136 31.379 24.84 31.619 ;
     RECT  20.16 28.931 20.184 31.909 ;
     RECT  23.328 31.619 24.84 31.955 ;
     RECT  10.368 30.709 10.812 32.339 ;
     RECT  21.3 31.379 21.612 32.341 ;
     RECT  13.2 26.627 13.608 32.389 ;
     RECT  10.5 32.339 10.812 32.437 ;
     RECT  15.9 30.851 16.344 32.437 ;
     RECT  26.7 30.803 27.012 32.725 ;
     RECT  28.704 31.141 29.712 32.725 ;
     RECT  23.328 31.955 24.696 32.867 ;
     RECT  26.7 32.725 29.712 32.867 ;
     RECT  15.408 32.437 16.344 32.869 ;
     RECT  28.704 32.867 29.712 33.107 ;
     RECT  7.8 31.333 8.232 33.251 ;
     RECT  13.2 32.389 14.088 33.251 ;
     RECT  34.8 31.379 35.592 33.493 ;
     RECT  13.2 33.251 13.512 33.589 ;
     RECT  30.816 32.341 30.84 33.683 ;
     RECT  10.5 32.437 11.4 34.115 ;
     RECT  20.16 31.909 20.28 34.595 ;
     RECT  31.968 29.027 32.412 34.645 ;
     RECT  15.408 32.869 17.016 34.691 ;
     RECT  29.4 33.107 29.712 34.789 ;
     RECT  15.408 34.691 16.584 34.835 ;
     RECT  31.968 34.645 33 34.931 ;
     RECT  12.528 33.589 13.512 35.077 ;
     RECT  15.408 34.835 16.212 35.077 ;
     RECT  21.3 32.341 21.96 35.221 ;
     RECT  7.8 33.251 8.112 35.317 ;
     RECT  18.6 25.139 18.912 35.413 ;
     RECT  20.16 34.595 20.184 35.413 ;
     RECT  7.44 35.317 8.112 35.843 ;
     RECT  18.6 35.413 20.184 35.893 ;
     RECT  37.5 27.203 37.812 36.085 ;
     RECT  32.1 34.931 33 36.517 ;
     RECT  37.392 36.085 37.812 36.611 ;
     RECT  28.464 34.789 29.712 36.661 ;
     RECT  27.984 36.661 29.712 36.707 ;
     RECT  17.664 35.893 20.184 36.755 ;
     RECT  23.328 32.867 24.312 36.949 ;
     RECT  9.12 35.845 9.144 37.139 ;
     RECT  23.328 36.949 24.408 37.475 ;
     RECT  12.528 35.077 16.212 37.619 ;
     RECT  26.7 32.867 27.012 37.621 ;
     RECT  15.408 37.619 16.212 37.667 ;
     RECT  27.984 36.707 28.008 37.861 ;
     RECT  29.4 36.707 29.712 37.861 ;
     RECT  34.8 33.493 35.736 37.907 ;
     RECT  32.1 36.517 33.096 38.099 ;
     RECT  23.328 37.475 24.312 38.149 ;
     RECT  27.984 37.861 29.712 38.195 ;
     RECT  21.168 35.221 21.96 38.485 ;
     RECT  23.28 38.149 24.312 38.485 ;
     RECT  37.5 36.611 37.812 38.629 ;
     RECT  21.168 38.485 24.312 38.819 ;
     RECT  25.92 37.621 27.012 38.915 ;
     RECT  21.3 38.819 24.312 39.109 ;
     RECT  28.464 38.195 29.712 39.251 ;
     RECT  37.392 38.629 37.812 39.443 ;
     RECT  18.6 36.755 20.184 39.923 ;
     RECT  21.3 39.109 24.552 39.923 ;
     RECT  24 39.923 24.552 40.067 ;
     RECT  20.16 39.923 20.184 40.981 ;
     RECT  21.3 39.923 23.016 40.981 ;
     RECT  2.4 2.151 2.712 41.049 ;
     RECT  5.1 16.835 5.412 41.049 ;
     RECT  7.8 35.843 8.112 41.049 ;
     RECT  10.5 34.115 10.812 41.049 ;
     RECT  13.2 37.619 13.512 41.049 ;
     RECT  15.9 37.667 16.212 41.049 ;
     RECT  18.6 39.923 18.912 41.049 ;
     RECT  24 40.067 24.312 41.049 ;
     RECT  26.7 38.915 27.012 41.049 ;
     RECT  29.4 39.251 29.712 41.049 ;
     RECT  32.1 38.099 32.412 41.049 ;
     RECT  34.8 37.907 35.112 41.049 ;
     RECT  37.5 39.443 37.812 41.049 ;
     RECT  40.2 30.851 40.512 41.049 ;
     RECT  2.4 41.049 2.52 41.063 ;
     RECT  5.1 41.049 5.22 41.063 ;
     RECT  7.8 41.049 7.92 41.063 ;
     RECT  10.5 41.049 10.62 41.063 ;
     RECT  13.2 41.049 13.32 41.063 ;
     RECT  15.9 41.049 16.02 41.063 ;
     RECT  18.6 41.049 18.72 41.063 ;
     RECT  20.16 40.981 23.016 41.063 ;
     RECT  24 41.049 24.12 41.063 ;
     RECT  26.7 41.049 26.82 41.063 ;
     RECT  29.4 41.049 29.52 41.063 ;
     RECT  32.1 41.049 32.22 41.063 ;
     RECT  34.8 41.049 34.92 41.063 ;
     RECT  37.5 41.049 37.62 41.063 ;
     RECT  40.2 41.049 40.32 41.063 ;
     RECT  20.16 41.063 20.472 42.181 ;
     RECT  21.456 41.063 23.016 42.181 ;
     RECT  20.16 42.181 23.016 43.152 ;
  END
END qkd_kvn_ctx_ovl_rope
END LIBRARY
